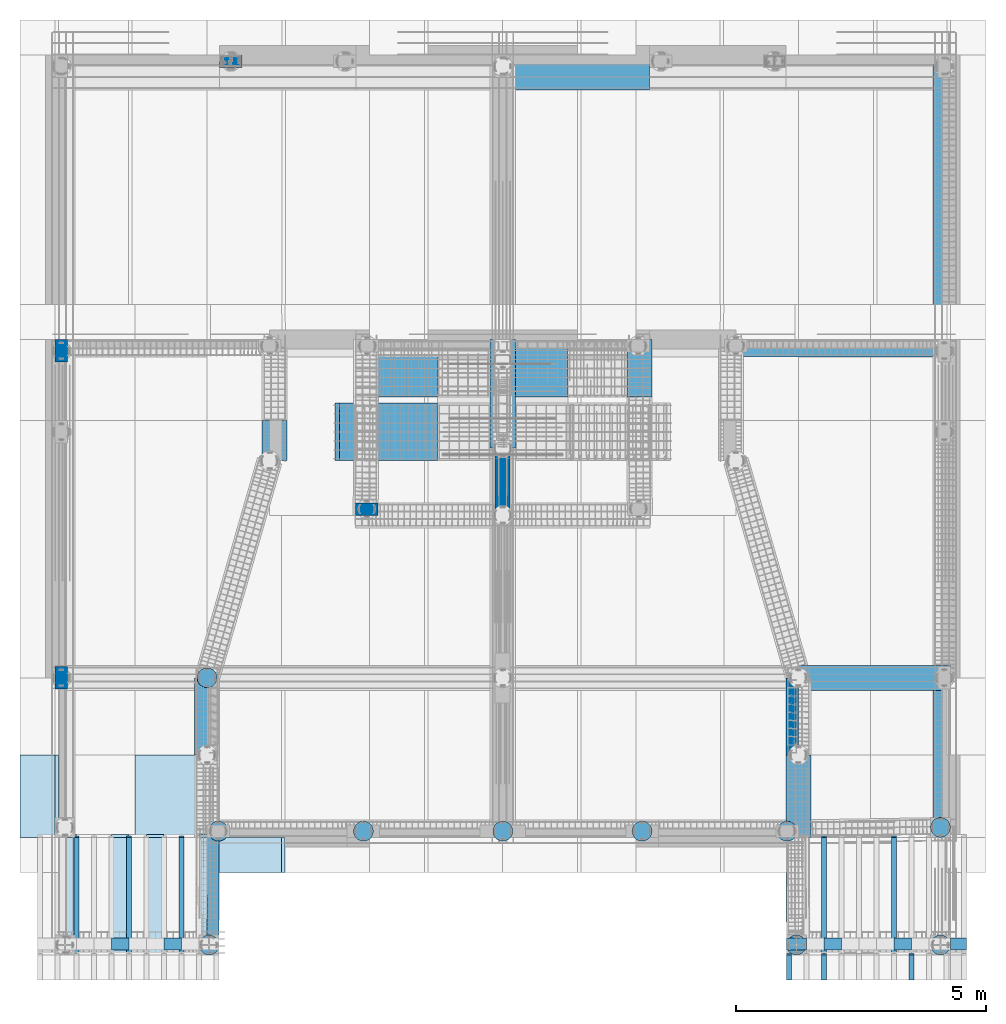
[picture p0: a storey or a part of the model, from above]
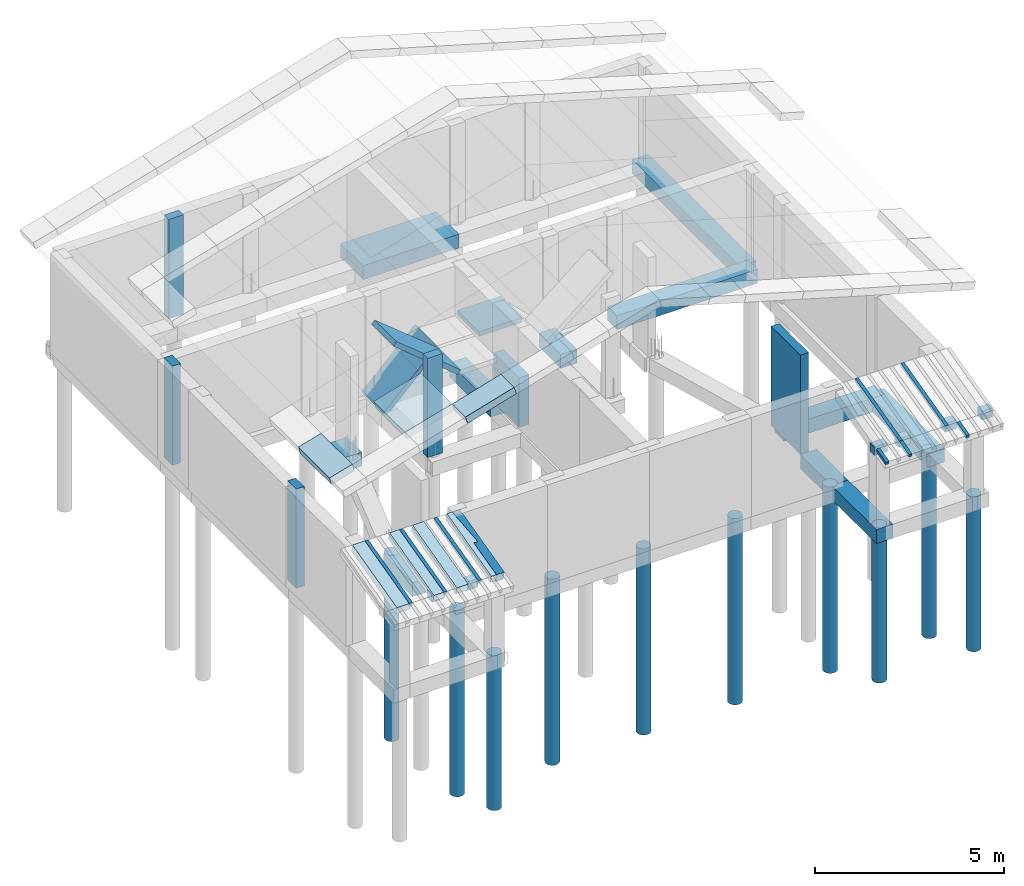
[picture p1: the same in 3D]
Properties of the parts of a building model (IFC4), part 1 of 5

# File
Description: ViewDefinition [CoordinationView]
Made in: IFC file generated by ModeSt (Tecnisoft s.a.s.)

# IfcBuildingStorey (2)
In: Villa
Name | Elevation (m)
Storey 0 | 0
Storey 1 | 3.2

# IfcBeam: 11 TRV SUI PALI (50)
In: Storey 0
Type - PredefinedType: BEAM; Material: Calcestruzzo classe C28/35
Description: 11 TRV SUI PALI - Cemento armato
Pset_BeamCommon - LoadBearing: yes
BaseQuantities - ?: 0.225 m2
Name | BaseQuantities, ? (m3) | BaseQuantities, ? (m)
2 x 4005 | 0.684 | 3.04
2 x 4005 | 1.32975 | 5.91
4049 | 0.3465 | 1.54
2 x 4003 | 0.63 | 2.8
4024 | 0.18 | 0.8
4030 | 0.48825 | 2.17
4030 | 1.28025 | 5.69
4030 | 0.73125 | 3.25
4030 | 0.71775 | 3.19
4030 | 0.3015 | 1.34
4013 | 0.71775 | 3.19
4013 | 1.1565 | 5.14
4013 | 0.3645 | 1.62
4013 | 1.28025 | 5.69
4013 | 0.52875 | 2.35
4059 | 0.738 | 3.28
4049 | 0.5315 | 2.36222
2 x 4003 | 0.69975 | 3.11
4049 | 0.37125 | 1.65
4051 | 1.0162 | 4.51643
4024 | 0.3645 | 1.62
2 x 4010 | 0.96525 | 4.29
2 x 4010 | 0.38925 | 1.73
2 x 4010 | 0.65925 | 2.93
4056 | 0.25875 | 1.15
2 x 4006 | 0.6615 | 2.94
4056 | 0.531005 | 2.36002
4050 | 0.3465 | 1.54
4036 | 0.18 | 0.8
4047 | 0.71775 | 3.19
4047 | 1.1565 | 5.14
4047 | 0.3645 | 1.62
4047 | 1.28025 | 5.69
4047 | 0.52875 | 2.35
4117 | 0.738 | 3.28
4050 | 0.5315 | 2.36222
4003 | 0.684 | 3.04
4050 | 0.37125 | 1.65
4052 | 1.0162 | 4.51643
4036 | 0.3645 | 1.62
4055 | 0.25875 | 1.15
4055 | 0.531005 | 2.36002

# IfcBeam: 14 TRAVE 30X45, 1030
In: Storey 1
Type - PredefinedType: BEAM; Material: Calcestruzzo classe C28/35
Description: 14 TRAVE 30X45 - Cemento armato
Pset_BeamCommon - LoadBearing: yes
BaseQuantities - ?: 0.135 m2; ?: 0.76815 m3; ?: 5.69 m

# IfcBeam: 16 TRAVE 30X30 (8)
In: Storey 1
Type - PredefinedType: BEAM; Material: Calcestruzzo classe C28/35
Description: 16 TRAVE 30X30 - Cemento armato
Pset_BeamCommon - LoadBearing: yes
BaseQuantities - ?: 0.09 m2
Name | BaseQuantities, ? (m3) | BaseQuantities, ? (m)
1030 | 0.2871 | 3.19
1030 | 0.2925 | 3.25
1030 | 0.1953 | 2.17
1030 | 0.1206 | 1.34
2088 | 0.2871 | 3.19
2088 | 0.2925 | 3.25
2088 | 0.1206 | 1.34
2088 | 0.1953 | 2.17

# IfcBeam: 17 TRAVE TAVOLA LEGNO 25X25 CA (4)
In: Storey 1
Type - PredefinedType: BEAM; Material: Calcestruzzo classe C28/35
Description: 17 TRAVE TAVOLA LEGNO 25X25 CA - Cemento armato
Pset_BeamCommon - LoadBearing: yes
BaseQuantities - ?: 0.0625 m2
Name | BaseQuantities, ? (m3) | BaseQuantities, ? (m)
2004 | 0.104225 | 1.6676
2004 | 0.0935769 | 1.49723
2062 | 0.104225 | 1.6676
2062 | 0.093577 | 1.49723

# IfcBeam: 20 TRAVE 30X30, 2204
In: Storey 1
Type - PredefinedType: BEAM; Material: Calcestruzzo classe C28/35
Description: 20 TRAVE 30X30 - Cemento armato
Pset_BeamCommon - LoadBearing: yes
BaseQuantities - ?: 0.09 m2; ?: 0.5121 m3; ?: 5.69 m

# IfcBeam: 21 TRV winkler SUI PALI (6)
In: Storey 0
Type - PredefinedType: BEAM; Material: Calcestruzzo classe C28/35
Description: 21 TRV winkler SUI PALI - Cemento armato
Pset_BeamCommon - LoadBearing: yes
BaseQuantities - ?: 0.54 m2
Name | BaseQuantities, ? (m3) | BaseQuantities, ? (m)
2 x 4011 | 1.7766 | 3.29
2 x 4011 | 1.4742 | 2.73
2 x 4011 | 1.5822 | 2.93

# IfcBeam: 22 Scala (8)
In: Storey 0
Type - PredefinedType: BEAM; Material: Calcestruzzo classe C28/35
Description: 22 Scala - Cemento armato
Pset_BeamCommon - LoadBearing: yes
BaseQuantities - ?: 0.1725 m2
Name | BaseQuantities, ? (m3) | BaseQuantities, ? (m)
2 x 4068 | 0.22425 | 1.3
2 x 4068 | 0.393999 | 2.28405
2 x 1009 | 0.22425 | 1.3
2 x 1009 | 0.436449 | 2.53014

# IfcBeam: 3 TRAVE 25X50 (200)
In: Storey 1
Type - PredefinedType: BEAM; Material: Calcestruzzo classe C28/35
Description: 3 TRAVE 25X50 - Cemento armato
Pset_BeamCommon - LoadBearing: yes
BaseQuantities - ?: 0.125 m2
Name | BaseQuantities, ? (m3) | BaseQuantities, ? (m)
2 x 1061 | 0.05375 | 0.43
2 x 1061 | 0.18625 | 1.49
2 x 1061 | 0.05625 | 0.45
2 x 1010 | 0.18375 | 1.47
2 x 1010 | 0.03125 | 0.25
2 x 1011 | 0.18375 | 1.47
2 x 1011 | 0.15625 | 1.25
1010 | 0.03375 | 0.27
1082 | 0.2025 | 1.62
1024 | 0.13625 | 1.09
2 x 1006 | 0.03 | 0.24
2 x 1006 | 0.035 | 0.28
2 x 1007 | 0.075 | 0.6
2 x 1005 | 0.18625 | 1.49
2 x 1005 | 0.2 | 1.6
1011 | 0.03375 | 0.27
1008 | 0.2 | 1.6
1008 | 0.18 | 1.44
2 x 1005 | 0.18 | 1.44
1008 | 0.15625 | 1.25
2 x 1061 | 0.16375 | 1.31
2 x 1061 | 0.195 | 1.56
2 x 1006 | 0.185 | 1.48
2 x 1005 | 0.22 | 1.76
2 x 1006 | 0.195 | 1.56
2 x 1007 | 0.197488 | 1.5799
2 x 1005 | 0.195 | 1.56
2 x 1061 | 0.1375 | 1.1
2 x 1006 | 0.1375 | 1.1
2 x 1005 | 0.1375 | 1.1
2 x 1007 | 0.1375 | 1.1
2 x 1010 | 0.19625 | 1.57
2 x 1010 | 0.15625 | 1.25
2 x 1011 | 0.19625 | 1.57
2 x 1011 | 0.03125 | 0.25
2 x 1010 | 0.14375 | 1.15
2 x 1010 | 0.195 | 1.56
2 x 1011 | 0.185 | 1.48
2 x 1011 | 0.195 | 1.56
2 x 1010 | 0.1375 | 1.1
2 x 1011 | 0.1375 | 1.1
1023 | 0.20625 | 1.65
2 x 2011 | 0.202951 | 1.62361
2 x 2011 | 0.19145 | 1.5316
2 x 2011 | 0.1954 | 1.5632
2 x 2011 | 0.204152 | 1.63322
2 x 2011 | 0.19265 | 1.5412
2 x 2011 | 0.1432 | 1.1456
2 x 2010 | 0.19145 | 1.5316
2 x 2010 | 0.204152 | 1.63322
2 x 2010 | 0.162951 | 1.30361
2 x 2010 | 0.19265 | 1.5412
2 x 2010 | 0.202951 | 1.62361
2 x 2010 | 0.1432 | 1.1456
2011 | 0.0352003 | 0.281603
2010 | 0.0352003 | 0.281603
2 x 2010 | 0.0324519 | 0.259615
2 x 2068 | 0.162951 | 1.30361
2 x 2068 | 0.19265 | 1.5412
2 x 2068 | 0.202951 | 1.62361
2 x 2068 | 0.1432 | 1.1456
2068 | 0.0352003 | 0.281603
2 x 2068 | 0.0324519 | 0.259615
1061 | 0.02875 | 0.23
10 x 1061 | 0.04375 | 0.35
1061 | 0.015 | 0.12
1061 | 0.02 | 0.16
2003 | 0.194201 | 1.55361
2003 | 0.0585502 | 0.468401
2082 | 0.2025 | 1.62
2024 | 0.13625 | 1.09
2 x 2006 | 0.03125 | 0.25
2 x 2006 | 0.0364005 | 0.291204
2 x 2005 | 0.194201 | 1.55361
2 x 2005 | 0.20845 | 1.6676
2008 | 0.20845 | 1.6676
2008 | 0.187154 | 1.49723
2 x 2005 | 0.187154 | 1.49723
2008 | 0.162951 | 1.30361
2003 | 0.1705 | 1.364
2003 | 0.202951 | 1.62361
2 x 2006 | 0.19265 | 1.5412
2 x 2005 | 0.22905 | 1.8324
2 x 2006 | 0.202951 | 1.62361
2 x 2005 | 0.202951 | 1.62361
2003 | 0.1432 | 1.1456
2 x 2006 | 0.1432 | 1.1456
2 x 2005 | 0.1432 | 1.1456
2081 | 0.20625 | 1.65
2 x 2068 | 0.187154 | 1.49723
2 x 2068 | 0.20845 | 1.6676
2003 | 0.187154 | 1.49723
2003 | 0.20845 | 1.6676
2 x 1007 | 0.175 | 1.4
2 x 1010 | 0.04125 | 0.33
1061 | 0.0443749 | 0.355
1010 | 0.0337501 | 0.27
1094 | 0.2025 | 1.62
1036 | 0.13625 | 1.09
1011 | 0.0337501 | 0.27
1066 | 0.2 | 1.6
1066 | 0.18 | 1.44
1066 | 0.15625 | 1.25
1037 | 0.20625 | 1.65
2011 | 0.0352004 | 0.281603
2010 | 0.0352004 | 0.281603
2068 | 0.0352004 | 0.281603
1061 | 0.028125 | 0.225
1061 | 0.0437499 | 0.349999
1061 | 0.0200001 | 0.160001
1061 | 0.0149999 | 0.119999
2002 | 0.194201 | 1.55361
2002 | 0.0585502 | 0.468401
2094 | 0.2025 | 1.62
2036 | 0.13625 | 1.09
2066 | 0.20845 | 1.6676
2066 | 0.187154 | 1.49723
2066 | 0.162951 | 1.30361
2002 | 0.1705 | 1.364
2002 | 0.202951 | 1.62361
2002 | 0.1432 | 1.1456
2095 | 0.20625 | 1.65
2002 | 0.187158 | 1.49726
2002 | 0.208454 | 1.66763

# IfcBeam: 5 TRAVE TAVOLA LEGNO 16X20 (4)
In: Storey 1
Type - PredefinedType: BEAM; Material: Calcestruzzo classe C28/35
Description: 5 TRAVE TAVOLA LEGNO 16X20 - Cemento armato
Pset_BeamCommon - LoadBearing: yes
BaseQuantities - ?: 0.032 m2
Name | BaseQuantities, ? (m3) | BaseQuantities, ? (m)
1004 | 0.0512 | 1.6
1004 | 0.04608 | 1.44
1062 | 0.0512 | 1.6
1062 | 0.04608 | 1.44

# IfcBeam: 6 TRAVE LEGNO 24X28 (44)
Type - PredefinedType: BEAM; Material: Legname a media elasticità
Description: 6 TRAVE LEGNO 24X28 - Legno
Pset_BeamCommon - LoadBearing: yes
BaseQuantities - ?: 0.0672 m2
Name | In | BaseQuantities, ? (m3) | BaseQuantities, ? (m)
1013 | Storey 0 | 0.162986 | 2.42539
1049 | Storey 0 | 0.163782 | 2.43723
1047 | Storey 0 | 0.162986 | 2.42539
1050 | Storey 0 | 0.163782 | 2.43723
1053 | Storey 1 | 0.345408 | 5.14
1081 | Storey 1 | 0.345408 | 5.14
1025 | Storey 1 | 0.214368 | 3.19
1025 | Storey 1 | 0.2184 | 3.25
1029 | Storey 1 | 0.214368 | 3.19
1029 | Storey 1 | 0.2184 | 3.25
1029 | Storey 1 | 0.073248 | 1.09
1028 | Storey 1 | 0.214368 | 3.19
1028 | Storey 1 | 0.2184 | 3.25
1028 | Storey 1 | 0.073248 | 1.09
1053 | Storey 1 | 0.382368 | 5.69
1081 | Storey 1 | 0.382368 | 5.69
1087 | Storey 1 | 0.382368 | 5.69
1086 | Storey 1 | 0.382368 | 5.69
1026 | Storey 1 | 0.382368 | 5.69
1053 | Storey 1 | 0.109214 | 1.62521
1081 | Storey 1 | 0.108864 | 1.62
1053 | Storey 1 | 0.11088 | 1.65
1053 | Storey 1 | 0.103488 | 1.54
1003 | Storey 1 | 0.02352 | 0.35
1054 | Storey 1 | 0.345408 | 5.14
1095 | Storey 1 | 0.345408 | 5.14
1035 | Storey 1 | 0.214368 | 3.19
1035 | Storey 1 | 0.2184 | 3.25
1031 | Storey 1 | 0.214368 | 3.19
1031 | Storey 1 | 0.2184 | 3.25
1031 | Storey 1 | 0.073248 | 1.09
1032 | Storey 1 | 0.214368 | 3.19
1032 | Storey 1 | 0.2184 | 3.25
1032 | Storey 1 | 0.073248 | 1.09
1054 | Storey 1 | 0.382368 | 5.69
1095 | Storey 1 | 0.382368 | 5.69
1089 | Storey 1 | 0.382368 | 5.69
1090 | Storey 1 | 0.382368 | 5.69
1034 | Storey 1 | 0.382368 | 5.69
1054 | Storey 1 | 0.109214 | 1.62521
1095 | Storey 1 | 0.108864 | 1.62
1054 | Storey 1 | 0.11088 | 1.65
1054 | Storey 1 | 0.103488 | 1.54
1119 | Storey 1 | 0.0215039 | 0.319998

# IfcBeam: 7 TRAVE 25X30 (26)
Type - PredefinedType: BEAM; Material: Calcestruzzo classe C28/35
Description: 7 TRAVE 25X30 - Cemento armato
Pset_BeamCommon - LoadBearing: yes
BaseQuantities - ?: 0.075 m2
Name | In | BaseQuantities, ? (m3) | BaseQuantities, ? (m)
4088 | Storey 0 | 0.0675 | 0.9
4088 | Storey 0 | 0.09525 | 1.27
1071 | Storey 1 | 0.12375 | 1.65
1071 | Storey 1 | 0.3855 | 5.14
1071 | Storey 1 | 0.1215 | 1.62
1071 | Storey 1 | 0.42675 | 5.69
1071 | Storey 1 | 0.1155 | 1.54
2187 | Storey 1 | 0.42675 | 5.69
2071 | Storey 1 | 0.1215 | 1.62
2071 | Storey 1 | 0.12375 | 1.65
2071 | Storey 1 | 0.1155 | 1.54
2071 | Storey 1 | 0.3855 | 5.14
1027 | Storey 1 | 0.08625 | 1.15
1027 | Storey 1 | 0.09525 | 1.27
1105 | Storey 1 | 0.12375 | 1.65
1105 | Storey 1 | 0.3855 | 5.14
1105 | Storey 1 | 0.1215 | 1.62
1105 | Storey 1 | 0.42675 | 5.69
1105 | Storey 1 | 0.1155 | 1.54
2221 | Storey 1 | 0.42675 | 5.69
2105 | Storey 1 | 0.1215 | 1.62
2105 | Storey 1 | 0.12375 | 1.65
2105 | Storey 1 | 0.1155 | 1.54
2105 | Storey 1 | 0.3855 | 5.14
1033 | Storey 1 | 0.08625 | 1.15
1033 | Storey 1 | 0.09525 | 1.27

# IfcBeam: 8 CORRENTE 10X10 (40)
In: Storey 0
Type - PredefinedType: BEAM; Material: Legname a media elasticità
Description: 8 CORRENTE 10X10 - Legno
Pset_BeamCommon - LoadBearing: yes
BaseQuantities - ?: 0.01 m2
Name | BaseQuantities, ? (m3) | BaseQuantities, ? (m)
1014 | 0.0242539 | 2.42539
1015 | 0.0242539 | 2.42539
1016 | 0.0242539 | 2.42539
1017 | 0.0242539 | 2.42539
1019 | 0.0242539 | 2.42539
1020 | 0.0242539 | 2.42539
1021 | 0.0242539 | 2.42539
1022 | 0.0051604 | 0.51604
1022 | 0.0242539 | 2.42539
1021 | 0.0051604 | 0.51604
1020 | 0.0051604 | 0.51604
1019 | 0.0051604 | 0.51604
1017 | 0.0051604 | 0.51604
1016 | 0.0051604 | 0.51604
1015 | 0.0051604 | 0.51604
1014 | 0.0051604 | 0.51604
1013 | 0.0051604 | 0.51604
1049 | 0.0051604 | 0.51604
1012 | 0.0051604 | 0.51604
1012 | 0.0242539 | 2.42539
1041 | 0.0242539 | 2.42539
1046 | 0.0242539 | 2.42539
1045 | 0.0242539 | 2.42539
1044 | 0.0242539 | 2.42539
1043 | 0.0242539 | 2.42539
1040 | 0.0242539 | 2.42539
1039 | 0.0242539 | 2.42539
1038 | 0.0242539 | 2.42539
1038 | 0.00516624 | 0.516624
1039 | 0.00516624 | 0.516624
1040 | 0.00516624 | 0.516624
1044 | 0.00516624 | 0.516624
1045 | 0.00516624 | 0.516624
1046 | 0.00516624 | 0.516624
1047 | 0.00516624 | 0.516624
1050 | 0.00516624 | 0.516624
1043 | 0.00516624 | 0.516624
1041 | 0.00516624 | 0.516624
1048 | 0.00516624 | 0.516624
1048 | 0.0242539 | 2.42539

# IfcBeam: 9 TRAVE LEGNO 24X28 COPERTURA (99)
Type - PredefinedType: BEAM; Material: Legname a media elasticità
Description: 9 TRAVE LEGNO 24X28 COPERTURA - Legno
Pset_BeamCommon - LoadBearing: yes
BaseQuantities - ?: 0.0672 m2
Name | In | BaseQuantities, ? (m3) | BaseQuantities, ? (m)
4001 | Storey 0 | 0.028896 | 0.43
8 x 4001 | Storey 0 | 0.02352 | 0.35
4001 | Storey 0 | 0.02688 | 0.4
4175 | Storey 0 | 0.023856 | 0.355
4175 | Storey 0 | 0.028896 | 0.43
4 x 4175 | Storey 0 | 0.02352 | 0.35
4175 | Storey 0 | 0.023184 | 0.344999
4175 | Storey 0 | 0.02352 | 0.349999
4175 | Storey 0 | 0.02688 | 0.400001
4175 | Storey 0 | 0.0215039 | 0.319998
2053 | Storey 1 | 0.382368 | 5.69
2197 | Storey 1 | 0.382368 | 5.69
2087 | Storey 1 | 0.382368 | 5.69
2086 | Storey 1 | 0.382368 | 5.69
2026 | Storey 1 | 0.382368 | 5.69
2018 | Storey 1 | 0.108864 | 1.62
2139 | Storey 1 | 0.103488 | 1.54
2018 | Storey 1 | 0.345408 | 5.14
2139 | Storey 1 | 0.345408 | 5.14
2025 | Storey 1 | 0.214368 | 3.19
2025 | Storey 1 | 0.2184 | 3.25
2029 | Storey 1 | 0.214368 | 3.19
2029 | Storey 1 | 0.2184 | 3.25
2029 | Storey 1 | 0.235872 | 3.51
2028 | Storey 1 | 0.214368 | 3.19
2028 | Storey 1 | 0.2184 | 3.25
2028 | Storey 1 | 0.235872 | 3.51
2139 | Storey 1 | 0.108864 | 1.62
2023 | Storey 1 | 0.04704 | 0.7
2025 | Storey 1 | 0.04704 | 0.7
2 x 2028 | Storey 1 | 0.04704 | 0.7
2 x 2029 | Storey 1 | 0.04704 | 0.7
2030 | Storey 1 | 0.04704 | 0.7
2139 | Storey 1 | 0.04704 | 0.7
2146 | Storey 1 | 0.04704 | 0.7
2057 | Storey 1 | 0.0470448 | 0.700071
2018 | Storey 1 | 0.11088 | 1.65
2018 | Storey 1 | 0.103488 | 1.54
2013 | Storey 1 | 0.04704 | 0.7
2129 | Storey 1 | 0.04704 | 0.7
2 x 2018 | Storey 1 | 0.04704 | 0.7
2053 | Storey 1 | 0.04704 | 0.700001
2197 | Storey 1 | 0.04704 | 0.700001
2026 | Storey 1 | 0.04704 | 0.700001
2087 | Storey 1 | 0.04704 | 0.700001
2086 | Storey 1 | 0.04704 | 0.700001
2262 | Storey 1 | 0.04704 | 0.700001
2245 | Storey 1 | 0.04704 | 0.700001
2054 | Storey 1 | 0.382368 | 5.69
2211 | Storey 1 | 0.382368 | 5.69
2089 | Storey 1 | 0.382368 | 5.69
2090 | Storey 1 | 0.382368 | 5.69
2034 | Storey 1 | 0.382368 | 5.69
2042 | Storey 1 | 0.108864 | 1.62
2153 | Storey 1 | 0.103488 | 1.54
2042 | Storey 1 | 0.345408 | 5.14
2153 | Storey 1 | 0.345408 | 5.14
2035 | Storey 1 | 0.214368 | 3.19
2035 | Storey 1 | 0.2184 | 3.25
2031 | Storey 1 | 0.214368 | 3.19
2031 | Storey 1 | 0.2184 | 3.25
2031 | Storey 1 | 0.235872 | 3.51
2032 | Storey 1 | 0.214368 | 3.19
2032 | Storey 1 | 0.2184 | 3.25
2032 | Storey 1 | 0.235872 | 3.51
2153 | Storey 1 | 0.108864 | 1.62
2037 | Storey 1 | 0.04704 | 0.7
2035 | Storey 1 | 0.04704 | 0.7
2 x 2032 | Storey 1 | 0.04704 | 0.7
2 x 2031 | Storey 1 | 0.04704 | 0.7
2153 | Storey 1 | 0.04704 | 0.7
2058 | Storey 1 | 0.0470448 | 0.700071
2042 | Storey 1 | 0.111552 | 1.66
2042 | Storey 1 | 0.103488 | 1.54
2047 | Storey 1 | 0.04704 | 0.7
2163 | Storey 1 | 0.04704 | 0.7
2042 | Storey 1 | 0.04704 | 0.7
2042 | Storey 1 | 0.046368 | 0.69
2054 | Storey 1 | 0.04704 | 0.700001
2211 | Storey 1 | 0.04704 | 0.700001
2034 | Storey 1 | 0.04704 | 0.700001
2089 | Storey 1 | 0.04704 | 0.700001
2090 | Storey 1 | 0.04704 | 0.700001
2279 | Storey 1 | 0.04704 | 0.700001

# IfcColumn: 1 PILASTRO 25X45 (26)
Type - PredefinedType: COLUMN; Material: Calcestruzzo classe C28/35
Description: 1 PILASTRO 25X45 - Cemento armato
Pset_ColumnCommon - LoadBearing: yes
BaseQuantities - ?: 0.1125 m2
Name | In | BaseQuantities, ? (m3) | BaseQuantities, ? (m)
6 | Storey 0 | 0.36 | 3.2
17 | Storey 0 | 0.36 | 3.2
22 | Storey 0 | 0.36 | 3.2
23 | Storey 0 | 0.36 | 3.2
29 | Storey 0 | 0.36 | 3.2
30 | Storey 0 | 0.36 | 3.2
10 | Storey 0 | 0.36 | 3.2
18 | Storey 0 | 0.36 | 3.2
26 | Storey 0 | 0.36 | 3.2
25 | Storey 0 | 0.36 | 3.2
33 | Storey 0 | 0.36 | 3.2
32 | Storey 0 | 0.36 | 3.2
22 | Storey 1 | 0.219375 | 1.95
23 | Storey 1 | 0.275625 | 2.45
30 | Storey 1 | 0.275625 | 2.45
22 | Storey 1 | 0.21375 | 1.9
23 | Storey 1 | 0.21375 | 1.9
6 | Storey 1 | 0.3915 | 3.48
17 | Storey 1 | 0.489375 | 4.35
26 | Storey 1 | 0.219375 | 1.95
25 | Storey 1 | 0.275625 | 2.45
32 | Storey 1 | 0.275625 | 2.45
26 | Storey 1 | 0.21375 | 1.9
25 | Storey 1 | 0.21375 | 1.9
10 | Storey 1 | 0.3915 | 3.48
18 | Storey 1 | 0.489375 | 4.35

# IfcColumn: 1 muro pilastro (6)
Type - PredefinedType: COLUMN
Material: Calcestruzzo classe C28/35 0.25 m
Pset_WallCommon - LoadBearing: yes
Name | In | Description | BaseQuantities, ? (m2) | BaseQuantities, ? (m3) | BaseQuantities, ? (m)
35 | Storey 0 | Wall number 35 | 0.385 | 1.232 | 3.2
36 | Storey 0 | Wall number 36 | 0.2 | 0.64 | 3.2
38 | Storey 0 | Wall number 38 | 0.385 | 1.232 | 3.2
39 | Storey 0 | Wall number 39 | 0.2 | 0.64 | 3.2
36 | Storey 1 | Wall number 36 | 0.2 | 0.77 | 3.85
39 | Storey 1 | Wall number 39 | 0.2 | 0.77 | 3.85

# IfcColumn: 10 PILASTRO 40X25 (2)
In: Storey 1
Type - PredefinedType: COLUMN; Material: Calcestruzzo classe C28/35
Description: 10 PILASTRO 40X25 - Cemento armato
Pset_ColumnCommon - LoadBearing: yes
BaseQuantities - ?: 0.1 m2; ?: 0.348 m3; ?: 3.48 m
Name
12
13

# IfcColumn: 12 PILASTRO 25X65 (4)
Type - PredefinedType: COLUMN; Material: Calcestruzzo classe C28/35
Description: 12 PILASTRO 25X65 - Cemento armato
Pset_ColumnCommon - LoadBearing: yes
BaseQuantities - ?: 0.1625 m2
Name | In | BaseQuantities, ? (m3) | BaseQuantities, ? (m)
7 | Storey 0 | 0.52 | 3.2
9 | Storey 0 | 0.52 | 3.2
7 | Storey 1 | 0.69875 | 4.3
9 | Storey 1 | 0.69875 | 4.3

# IfcColumn: 13 PILASTRO 100X30 (2)
Type - PredefinedType: COLUMN; Material: Calcestruzzo classe C28/35
Description: 13 PILASTRO 100X30 - Cemento armato
Pset_ColumnCommon - LoadBearing: yes
BaseQuantities - ?: 0.3 m2
Name | In | BaseQuantities, ? (m3) | BaseQuantities, ? (m)
15 | Storey 0 | 0.96 | 3.2
15 | Storey 1 | 1.56 | 5.2

# IfcColumn: 15 PILASTRO 25x90 (2)
Type - PredefinedType: COLUMN; Material: Calcestruzzo classe C28/35
Description: 15 PILASTRO 25x90 - Cemento armato
Pset_ColumnCommon - LoadBearing: yes
BaseQuantities - ?: 0.225 m2
Name | In | BaseQuantities, ? (m3) | BaseQuantities, ? (m)
8 | Storey 0 | 0.72 | 3.2
8 | Storey 1 | 1.17 | 5.2

# IfcColumn: 18 PILASTRO 80x30 (4)
Type - PredefinedType: COLUMN; Material: Calcestruzzo classe C28/35
Description: 18 PILASTRO 80x30 - Cemento armato
Pset_ColumnCommon - LoadBearing: yes
BaseQuantities - ?: 0.24 m2
Name | In | BaseQuantities, ? (m3) | BaseQuantities, ? (m)
2 x 24 | Storey 0 | 0.384 | 1.6
24 | Storey 1 | 0.792 | 3.3
24 | Storey 1 | 0.456 | 1.9

# IfcColumn: 19 PILASTRO 45X30 (2)
Type - PredefinedType: COLUMN; Material: Calcestruzzo classe C28/35
Description: 19 PILASTRO 45X30 - Cemento armato
Pset_ColumnCommon - LoadBearing: yes
BaseQuantities - ?: 0.135 m2
Name | In | BaseQuantities, ? (m3) | BaseQuantities, ? (m)
31 | Storey 0 | 0.432 | 3.2
31 | Storey 1 | 0.4455 | 3.3

# IfcColumn: 2 PILASTRO 45X25 (18)
Type - PredefinedType: COLUMN; Material: Calcestruzzo classe C28/35
Description: 2 PILASTRO 45X25 - Cemento armato
Pset_ColumnCommon - LoadBearing: yes
BaseQuantities - ?: 0.1125 m2
Name | In | BaseQuantities, ? (m3) | BaseQuantities, ? (m)
14 | Storey 0 | 0.36 | 3.2
21 | Storey 0 | 0.36 | 3.2
19 | Storey 0 | 0.36 | 3.2
28 | Storey 0 | 0.36 | 3.2
16 | Storey 0 | 0.36 | 3.2
27 | Storey 0 | 0.36 | 3.2
20 | Storey 0 | 0.36 | 3.2
34 | Storey 0 | 0.36 | 3.2
21 | Storey 1 | 0.07875 | 0.7
28 | Storey 1 | 0.07875 | 0.7
21 | Storey 1 | 0.21375 | 1.9
19 | Storey 1 | 0.2925 | 2.6
14 | Storey 1 | 0.2925 | 2.6
27 | Storey 1 | 0.07875 | 0.7
34 | Storey 1 | 0.07875 | 0.7
27 | Storey 1 | 0.21375 | 1.9
20 | Storey 1 | 0.2925 | 2.6
16 | Storey 1 | 0.2925 | 2.6

# IfcColumn: 3 muro pilastro 30 centrale (3)
Type - PredefinedType: COLUMN
Description: Wall number 37; Material: Calcestruzzo classe C28/35 0.3 m
Pset_WallCommon - LoadBearing: yes
BaseQuantities - ?: 0.402 m2
Name | In | BaseQuantities, ? (m3) | BaseQuantities, ? (m)
2 x 37 | Storey 0 | 0.6432 | 1.6
37 | Storey 1 | 2.0904 | 5.2

# IfcColumn: 4 PILASTRO LOGGIATO 40X40 (8)
Type - PredefinedType: COLUMN; Material: Calcestruzzo classe C28/35
Description: 4 PILASTRO LOGGIATO 40X40 - Cemento armato
Pset_ColumnCommon - LoadBearing: yes
BaseQuantities - ?: 0.16 m2
Name | In | BaseQuantities, ? (m3) | BaseQuantities, ? (m)
1 | Storey 0 | 0.416 | 2.6
5 | Storey 0 | 0.512 | 3.2
2 | Storey 0 | 0.416 | 2.6
4 | Storey 0 | 0.416 | 2.6
11 | Storey 0 | 0.512 | 3.2
3 | Storey 0 | 0.416 | 2.6
5 | Storey 1 | 0.416 | 2.6
11 | Storey 1 | 0.416 | 2.6

# IfcPile (40)
In: Storey 0
PredefinedType: SUPPORT
Name | Description | ? (m3)
11 x 1 | 2 PALO FONDAZIONE 5 m | 0.628319
29 x 1 | 1 PALO FONDAZIONE 6 m | 0.753982

# IfcReinforcingBar (675)
SteelGrade: B450C
Name | In | NominalDiameter (m) | CrossSectionArea (m2) | BarLength (m)
4 x  | Storey 0 | 0.016 | 0.00020106 | 1.39193
4 x  | Storey 0 | 0.016 | 0.00020106 | 2.88943
4 x  | Storey 0 | 0.008 | 0.000050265 | 1.5788
2 x  | Storey 1 | 0.016 | 0.00020106 | 1.39193
14 x  | Storey 1 | 0.016 | 0.00020106 | 3.84
2 x  | Storey 1 | 0.016 | 0.00020106 | 2.88943
2 x  | Storey 1 | 0.008 | 0.000050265 | 1.5788
 | Storey 1 | 0.008 | 0.000050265 | 1.2086
9 x  | Storey 1 | 0.018 | 0.00025447 | 1.31973
9 x  | Storey 1 | 0.016 | 0.00020106 | 1.32193
10 x  | Storey 1 | 0.018 | 0.00025447 | 3.92
10 x  | Storey 1 | 0.016 | 0.00020106 | 3.92
 | Storey 1 | 0.018 | 0.00025447 | 3.61723
4 x  | Storey 1 | 0.016 | 0.00020106 | 3.61943
12 x  | Storey 1 | 0.008 | 0.000050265 | 1.37881
17 x  | Storey 1 | 0.008 | 0.000050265 | 0.428429
2 x  | Storey 1 | 0.018 | 0.00025447 | 4.43723
2 x  | Storey 1 | 0.016 | 0.00020106 | 4.43943
2 x  | Storey 1 | 0.008 | 0.000050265 | 1.7788
 | Storey 1 | 0.008 | 0.000050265 | 1.02152
3 x  | Storey 1 | 0.02 | 0.00031416 | 1.39754
3 x  | Storey 1 | 0.016 | 0.00020106 | 1.40193
3 x  | Storey 1 | 0.02 | 0.00031416 | 4
3 x  | Storey 1 | 0.016 | 0.00020106 | 4
 | Storey 1 | 0.02 | 0.00031416 | 5.33504
 | Storey 1 | 0.016 | 0.00020106 | 5.33943
 | Storey 1 | 0.008 | 0.000050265 | 2.27879
 | Storey 1 | 0.008 | 0.000050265 | 1.45481
3 x  | Storey 1 | 0.008 | 0.000050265 | 0.428428
 | Storey 1 | 0.008 | 0.000050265 | 1.02149
9 x  | Storey 1 | 0.016 | 0.00020106 | 1.24193
 | Storey 1 | 0.008 | 0.000050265 | 1.20881
5 x  | Storey 1 | 0.016 | 0.00020106 | 1.29193
2 x  | Storey 1 | 0.008 | 0.000050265 | 1.27881
2 x  | Storey 1 | 0.018 | 0.00025447 | 2.73723
6 x  | Storey 1 | 0.016 | 0.00020106 | 2.73943
3 x  | Storey 1 | 0.016 | 0.00020106 | 5.38943
 | Storey 1 | 0.008 | 0.000050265 | 2.57879
 | Storey 1 | 0.008 | 0.000050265 | 2.1654
2 x  | Storey 1 | 0.008 | 0.000050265 | 0.478429
 | Storey 1 | 0.008 | 0.000050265 | 2.35305
6 x  | Storey 1 | 0.008 | 0.000050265 | 1.3788
2 x  | Storey 1 | 0.008 | 0.000050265 | 0.42843
4 x  | Storey 1 | 0.016 | 0.00020106 | 4.48943
2 x  | Storey 1 | 0.022 | 0.00038013 | 1.47534
2 x  | Storey 1 | 0.016 | 0.00020106 | 1.48193
2 x  | Storey 1 | 0.022 | 0.00038013 | 4.08
2 x  | Storey 1 | 0.016 | 0.00020106 | 4.08
2 x  | Storey 1 | 0.022 | 0.00038013 | 2.73284
2 x  | Storey 1 | 0.018 | 0.00025447 | 3.98723
4 x  | Storey 1 | 0.016 | 0.00020106 | 3.98943
2 x  | Storey 1 | 0.008 | 0.000050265 | 0.478428
 | Storey 1 | 0.008 | 0.000050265 | 2.1788
 | Storey 1 | 0.008 | 0.000050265 | 1.85366
 | Storey 1 | 0.016 | 0.00020106 | 0.839429
4 x  | Storey 0 | 0.016 | 0.00020106 | 1.24193
4 x  | Storey 0 | 0.016 | 0.00020106 | 3.33943
2 x  | Storey 0 | 0.008 | 0.000050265 | 1.3788
 | Storey 0 | 0.008 | 0.000050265 | 0.428428
2 x  | Storey 1 | 0.016 | 0.00020106 | 2.58943
 | Storey 1 | 0.018 | 0.00025447 | 1.36973
 | Storey 1 | 0.016 | 0.00020106 | 1.37193
 | Storey 1 | 0.018 | 0.00025447 | 3.48723
 | Storey 1 | 0.016 | 0.00020106 | 3.48943
 | Storey 1 | 0.008 | 0.000050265 | 1.4788
2 x  | Storey 0 | 0.008 | 0.000050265 | 0.428429
 | Storey 1 | 0.016 | 0.00020106 | 0.83943
 | Storey 1 | 0.008 | 0.000050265 | 0.428427
2 x  | Storey 0 | 0.008 | 0.000050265 | 3.55879
 | Storey 0 | 0.008 | 0.000050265 | 0.42843
2 x  | Storey 0 | 0.008 | 0.000050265 | 2.26457
2 x  | Storey 0 | 0.008 | 0.000050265 | 2.91168
2 x  | Storey 1 | 0.02 | 0.00031416 | 3.98504
2 x  | Storey 1 | 0.008 | 0.000050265 | 2.0788
2 x  | Storey 1 | 0.008 | 0.000050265 | 1.11882
 | Storey 1 | 0.008 | 0.000050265 | 2.0031
2 x  | Storey 1 | 0.008 | 0.000050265 | 3.25879
 | Storey 1 | 0.008 | 0.000050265 | 2.95158
 | Storey 1 | 0.008 | 0.000050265 | 1.37506
11 x  | Storey 0 | 0.016 | 0.00020106 | 5.6
40 x  | Storey 0 | 0.008 | 0.000050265 | 1.00616
29 x  | Storey 0 | 0.016 | 0.00020106 | 6.6
2 x  | Storey 1 | 0.008 | 0.000050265 | 0.638887
 | Storey 1 | 0.016 | 0.00020106 | 3.40121
8 x  | Storey 1 | 0.008 | 0.000050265 | 1.48681
 | Storey 1 | 0.016 | 0.00020106 | 10.9956
 | Storey 1 | 0.016 | 0.00020106 | 8.99561
 | Storey 1 | 0.018 | 0.00025447 | 10.9956
 | Storey 1 | 0.018 | 0.00025447 | 8.99561
2 x  | Storey 1 | 0.014 | 0.00015394 | 3
 | Storey 1 | 0.012 | 0.0001131 | 3.50121
 | Storey 1 | 0.012 | 0.0001131 | 6.33121
8 x  | Storey 1 | 0.008 | 0.000050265 | 1.4868
 | Storey 1 | 0.016 | 0.00020106 | 8.5
2 x  | Storey 1 | 0.016 | 0.00020106 | 1.69142
 | Storey 1 | 0.012 | 0.0001131 | 2.38121
2 x  | Storey 1 | 0.012 | 0.0001131 | 3.26121
2 x  | Storey 1 | 0.012 | 0.0001131 | 3.08121
 | Storey 1 | 0.016 | 0.00020106 | 9.6922
2 x  | Storey 1 | 0.012 | 0.0001131 | 5.02043
2 x  | Storey 1 | 0.012 | 0.0001131 | 5.0192
 | Storey 1 | 0.016 | 0.00020106 | 4.91121
2 x  | Storey 1 | 0.012 | 0.0001131 | 4.75121
2 x  | Storey 0 | 0.008 | 0.000050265 | 2.58679
 | Storey 0 | 0.014 | 0.00015394 | 3.8923
 | Storey 0 | 0.014 | 0.00015394 | 3.89798
2 x  | Storey 0 | 0.014 | 0.00015394 | 3.08814
2 x  | Storey 0 | 0.014 | 0.00015394 | 1.66861
 | Storey 0 | 0.02 | 0.00031416 | 2.38121
 | Storey 0 | 0.016 | 0.00020106 | 2.38121
 | Storey 0 | 0.016 | 0.00020106 | 2.1183
 | Storey 0 | 0.014 | 0.00015394 | 2.1183
19 x  | Storey 1 | 0.006 | 0.000028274 | 1.49179
 | Storey 1 | 0.016 | 0.00020106 | 5
2 x  | Storey 1 | 0.016 | 0.00020106 | 4.09309
 | Storey 1 | 0.012 | 0.0001131 | 4.72621
 | Storey 1 | 0.012 | 0.0001131 | 2.61621
 | Storey 1 | 0.016 | 0.00020106 | 9.5
2 x  | Storey 1 | 0.016 | 0.00020106 | 5.49561
 | Storey 1 | 0.012 | 0.0001131 | 3.95121
 | Storey 1 | 0.012 | 0.0001131 | 3.00121
 | Storey 1 | 0.012 | 0.0001131 | 3.74121
 | Storey 1 | 0.016 | 0.00020106 | 1.5
2 x  | Storey 1 | 0.016 | 0.00020106 | 3.02121
2 x  | Storey 1 | 0.016 | 0.00020106 | 2.42121
4 x  | Storey 1 | 0.012 | 0.0001131 | 2.26121
4 x  | Storey 1 | 0.016 | 0.00020106 | 2.26121
4 x  | Storey 1 | 0.012 | 0.0001131 | 2.10121
8 x  | Storey 1 | 0.008 | 0.000050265 | 1.08682
2 x  | Storey 1 | 0.016 | 0.00020106 | 2.73121
3 x  | Storey 1 | 0.008 | 0.000050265 | 1.18682
 | Storey 1 | 0.016 | 0.00020106 | 9.49561
 | Storey 1 | 0.018 | 0.00025447 | 6.86121
 | Storey 1 | 0.018 | 0.00025447 | 9.55465
 | Storey 1 | 0.018 | 0.00025447 | 7.99561
 | Storey 1 | 0.012 | 0.0001131 | 6.80121
 | Storey 1 | 0.014 | 0.00015394 | 1.66268
2 x  | Storey 1 | 0.014 | 0.00015394 | 2
 | Storey 1 | 0.016 | 0.00020106 | 2.49561
 | Storey 1 | 0.016 | 0.00020106 | 11.5214
 | Storey 1 | 0.016 | 0.00020106 | 7.99561
 | Storey 1 | 0.012 | 0.0001131 | 3.70122
 | Storey 1 | 0.012 | 0.0001131 | 3.66121
 | Storey 1 | 0.012 | 0.0001131 | 3.56121
 | Storey 1 | 0.012 | 0.0001131 | 3.38121
 | Storey 1 | 0.016 | 0.00020106 | 3.40122
 | Storey 1 | 0.016 | 0.00020106 | 4.91122
2 x  | Storey 1 | 0.016 | 0.00020106 | 8.3825
2 x  | Storey 1 | 0.016 | 0.00020106 | 7.49561
2 x  | Storey 1 | 0.016 | 0.00020106 | 3
4 x  | Storey 1 | 0.016 | 0.00020106 | 2.79121
4 x  | Storey 1 | 0.012 | 0.0001131 | 2.63121
 | Storey 1 | 0.016 | 0.00020106 | 10.1607
 | Storey 1 | 0.016 | 0.00020106 | 10.1606
 | Storey 1 | 0.012 | 0.0001131 | 3.64621
 | Storey 1 | 0.012 | 0.0001131 | 3.53441
 | Storey 1 | 0.012 | 0.0001131 | 3.51718
2 x  | Storey 1 | 0.016 | 0.00020106 | 10.158
 | Storey 1 | 0.012 | 0.0001131 | 3.51272
 | Storey 1 | 0.012 | 0.0001131 | 3.53222
 | Storey 1 | 0.012 | 0.0001131 | 3.64515
 | Storey 1 | 0.008 | 0.000050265 | 0.986829
 | Storey 1 | 0.016 | 0.00020106 | 3.62988
2 x  | Storey 1 | 0.016 | 0.00020106 | 3.64834
2 x  | Storey 1 | 0.018 | 0.00025447 | 10.0934
2 x  | Storey 1 | 0.014 | 0.00015394 | 10.0934
 | Storey 1 | 0.016 | 0.00020106 | 8.41509
 | Storey 1 | 0.016 | 0.00020106 | 8.41501
 | Storey 1 | 0.018 | 0.00025447 | 5.19254
 | Storey 1 | 0.014 | 0.00015394 | 1.99783
 | Storey 1 | 0.014 | 0.00015394 | 1.99782
2 x  | Storey 1 | 0.012 | 0.0001131 | 9.35591
 | Storey 1 | 0.016 | 0.00020106 | 5.55674
 | Storey 1 | 0.014 | 0.00015394 | 5.49118
 | Storey 1 | 0.014 | 0.00015394 | 3.34481
 | Storey 1 | 0.014 | 0.00015394 | 2.33303
 | Storey 1 | 0.014 | 0.00015394 | 1.65213
 | Storey 1 | 0.016 | 0.00020106 | 0.993265
 | Storey 1 | 0.016 | 0.00020106 | 0.992515
 | Storey 1 | 0.016 | 0.00020106 | 3.87711
 | Storey 1 | 0.016 | 0.00020106 | 3.4781
 | Storey 1 | 0.016 | 0.00020106 | 3.47813
2 x  | Storey 1 | 0.016 | 0.00020106 | 1.72642
 | Storey 1 | 0.016 | 0.00020106 | 1.00183
 | Storey 1 | 0.016 | 0.00020106 | 1.00109
 | Storey 1 | 0.012 | 0.0001131 | 2.13725
 | Storey 1 | 0.012 | 0.0001131 | 3.15576
 | Storey 1 | 0.012 | 0.0001131 | 3.15671
3 x  | Storey 1 | 0.006 | 0.000028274 | 1.4918
2 x  | Storey 1 | 0.016 | 0.00020106 | 5.09853
2 x  | Storey 1 | 0.016 | 0.00020106 | 5.09866
2 x  | Storey 1 | 0.012 | 0.0001131 | 4.60911
 | Storey 1 | 0.016 | 0.00020106 | 7.20525
 | Storey 1 | 0.014 | 0.00015394 | 7.07477
2 x  | Storey 1 | 0.014 | 0.00015394 | 3.34953
 | Storey 1 | 0.014 | 0.00015394 | 3.24511
 | Storey 1 | 0.016 | 0.00020106 | 3.87253
 | Storey 1 | 0.016 | 0.00020106 | 3.87122
2 x  | Storey 1 | 0.014 | 0.00015394 | 2.32783
2 x  | Storey 1 | 0.016 | 0.00020106 | 3.8667
 | Storey 1 | 0.016 | 0.00020106 | 3.48095
 | Storey 1 | 0.016 | 0.00020106 | 3.48104
 | Storey 1 | 0.016 | 0.00020106 | 3.37702
 | Storey 1 | 0.016 | 0.00020106 | 3.37684
 | Storey 1 | 0.016 | 0.00020106 | 3.87846
 | Storey 1 | 0.016 | 0.00020106 | 3.87714
2 x  | Storey 1 | 0.012 | 0.0001131 | 4.58304
2 x  | Storey 1 | 0.012 | 0.0001131 | 2.38428
 | Storey 1 | 0.012 | 0.0001131 | 3.08571
 | Storey 1 | 0.012 | 0.0001131 | 3.08661
 | Storey 1 | 0.012 | 0.0001131 | 4.57937
 | Storey 1 | 0.016 | 0.00020106 | 5.64359
 | Storey 1 | 0.016 | 0.00020106 | 4.00717
 | Storey 1 | 0.016 | 0.00020106 | 5.43237
 | Storey 1 | 0.016 | 0.00020106 | 5.43208
 | Storey 1 | 0.016 | 0.00020106 | 4.29567
 | Storey 1 | 0.016 | 0.00020106 | 7.24561
 | Storey 1 | 0.016 | 0.00020106 | 4.04365
 | Storey 1 | 0.016 | 0.00020106 | 5.43831
 | Storey 1 | 0.016 | 0.00020106 | 5.43803
 | Storey 1 | 0.012 | 0.0001131 | 6.21035
2 x  | Storey 1 | 0.012 | 0.0001131 | 3.55503
 | Storey 1 | 0.012 | 0.0001131 | 6.20481
 | Storey 1 | 0.008 | 0.000050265 | 0.986831
 | Storey 1 | 0.016 | 0.00020106 | 3.62989
 | Storey 1 | 0.016 | 0.00020106 | 7.20524
 | Storey 1 | 0.014 | 0.00015394 | 7.075
 | Storey 1 | 0.014 | 0.00015394 | 3.24535
 | Storey 1 | 0.016 | 0.00020106 | 3.87262
 | Storey 1 | 0.016 | 0.00020106 | 3.87124
 | Storey 1 | 0.016 | 0.00020106 | 3.47895
 | Storey 1 | 0.016 | 0.00020106 | 3.47892
 | Storey 1 | 0.016 | 0.00020106 | 3.37058
 | Storey 1 | 0.016 | 0.00020106 | 3.36925
 | Storey 1 | 0.016 | 0.00020106 | 3.87848
 | Storey 1 | 0.016 | 0.00020106 | 3.87712
 | Storey 1 | 0.012 | 0.0001131 | 3.14535
 | Storey 1 | 0.012 | 0.0001131 | 3.14629
 | Storey 1 | 0.012 | 0.0001131 | 4.57863
2 x  | Storey 1 | 0.016 | 0.00020106 | 10.4012
2 x  | Storey 1 | 0.016 | 0.00020106 | 2.42122
 | Storey 1 | 0.016 | 0.00020106 | 10.2612
 | Storey 1 | 0.018 | 0.00025447 | 10.2612
2 x  | Storey 1 | 0.016 | 0.00020106 | 6.45121
 | Storey 1 | 0.016 | 0.00020106 | 6.80121
17 x  | Storey 0 | 0.008 | 0.000050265 | 1.8868
 | Storey 0 | 0.016 | 0.00020106 | 4.13619
 | Storey 0 | 0.016 | 0.00020106 | 4.00663
 | Storey 0 | 0.016 | 0.00020106 | 3.89437
 | Storey 0 | 0.016 | 0.00020106 | 3.83663
 | Storey 0 | 0.016 | 0.00020106 | 2.48912
 | Storey 0 | 0.016 | 0.00020106 | 2.52392
 | Storey 0 | 0.016 | 0.00020106 | 6.83663
 | Storey 0 | 0.016 | 0.00020106 | 5.52664
 | Storey 0 | 0.016 | 0.00020106 | 2.44392
 | Storey 0 | 0.016 | 0.00020106 | 2.39392
 | Storey 0 | 0.016 | 0.00020106 | 3.99163
2 x  | Storey 0 | 0.016 | 0.00020106 | 2.23142
 | Storey 0 | 0.016 | 0.00020106 | 4.17413
 | Storey 0 | 0.016 | 0.00020106 | 3.75663
 | Storey 0 | 0.016 | 0.00020106 | 3.38163
 | Storey 0 | 0.016 | 0.00020106 | 3.00642
 | Storey 0 | 0.016 | 0.00020106 | 2.95642
 | Storey 0 | 0.008 | 0.000050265 | 3.28679
 | Storey 0 | 0.016 | 0.00020106 | 4.20663
 | Storey 0 | 0.016 | 0.00020106 | 3.94913
 | Storey 0 | 0.016 | 0.00020106 | 3.76913
 | Storey 0 | 0.016 | 0.00020106 | 2.61892
 | Storey 0 | 0.016 | 0.00020106 | 2.56892
2 x  | Storey 0 | 0.016 | 0.00020106 | 4.81913
2 x  | Storey 0 | 0.016 | 0.00020106 | 4.31913
2 x  | Storey 0 | 0.016 | 0.00020106 | 5.07413
 | Storey 0 | 0.016 | 0.00020106 | 3.81708
2 x  | Storey 0 | 0.016 | 0.00020106 | 4.16892
2 x  | Storey 0 | 0.016 | 0.00020106 | 1.91187
2 x  | Storey 0 | 0.016 | 0.00020106 | 2.07142
2 x  | Storey 0 | 0.016 | 0.00020106 | 1.99062
 | Storey 0 | 0.016 | 0.00020106 | 2.60663
 | Storey 0 | 0.016 | 0.00020106 | 4.98163
 | Storey 0 | 0.016 | 0.00020106 | 3.34663
 | Storey 0 | 0.016 | 0.00020106 | 4.27163
 | Storey 0 | 0.016 | 0.00020106 | 4.25642
 | Storey 0 | 0.016 | 0.00020106 | 2.45642
 | Storey 0 | 0.016 | 0.00020106 | 2.47642
 | Storey 0 | 0.016 | 0.00020106 | 2.11187
2 x  | Storey 0 | 0.016 | 0.00020106 | 1.93407
2 x  | Storey 0 | 0.016 | 0.00020106 | 2.58413
2 x  | Storey 0 | 0.016 | 0.00020106 | 2.05907
2 x  | Storey 0 | 0.016 | 0.00020106 | 1.73142
2 x  | Storey 0 | 0.016 | 0.00020106 | 1.59892
2 x  | Storey 0 | 0.016 | 0.00020106 | 3.03191
2 x  | Storey 0 | 0.016 | 0.00020106 | 3.24447
2 x  | Storey 0 | 0.016 | 0.00020106 | 2.61643
2 x  | Storey 0 | 0.016 | 0.00020106 | 2.71643
4 x  | Storey 0 | 0.016 | 0.00020106 | 2.43642
2 x  | Storey 0 | 0.014 | 0.00015394 | 2.90094
 | Storey 0 | 0.014 | 0.00015394 | 1.89877
 | Storey 0 | 0.014 | 0.00015394 | 1.78579
 | Storey 0 | 0.016 | 0.00020106 | 3.93081
 | Storey 0 | 0.016 | 0.00020106 | 3.81782
 | Storey 0 | 0.02 | 0.00031416 | 2.26822
 | Storey 0 | 0.014 | 0.00015394 | 2.26822
 | Storey 0 | 0.016 | 0.00020106 | 2.00532
 | Storey 0 | 0.014 | 0.00015394 | 2.00532
 | Storey 0 | 0.008 | 0.000050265 | 1.08682
 | Storey 0 | 0.016 | 0.00020106 | 3.48121

# IfcSlab: 1 COP DEL LOGGIATO IN LEGNO E MEZZANE (93)
Type - PredefinedType: FLOOR; Material: Concrete
Description: 1 COP DEL LOGGIATO IN LEGNO E MEZZANE - Altezza solaio 0.240000 - Spessore cappa 0.040000 -
Pset_SlabCommon - LoadBearing: yes
BaseQuantities - ?: 0.24 m
Name | In | BaseQuantities, ? (m2) | BaseQuantities, ? (m3)
400 | Storey 0 | -0.175 | -0.042
401 | Storey 0 | -0.215 | -0.0516
402 | Storey 0 | -0.175 | -0.042
403 | Storey 0 | -0.175 | -0.042
122 | Storey 0 | -0.8225 | -0.1974
123 | Storey 0 | -0.8225 | -0.1974
404 | Storey 0 | -0.175 | -0.042
405 | Storey 0 | -0.175 | -0.042
406 | Storey 0 | -0.175 | -0.042
407 | Storey 0 | -0.175 | -0.042
408 | Storey 0 | -0.2 | -0.048
124 | Storey 0 | -0.8225 | -0.1974
125 | Storey 0 | -0.8225 | -0.1974
126 | Storey 0 | -1.0105 | -0.24252
127 | Storey 0 | -0.8225 | -0.1974
409 | Storey 0 | -0.175 | -0.042
128 | Storey 0 | -0.834249 | -0.20022
129 | Storey 0 | -0.822501 | -0.1974
130 | Storey 0 | -0.8225 | -0.1974
131 | Storey 0 | -0.8225 | -0.1974
132 | Storey 0 | -0.658 | -0.15792
225 | Storey 0 | 1.029 | 0.24696
226 | Storey 0 | 1.099 | 0.26376
227 | Storey 0 | 1.05 | 0.252
228 | Storey 0 | 1.225 | 0.294
229 | Storey 0 | 0.770001 | 0.1848
230 | Storey 0 | 1.092 | 0.26208
231 | Storey 0 | 0.490001 | 0.1176
232 | Storey 0 | 3.983 | 0.95592
233 | Storey 0 | 1.092 | 0.26208
234 | Storey 0 | 0.77 | 0.1848
235 | Storey 0 | 1.2285 | 0.29484
236 | Storey 0 | 1.0465 | 0.25116
237 | Storey 0 | 1.008 | 0.24192
238 | Storey 0 | 1.12 | 0.2688
239 | Storey 0 | 0.49 | 0.1176
240 | Storey 0 | 1.134 | 0.27216
241 | Storey 0 | 3.598 | 0.86352
243 | Storey 0 | 1.078 | 0.25872
244 | Storey 0 | 1.155 | 0.2772
245 | Storey 0 | 0.49 | 0.1176
246 | Storey 0 | 1.12 | 0.2688
247 | Storey 0 | 1.008 | 0.24192
248 | Storey 0 | 1.043 | 0.25032
249 | Storey 0 | 1.232 | 0.29568
250 | Storey 0 | 0.77 | 0.1848
251 | Storey 0 | 1.092 | 0.26208
410 | Storey 0 | 0.159999 | 0.0383997
411 | Storey 0 | 0.175 | 0.042
412 | Storey 0 | 0.175 | 0.042
413 | Storey 0 | 0.175 | 0.042
414 | Storey 0 | 0.349999 | 0.0839999
415 | Storey 0 | 0.175 | 0.0419999
416 | Storey 0 | 0.175 | 0.042
161 | Storey 0 | 0.751995 | 0.180479
417 | Storey 0 | 0.215 | 0.0516
162 | Storey 0 | 0.822501 | 0.1974
163 | Storey 0 | 0.822501 | 0.1974
164 | Storey 0 | -0.822501 | -0.1974
165 | Storey 0 | -0.810748 | -0.19458
166 | Storey 0 | 0.822499 | 0.1974
167 | Storey 0 | 0.822501 | 0.1974
418 | Storey 0 | 0.2 | 0.0480001
277 | Storey 0 | -1.029 | -0.24696
278 | Storey 0 | -1.099 | -0.26376
279 | Storey 0 | -1.05 | -0.252
280 | Storey 0 | -1.225 | -0.294
281 | Storey 0 | -0.770001 | -0.1848
282 | Storey 0 | -1.092 | -0.26208
283 | Storey 0 | -0.49 | -0.1176
284 | Storey 0 | -3.98299 | -0.955918
285 | Storey 0 | -1.092 | -0.26208
286 | Storey 0 | -0.77 | -0.1848
287 | Storey 0 | -1.2285 | -0.29484
288 | Storey 0 | -1.0465 | -0.25116
289 | Storey 0 | -1.008 | -0.24192
290 | Storey 0 | -1.12 | -0.2688
291 | Storey 0 | -0.489999 | -0.1176
292 | Storey 0 | -1.134 | -0.27216
293 | Storey 0 | -3.59799 | -0.863519
295 | Storey 0 | -1.078 | -0.25872
296 | Storey 0 | -1.155 | -0.2772
297 | Storey 0 | -0.489999 | -0.1176
298 | Storey 0 | -1.112 | -0.26688
299 | Storey 0 | -1.0008 | -0.240192
300 | Storey 0 | -1.043 | -0.25032
301 | Storey 0 | -1.232 | -0.29568
302 | Storey 0 | -0.77 | -0.1848
303 | Storey 0 | -1.092 | -0.26208
171 | Storey 0 | 1.0105 | 0.24252
172 | Storey 0 | 0.658002 | 0.15792
137 | Storey 1 | -3.388 | -0.81312
173 | Storey 1 | 3.388 | 0.81312

# IfcSlab: 2 SOLAIO LEGNO ABITAZIONE INTERPIANO (40)
In: Storey 1
Type - PredefinedType: FLOOR; Material: Concrete
Description: 2 SOLAIO LEGNO ABITAZIONE INTERPIANO - Altezza solaio 0.240000 - Spessore cappa 0.040000 -
Pset_SlabCommon - LoadBearing: yes
BaseQuantities - ?: 0.24 m
Name | BaseQuantities, ? (m2) | BaseQuantities, ? (m3)
100 | -4.7531 | -1.14074
101 | -5.6144 | -1.34746
102 | -3.509 | -0.84216
103 | -4.9764 | -1.19434
104 | -8.224 | -1.97376
105 | -7.4016 | -1.77638
106 | -7.205 | -1.7292
107 | -5.72 | -1.3728
108 | -3.575 | -0.858
109 | -5.07 | -1.2168
110 | -2.4867 | -0.596808
111 | -2.4381 | -0.585144
112 | -2.025 | -0.486
113 | -2.18 | -0.5232
114 | -1.199 | -0.28776
115 | 1.8954 | 0.454896
133 | -2.2176 | -0.532224
134 | -2.464 | -0.59136
135 | -2.64 | -0.6336
136 | -2.376 | -0.57024
138 | 4.7531 | 1.14074
139 | 5.6144 | 1.34746
140 | 3.509 | 0.84216
141 | 4.9764 | 1.19434
142 | 8.224 | 1.97376
143 | 7.4016 | 1.77638
144 | 7.205 | 1.7292
145 | 5.72 | 1.3728
146 | 3.575 | 0.858
147 | 5.07 | 1.2168
148 | 2.4867 | 0.596808
149 | 2.4381 | 0.585144
150 | 2.025 | 0.486
151 | 2.18 | 0.5232
152 | 1.199 | 0.28776
153 | -1.8954 | -0.454896
160 | 2.64 | 0.6336
168 | 2.376 | 0.57024
169 | 2.2176 | 0.532224
170 | 2.464 | 0.59136

# IfcSlab: 3 COPERTURA DEL fabbricato perline (52)
In: Storey 0
Type - PredefinedType: FLOOR; Material: Concrete
Description: 3 COPERTURA DEL fabbricato perline - Altezza solaio 0.240000 - Spessore cappa 0.040000 -
Pset_SlabCommon - LoadBearing: yes
BaseQuantities - ?: 0.24 m
Name | BaseQuantities, ? (m2) | BaseQuantities, ? (m3)
200 | -8.3643 | -2.00743
201 | -8.9333 | -2.14399
202 | -8.535 | -2.0484
203 | -9.9575 | -2.3898
204 | -6.259 | -1.50216
205 | -8.8764 | -2.13034
206 | -4.7531 | -1.14074
207 | -5.6144 | -1.34746
208 | -3.509 | -0.84216
209 | -4.9764 | -1.19434
210 | -7.4016 | -1.77638
211 | -7.205 | -1.7292
212 | -5.72 | -1.3728
213 | -3.575 | -0.858
214 | -5.07 | -1.2168
215 | -2.3328 | -0.559872
216 | -2.592 | -0.62208
217 | -2.025 | -0.486
218 | -3.861 | -0.92664
219 | -5.4756 | -1.31414
220 | 7.02 | 1.6848
221 | -2.464 | -0.59136
222 | -2.64 | -0.6336
223 | -2.376 | -0.57024
224 | -2.2176 | -0.532224
242 | -8.224 | -1.97376
252 | 8.36431 | 2.00743
253 | 8.9333 | 2.14399
254 | 8.535 | 2.0484
255 | 9.9575 | 2.3898
256 | 6.259 | 1.50216
257 | 8.8764 | 2.13034
258 | 4.7531 | 1.14074
259 | 5.6144 | 1.34746
260 | 3.509 | 0.84216
261 | 4.9764 | 1.19434
262 | 7.4016 | 1.77638
263 | 7.205 | 1.7292
264 | 5.72 | 1.3728
265 | 3.575 | 0.858
266 | 5.07 | 1.2168
267 | 2.3328 | 0.559872
268 | 2.592 | 0.62208
269 | 2.025 | 0.486
270 | 3.861 | 0.92664
271 | 5.4756 | 1.31414
272 | -7.02 | -1.6848
273 | 2.464 | 0.59136
274 | 2.648 | 0.63552
275 | 2.3832 | 0.571968
276 | 2.2176 | 0.532224
294 | 8.224 | 1.97376

# IfcSlab: 4 SOLAIO LEGNO INTERPIANO GARAGE TRAMEZZI --- (12)
In: Storey 1
Type - PredefinedType: FLOOR; Material: Concrete
Description: 4 SOLAIO LEGNO INTERPIANO GARAGE TRAMEZZI --- - Altezza solaio 0.240000 - Spessore cappa 0.040000 -
Pset_SlabCommon - LoadBearing: yes
BaseQuantities - ?: 0.24 m
Name | BaseQuantities, ? (m2) | BaseQuantities, ? (m3)
116 | -8.3643 | -2.00743
117 | -8.9333 | -2.14399
118 | -8.535 | -2.0484
119 | -9.9575 | -2.3898
120 | -6.259 | -1.50216
121 | -8.8764 | -2.13034
154 | 8.36431 | 2.00743
155 | 8.9333 | 2.14399
156 | 8.535 | 2.0484
157 | 9.9575 | 2.3898
158 | 6.259 | 1.50216
159 | 8.8764 | 2.13034

# IfcWall (75)
Material: TAMPONAMENTI SPESSORE 41 CM. 300 kg/mq. detratto fori
Pset_WallCommon - LoadBearing: yes
Name | In
127 | Storey 0
126 | Storey 0
125 | Storey 0
124 | Storey 0
102 | Storey 0
103 | Storey 0
118 | Storey 0
119 | Storey 0
120 | Storey 0
128 | Storey 0
129 | Storey 0
130 | Storey 0
131 | Storey 0
231 | Storey 0
132 | Storey 0
112 | Storey 0
113 | Storey 0
114 | Storey 0
136 | Storey 0
135 | Storey 0
134 | Storey 0
133 | Storey 0
108 | Storey 0
105 | Storey 0
123 | Storey 0
122 | Storey 0
121 | Storey 0
117 | Storey 0
116 | Storey 0
115 | Storey 0
224 | Storey 1
225 | Storey 1
226 | Storey 1
227 | Storey 1
209 | Storey 1
302 | Storey 1
101 | Storey 1
220 | Storey 1
218 | Storey 1
229 | Storey 1
228 | Storey 1
230 | Storey 1
331 | Storey 1
232 | Storey 1
214 | Storey 1
213 | Storey 1
212 | Storey 1
312 | Storey 1
313 | Storey 1
314 | Storey 1
109 | Storey 1
327 | Storey 1
402 | Storey 1
203 | Storey 1
202 | Storey 1
233 | Storey 1
234 | Storey 1
235 | Storey 1
236 | Storey 1
110 | Storey 1
106 | Storey 1
208 | Storey 1
221 | Storey 1
222 | Storey 1
215 | Storey 1
216 | Storey 1
217 | Storey 1
317 | Storey 1
316 | Storey 1
315 | Storey 1
111 | Storey 1
332 | Storey 1
205 | Storey 1
104 | Storey 1
107 | Storey 1

# IfcWall: 2 SOLETTA SCALA (6)
In: Storey 0
Type - PredefinedType: STANDARD
Description: 2 SOLETTA SCALA; Material: Calcestruzzo classe C28/35 0.15 m
Pset_WallCommon - LoadBearing: yes
Name | ? (m3)
2 x  | 3.40614
 | 4.05553
 | 4.05552
2 x  | 0.4719

# IfcReinforcingBarType, no part of this type: type
PredefinedType: MAIN; NominalDiameter: 0.016 m; CrossSectionArea: 0.00020106 m2; BarLength: 1.39193 m; Material: Steel

# IfcReinforcingBarType, no part of this type: type
PredefinedType: MAIN; NominalDiameter: 0.016 m; CrossSectionArea: 0.00020106 m2; BarLength: 2.88943 m; Material: Steel

# IfcReinforcingBarType, no part of this type: type
PredefinedType: LIGATURE; NominalDiameter: 0.008 m; CrossSectionArea: 0.000050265 m2; BarLength: 1.5788 m; Material: Steel

# IfcReinforcingBarType, no part of this type: type
PredefinedType: MAIN; NominalDiameter: 0.016 m; CrossSectionArea: 0.00020106 m2; BarLength: 1.39193 m; Material: Steel

# IfcReinforcingBarType, no part of this type: type
PredefinedType: MAIN; NominalDiameter: 0.016 m; CrossSectionArea: 0.00020106 m2; BarLength: 2.88943 m; Material: Steel

# IfcReinforcingBarType, no part of this type: type
PredefinedType: LIGATURE; NominalDiameter: 0.008 m; CrossSectionArea: 0.000050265 m2; BarLength: 1.5788 m; Material: Steel

# IfcReinforcingBarType, no part of this type: type
PredefinedType: MAIN; NominalDiameter: 0.016 m; CrossSectionArea: 0.00020106 m2; BarLength: 1.39193 m; Material: Steel

# IfcReinforcingBarType, no part of this type: type
PredefinedType: MAIN; NominalDiameter: 0.016 m; CrossSectionArea: 0.00020106 m2; BarLength: 2.88943 m; Material: Steel

# IfcReinforcingBarType, no part of this type: type
PredefinedType: LIGATURE; NominalDiameter: 0.008 m; CrossSectionArea: 0.000050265 m2; BarLength: 1.5788 m; Material: Steel

# IfcReinforcingBarType, no part of this type: type
PredefinedType: MAIN; NominalDiameter: 0.016 m; CrossSectionArea: 0.00020106 m2; BarLength: 1.39193 m; Material: Steel

# IfcReinforcingBarType, no part of this type: type
PredefinedType: MAIN; NominalDiameter: 0.016 m; CrossSectionArea: 0.00020106 m2; BarLength: 2.88943 m; Material: Steel

# IfcReinforcingBarType, no part of this type: type
PredefinedType: LIGATURE; NominalDiameter: 0.008 m; CrossSectionArea: 0.000050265 m2; BarLength: 1.5788 m; Material: Steel

# IfcReinforcingBarType, no part of this type: type
PredefinedType: MAIN; NominalDiameter: 0.016 m; CrossSectionArea: 0.00020106 m2; BarLength: 1.39193 m; Material: Steel

# IfcReinforcingBarType, no part of this type: type
PredefinedType: MAIN; NominalDiameter: 0.016 m; CrossSectionArea: 0.00020106 m2; BarLength: 3.84 m; Material: Steel

# IfcReinforcingBarType, no part of this type: type
PredefinedType: MAIN; NominalDiameter: 0.016 m; CrossSectionArea: 0.00020106 m2; BarLength: 2.88943 m; Material: Steel

# IfcReinforcingBarType, no part of this type: type
PredefinedType: LIGATURE; NominalDiameter: 0.008 m; CrossSectionArea: 0.000050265 m2; BarLength: 1.5788 m; Material: Steel

# IfcReinforcingBarType, no part of this type: type
PredefinedType: LIGATURE; NominalDiameter: 0.008 m; CrossSectionArea: 0.000050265 m2; BarLength: 1.2086 m; Material: Steel

# IfcReinforcingBarType, no part of this type: type
PredefinedType: MAIN; NominalDiameter: 0.018 m; CrossSectionArea: 0.00025447 m2; BarLength: 1.31973 m; Material: Steel

# IfcReinforcingBarType, no part of this type: type
PredefinedType: MAIN; NominalDiameter: 0.016 m; CrossSectionArea: 0.00020106 m2; BarLength: 1.32193 m; Material: Steel

# IfcReinforcingBarType, no part of this type: type
PredefinedType: MAIN; NominalDiameter: 0.018 m; CrossSectionArea: 0.00025447 m2; BarLength: 3.92 m; Material: Steel

# IfcReinforcingBarType, no part of this type: type
PredefinedType: MAIN; NominalDiameter: 0.016 m; CrossSectionArea: 0.00020106 m2; BarLength: 3.92 m; Material: Steel

# IfcReinforcingBarType, no part of this type: type
PredefinedType: MAIN; NominalDiameter: 0.018 m; CrossSectionArea: 0.00025447 m2; BarLength: 3.61723 m; Material: Steel

# IfcReinforcingBarType, no part of this type: type
PredefinedType: MAIN; NominalDiameter: 0.016 m; CrossSectionArea: 0.00020106 m2; BarLength: 3.61943 m; Material: Steel

# IfcReinforcingBarType, no part of this type: type
PredefinedType: LIGATURE; NominalDiameter: 0.008 m; CrossSectionArea: 0.000050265 m2; BarLength: 1.37881 m; Material: Steel

# IfcReinforcingBarType, no part of this type: type
PredefinedType: LIGATURE; NominalDiameter: 0.008 m; CrossSectionArea: 0.000050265 m2; BarLength: 0.428429 m; Material: Steel

# IfcReinforcingBarType, no part of this type: type
PredefinedType: MAIN; NominalDiameter: 0.018 m; CrossSectionArea: 0.00025447 m2; BarLength: 1.31973 m; Material: Steel

# IfcReinforcingBarType, no part of this type: type
PredefinedType: MAIN; NominalDiameter: 0.016 m; CrossSectionArea: 0.00020106 m2; BarLength: 1.32193 m; Material: Steel

# IfcReinforcingBarType, no part of this type: type
PredefinedType: MAIN; NominalDiameter: 0.018 m; CrossSectionArea: 0.00025447 m2; BarLength: 3.92 m; Material: Steel

# IfcReinforcingBarType, no part of this type: type
PredefinedType: MAIN; NominalDiameter: 0.016 m; CrossSectionArea: 0.00020106 m2; BarLength: 3.92 m; Material: Steel

# IfcReinforcingBarType, no part of this type: type
PredefinedType: MAIN; NominalDiameter: 0.018 m; CrossSectionArea: 0.00025447 m2; BarLength: 4.43723 m; Material: Steel

# IfcReinforcingBarType, no part of this type: type
PredefinedType: MAIN; NominalDiameter: 0.016 m; CrossSectionArea: 0.00020106 m2; BarLength: 4.43943 m; Material: Steel

# IfcReinforcingBarType, no part of this type: type
PredefinedType: LIGATURE; NominalDiameter: 0.008 m; CrossSectionArea: 0.000050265 m2; BarLength: 1.7788 m; Material: Steel

# IfcReinforcingBarType, no part of this type: type
PredefinedType: LIGATURE; NominalDiameter: 0.008 m; CrossSectionArea: 0.000050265 m2; BarLength: 0.428429 m; Material: Steel

# IfcReinforcingBarType, no part of this type: type
PredefinedType: LIGATURE; NominalDiameter: 0.008 m; CrossSectionArea: 0.000050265 m2; BarLength: 1.02152 m; Material: Steel

# IfcReinforcingBarType, no part of this type: type
PredefinedType: MAIN; NominalDiameter: 0.02 m; CrossSectionArea: 0.00031416 m2; BarLength: 1.39754 m; Material: Steel

# IfcReinforcingBarType, no part of this type: type
PredefinedType: MAIN; NominalDiameter: 0.016 m; CrossSectionArea: 0.00020106 m2; BarLength: 1.40193 m; Material: Steel

# IfcReinforcingBarType, no part of this type: type
PredefinedType: MAIN; NominalDiameter: 0.02 m; CrossSectionArea: 0.00031416 m2; BarLength: 4 m; Material: Steel

# IfcReinforcingBarType, no part of this type: type
PredefinedType: MAIN; NominalDiameter: 0.016 m; CrossSectionArea: 0.00020106 m2; BarLength: 4 m; Material: Steel

# IfcReinforcingBarType, no part of this type: type
PredefinedType: MAIN; NominalDiameter: 0.02 m; CrossSectionArea: 0.00031416 m2; BarLength: 5.33504 m; Material: Steel

# IfcReinforcingBarType, no part of this type: type
PredefinedType: MAIN; NominalDiameter: 0.016 m; CrossSectionArea: 0.00020106 m2; BarLength: 5.33943 m; Material: Steel

# IfcReinforcingBarType, no part of this type: type
PredefinedType: LIGATURE; NominalDiameter: 0.008 m; CrossSectionArea: 0.000050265 m2; BarLength: 2.27879 m; Material: Steel

# IfcReinforcingBarType, no part of this type: type
PredefinedType: LIGATURE; NominalDiameter: 0.008 m; CrossSectionArea: 0.000050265 m2; BarLength: 1.45481 m; Material: Steel

# IfcReinforcingBarType, no part of this type: type
PredefinedType: LIGATURE; NominalDiameter: 0.008 m; CrossSectionArea: 0.000050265 m2; BarLength: 0.428428 m; Material: Steel

# IfcReinforcingBarType, no part of this type: type
PredefinedType: MAIN; NominalDiameter: 0.018 m; CrossSectionArea: 0.00025447 m2; BarLength: 1.31973 m; Material: Steel

# IfcReinforcingBarType, no part of this type: type
PredefinedType: MAIN; NominalDiameter: 0.016 m; CrossSectionArea: 0.00020106 m2; BarLength: 1.32193 m; Material: Steel

# IfcReinforcingBarType, no part of this type: type
PredefinedType: MAIN; NominalDiameter: 0.018 m; CrossSectionArea: 0.00025447 m2; BarLength: 3.92 m; Material: Steel

# IfcReinforcingBarType, no part of this type: type
PredefinedType: MAIN; NominalDiameter: 0.016 m; CrossSectionArea: 0.00020106 m2; BarLength: 3.92 m; Material: Steel

# IfcReinforcingBarType, no part of this type: type
PredefinedType: MAIN; NominalDiameter: 0.018 m; CrossSectionArea: 0.00025447 m2; BarLength: 4.43723 m; Material: Steel

# IfcReinforcingBarType, no part of this type: type
PredefinedType: MAIN; NominalDiameter: 0.016 m; CrossSectionArea: 0.00020106 m2; BarLength: 4.43943 m; Material: Steel

# IfcReinforcingBarType, no part of this type: type
PredefinedType: LIGATURE; NominalDiameter: 0.008 m; CrossSectionArea: 0.000050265 m2; BarLength: 1.7788 m; Material: Steel

# IfcReinforcingBarType, no part of this type: type
PredefinedType: LIGATURE; NominalDiameter: 0.008 m; CrossSectionArea: 0.000050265 m2; BarLength: 0.428429 m; Material: Steel

# IfcReinforcingBarType, no part of this type: type
PredefinedType: LIGATURE; NominalDiameter: 0.008 m; CrossSectionArea: 0.000050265 m2; BarLength: 1.02149 m; Material: Steel

# IfcReinforcingBarType, no part of this type: type
PredefinedType: MAIN; NominalDiameter: 0.016 m; CrossSectionArea: 0.00020106 m2; BarLength: 1.24193 m; Material: Steel

# IfcReinforcingBarType, no part of this type: type
PredefinedType: MAIN; NominalDiameter: 0.016 m; CrossSectionArea: 0.00020106 m2; BarLength: 3.84 m; Material: Steel

# IfcReinforcingBarType, no part of this type: type
PredefinedType: MAIN; NominalDiameter: 0.016 m; CrossSectionArea: 0.00020106 m2; BarLength: 3.61943 m; Material: Steel

# IfcReinforcingBarType, no part of this type: type
PredefinedType: LIGATURE; NominalDiameter: 0.008 m; CrossSectionArea: 0.000050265 m2; BarLength: 1.37881 m; Material: Steel

# IfcReinforcingBarType, no part of this type: type
PredefinedType: LIGATURE; NominalDiameter: 0.008 m; CrossSectionArea: 0.000050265 m2; BarLength: 0.428429 m; Material: Steel

# IfcReinforcingBarType, no part of this type: type
PredefinedType: MAIN; NominalDiameter: 0.016 m; CrossSectionArea: 0.00020106 m2; BarLength: 1.39193 m; Material: Steel

# IfcReinforcingBarType, no part of this type: type
PredefinedType: MAIN; NominalDiameter: 0.016 m; CrossSectionArea: 0.00020106 m2; BarLength: 3.84 m; Material: Steel

# IfcReinforcingBarType, no part of this type: type
PredefinedType: MAIN; NominalDiameter: 0.016 m; CrossSectionArea: 0.00020106 m2; BarLength: 2.88943 m; Material: Steel

# IfcReinforcingBarType, no part of this type: type
PredefinedType: LIGATURE; NominalDiameter: 0.008 m; CrossSectionArea: 0.000050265 m2; BarLength: 1.5788 m; Material: Steel

# IfcReinforcingBarType, no part of this type: type
PredefinedType: LIGATURE; NominalDiameter: 0.008 m; CrossSectionArea: 0.000050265 m2; BarLength: 1.20881 m; Material: Steel

# IfcReinforcingBarType, no part of this type: type
PredefinedType: MAIN; NominalDiameter: 0.016 m; CrossSectionArea: 0.00020106 m2; BarLength: 1.29193 m; Material: Steel

# IfcReinforcingBarType, no part of this type: type
PredefinedType: MAIN; NominalDiameter: 0.016 m; CrossSectionArea: 0.00020106 m2; BarLength: 3.61943 m; Material: Steel

# IfcReinforcingBarType, no part of this type: type
PredefinedType: LIGATURE; NominalDiameter: 0.008 m; CrossSectionArea: 0.000050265 m2; BarLength: 1.27881 m; Material: Steel

# IfcReinforcingBarType, no part of this type: type
PredefinedType: LIGATURE; NominalDiameter: 0.008 m; CrossSectionArea: 0.000050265 m2; BarLength: 0.428429 m; Material: Steel

# IfcReinforcingBarType, no part of this type: type
PredefinedType: MAIN; NominalDiameter: 0.016 m; CrossSectionArea: 0.00020106 m2; BarLength: 1.29193 m; Material: Steel

# IfcReinforcingBarType, no part of this type: type
PredefinedType: MAIN; NominalDiameter: 0.016 m; CrossSectionArea: 0.00020106 m2; BarLength: 3.61943 m; Material: Steel

# IfcReinforcingBarType, no part of this type: type
PredefinedType: LIGATURE; NominalDiameter: 0.008 m; CrossSectionArea: 0.000050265 m2; BarLength: 1.27881 m; Material: Steel

# IfcReinforcingBarType, no part of this type: type
PredefinedType: LIGATURE; NominalDiameter: 0.008 m; CrossSectionArea: 0.000050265 m2; BarLength: 0.428429 m; Material: Steel

# IfcReinforcingBarType, no part of this type: type
PredefinedType: MAIN; NominalDiameter: 0.018 m; CrossSectionArea: 0.00025447 m2; BarLength: 1.31973 m; Material: Steel

# IfcReinforcingBarType, no part of this type: type
PredefinedType: MAIN; NominalDiameter: 0.016 m; CrossSectionArea: 0.00020106 m2; BarLength: 1.32193 m; Material: Steel

# IfcReinforcingBarType, no part of this type: type
PredefinedType: MAIN; NominalDiameter: 0.018 m; CrossSectionArea: 0.00025447 m2; BarLength: 3.92 m; Material: Steel

# IfcReinforcingBarType, no part of this type: type
PredefinedType: MAIN; NominalDiameter: 0.016 m; CrossSectionArea: 0.00020106 m2; BarLength: 3.92 m; Material: Steel

# IfcReinforcingBarType, no part of this type: type
PredefinedType: MAIN; NominalDiameter: 0.018 m; CrossSectionArea: 0.00025447 m2; BarLength: 2.73723 m; Material: Steel

# IfcReinforcingBarType, no part of this type: type
PredefinedType: MAIN; NominalDiameter: 0.016 m; CrossSectionArea: 0.00020106 m2; BarLength: 2.73943 m; Material: Steel

# IfcReinforcingBarType, no part of this type: type
PredefinedType: LIGATURE; NominalDiameter: 0.008 m; CrossSectionArea: 0.000050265 m2; BarLength: 1.37881 m; Material: Steel

# IfcReinforcingBarType, no part of this type: type
PredefinedType: LIGATURE; NominalDiameter: 0.008 m; CrossSectionArea: 0.000050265 m2; BarLength: 0.428429 m; Material: Steel

# IfcReinforcingBarType, no part of this type: type
PredefinedType: MAIN; NominalDiameter: 0.016 m; CrossSectionArea: 0.00020106 m2; BarLength: 1.29193 m; Material: Steel

# IfcReinforcingBarType, no part of this type: type
PredefinedType: MAIN; NominalDiameter: 0.016 m; CrossSectionArea: 0.00020106 m2; BarLength: 3.84 m; Material: Steel

# IfcReinforcingBarType, no part of this type: type
PredefinedType: MAIN; NominalDiameter: 0.016 m; CrossSectionArea: 0.00020106 m2; BarLength: 5.38943 m; Material: Steel

# IfcReinforcingBarType, no part of this type: type
PredefinedType: LIGATURE; NominalDiameter: 0.008 m; CrossSectionArea: 0.000050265 m2; BarLength: 2.57879 m; Material: Steel

# IfcReinforcingBarType, no part of this type: type
PredefinedType: LIGATURE; NominalDiameter: 0.008 m; CrossSectionArea: 0.000050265 m2; BarLength: 2.1654 m; Material: Steel

# IfcReinforcingBarType, no part of this type: type
PredefinedType: LIGATURE; NominalDiameter: 0.008 m; CrossSectionArea: 0.000050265 m2; BarLength: 0.478429 m; Material: Steel

# IfcReinforcingBarType, no part of this type: type
PredefinedType: LIGATURE; NominalDiameter: 0.008 m; CrossSectionArea: 0.000050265 m2; BarLength: 2.35305 m; Material: Steel

# IfcReinforcingBarType, no part of this type: type
PredefinedType: MAIN; NominalDiameter: 0.018 m; CrossSectionArea: 0.00025447 m2; BarLength: 1.31973 m; Material: Steel

# IfcReinforcingBarType, no part of this type: type
PredefinedType: MAIN; NominalDiameter: 0.016 m; CrossSectionArea: 0.00020106 m2; BarLength: 1.32193 m; Material: Steel

# IfcReinforcingBarType, no part of this type: type
PredefinedType: MAIN; NominalDiameter: 0.018 m; CrossSectionArea: 0.00025447 m2; BarLength: 3.92 m; Material: Steel

# IfcReinforcingBarType, no part of this type: type
PredefinedType: MAIN; NominalDiameter: 0.016 m; CrossSectionArea: 0.00020106 m2; BarLength: 3.92 m; Material: Steel

# IfcReinforcingBarType, no part of this type: type
PredefinedType: MAIN; NominalDiameter: 0.018 m; CrossSectionArea: 0.00025447 m2; BarLength: 2.73723 m; Material: Steel

# IfcReinforcingBarType, no part of this type: type
PredefinedType: MAIN; NominalDiameter: 0.016 m; CrossSectionArea: 0.00020106 m2; BarLength: 2.73943 m; Material: Steel

# IfcReinforcingBarType, no part of this type: type
PredefinedType: LIGATURE; NominalDiameter: 0.008 m; CrossSectionArea: 0.000050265 m2; BarLength: 1.3788 m; Material: Steel

# IfcReinforcingBarType, no part of this type: type
PredefinedType: LIGATURE; NominalDiameter: 0.008 m; CrossSectionArea: 0.000050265 m2; BarLength: 0.42843 m; Material: Steel

# IfcReinforcingBarType, no part of this type: type
PredefinedType: MAIN; NominalDiameter: 0.016 m; CrossSectionArea: 0.00020106 m2; BarLength: 1.24193 m; Material: Steel

# IfcReinforcingBarType, no part of this type: type
PredefinedType: MAIN; NominalDiameter: 0.016 m; CrossSectionArea: 0.00020106 m2; BarLength: 3.84 m; Material: Steel

# IfcReinforcingBarType, no part of this type: type
PredefinedType: MAIN; NominalDiameter: 0.016 m; CrossSectionArea: 0.00020106 m2; BarLength: 4.48943 m; Material: Steel

# IfcReinforcingBarType, no part of this type: type
PredefinedType: LIGATURE; NominalDiameter: 0.008 m; CrossSectionArea: 0.000050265 m2; BarLength: 1.37881 m; Material: Steel

# IfcReinforcingBarType, no part of this type: type
PredefinedType: LIGATURE; NominalDiameter: 0.008 m; CrossSectionArea: 0.000050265 m2; BarLength: 0.428429 m; Material: Steel

# IfcReinforcingBarType, no part of this type: type
PredefinedType: MAIN; NominalDiameter: 0.016 m; CrossSectionArea: 0.00020106 m2; BarLength: 1.24193 m; Material: Steel

# IfcReinforcingBarType, no part of this type: type
PredefinedType: MAIN; NominalDiameter: 0.016 m; CrossSectionArea: 0.00020106 m2; BarLength: 3.84 m; Material: Steel

# IfcReinforcingBarType, no part of this type: type
PredefinedType: MAIN; NominalDiameter: 0.016 m; CrossSectionArea: 0.00020106 m2; BarLength: 4.48943 m; Material: Steel

# IfcReinforcingBarType, no part of this type: type
PredefinedType: LIGATURE; NominalDiameter: 0.008 m; CrossSectionArea: 0.000050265 m2; BarLength: 1.37881 m; Material: Steel

# IfcReinforcingBarType, no part of this type: type
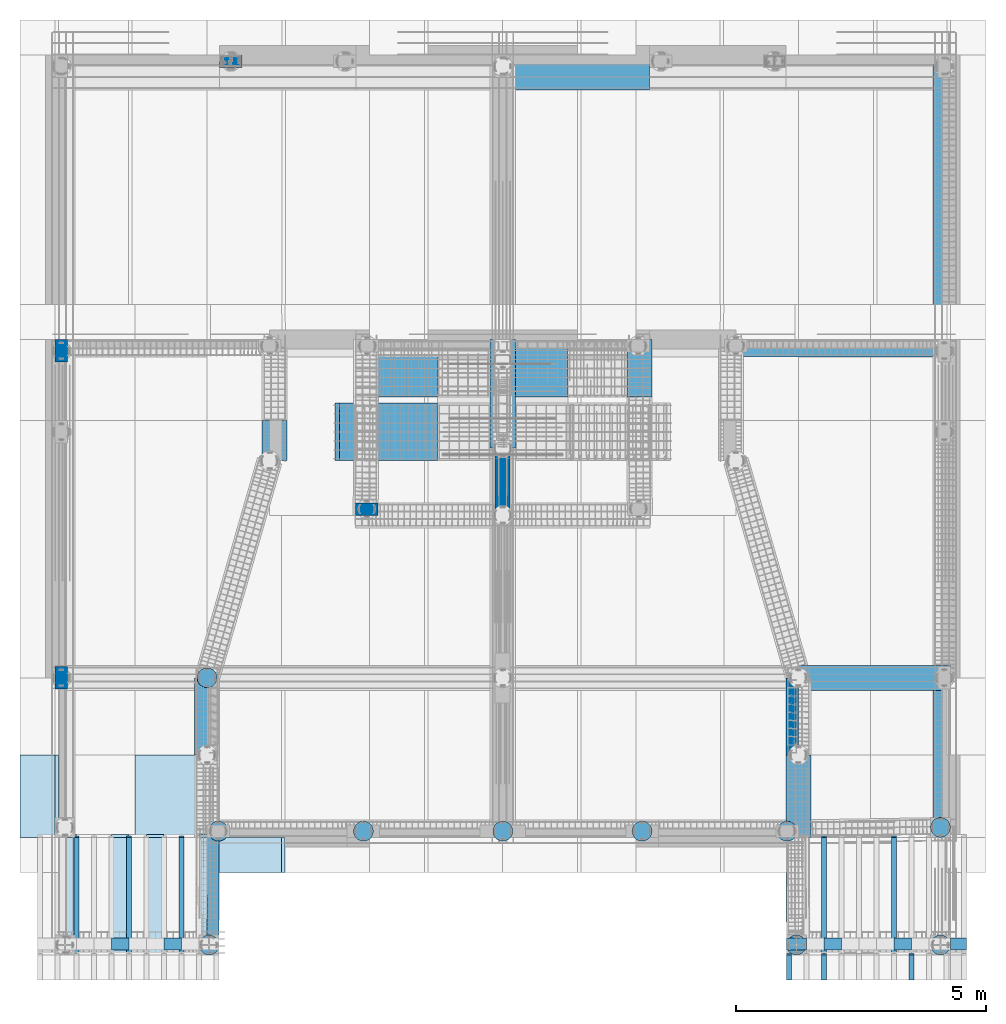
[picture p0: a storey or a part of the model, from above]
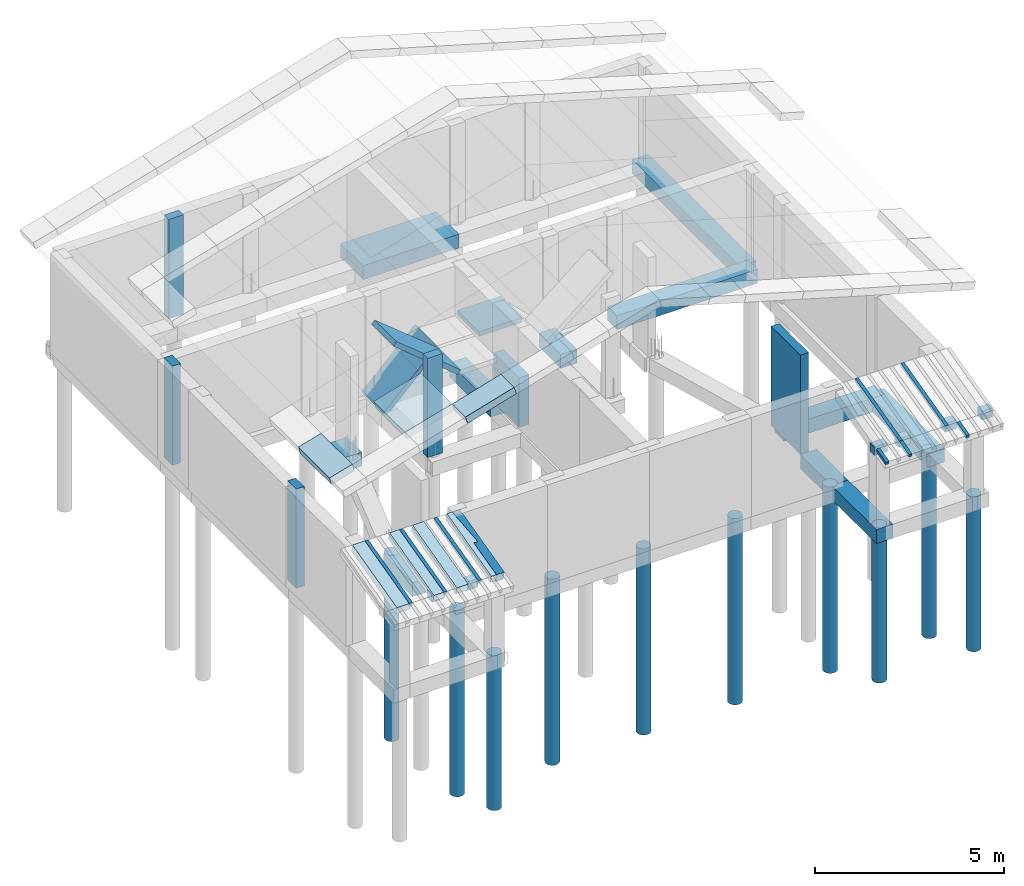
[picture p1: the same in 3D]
Properties of the parts of a building model (IFC4), part 2 of 5

# IfcReinforcingBarType, no part of this type: type
PredefinedType: LIGATURE; NominalDiameter: 0.008 m; CrossSectionArea: 0.000050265 m2; BarLength: 0.428429 m; Material: Steel

# IfcReinforcingBarType, no part of this type: type
PredefinedType: MAIN; NominalDiameter: 0.016 m; CrossSectionArea: 0.00020106 m2; BarLength: 1.24193 m; Material: Steel

# IfcReinforcingBarType, no part of this type: type
PredefinedType: MAIN; NominalDiameter: 0.016 m; CrossSectionArea: 0.00020106 m2; BarLength: 3.84 m; Material: Steel

# IfcReinforcingBarType, no part of this type: type
PredefinedType: MAIN; NominalDiameter: 0.016 m; CrossSectionArea: 0.00020106 m2; BarLength: 2.73943 m; Material: Steel

# IfcReinforcingBarType, no part of this type: type
PredefinedType: LIGATURE; NominalDiameter: 0.008 m; CrossSectionArea: 0.000050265 m2; BarLength: 1.37881 m; Material: Steel

# IfcReinforcingBarType, no part of this type: type
PredefinedType: LIGATURE; NominalDiameter: 0.008 m; CrossSectionArea: 0.000050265 m2; BarLength: 0.428429 m; Material: Steel

# IfcReinforcingBarType, no part of this type: type
PredefinedType: MAIN; NominalDiameter: 0.016 m; CrossSectionArea: 0.00020106 m2; BarLength: 1.24193 m; Material: Steel

# IfcReinforcingBarType, no part of this type: type
PredefinedType: MAIN; NominalDiameter: 0.016 m; CrossSectionArea: 0.00020106 m2; BarLength: 3.84 m; Material: Steel

# IfcReinforcingBarType, no part of this type: type
PredefinedType: MAIN; NominalDiameter: 0.016 m; CrossSectionArea: 0.00020106 m2; BarLength: 2.73943 m; Material: Steel

# IfcReinforcingBarType, no part of this type: type
PredefinedType: LIGATURE; NominalDiameter: 0.008 m; CrossSectionArea: 0.000050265 m2; BarLength: 1.3788 m; Material: Steel

# IfcReinforcingBarType, no part of this type: type
PredefinedType: LIGATURE; NominalDiameter: 0.008 m; CrossSectionArea: 0.000050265 m2; BarLength: 0.428429 m; Material: Steel

# IfcReinforcingBarType, no part of this type: type
PredefinedType: MAIN; NominalDiameter: 0.022 m; CrossSectionArea: 0.00038013 m2; BarLength: 1.47534 m; Material: Steel

# IfcReinforcingBarType, no part of this type: type
PredefinedType: MAIN; NominalDiameter: 0.016 m; CrossSectionArea: 0.00020106 m2; BarLength: 1.48193 m; Material: Steel

# IfcReinforcingBarType, no part of this type: type
PredefinedType: MAIN; NominalDiameter: 0.022 m; CrossSectionArea: 0.00038013 m2; BarLength: 4.08 m; Material: Steel

# IfcReinforcingBarType, no part of this type: type
PredefinedType: MAIN; NominalDiameter: 0.016 m; CrossSectionArea: 0.00020106 m2; BarLength: 4.08 m; Material: Steel

# IfcReinforcingBarType, no part of this type: type
PredefinedType: MAIN; NominalDiameter: 0.022 m; CrossSectionArea: 0.00038013 m2; BarLength: 2.73284 m; Material: Steel

# IfcReinforcingBarType, no part of this type: type
PredefinedType: MAIN; NominalDiameter: 0.016 m; CrossSectionArea: 0.00020106 m2; BarLength: 2.73943 m; Material: Steel

# IfcReinforcingBarType, no part of this type: type
PredefinedType: LIGATURE; NominalDiameter: 0.008 m; CrossSectionArea: 0.000050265 m2; BarLength: 1.37881 m; Material: Steel

# IfcReinforcingBarType, no part of this type: type
PredefinedType: LIGATURE; NominalDiameter: 0.008 m; CrossSectionArea: 0.000050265 m2; BarLength: 0.428429 m; Material: Steel

# IfcReinforcingBarType, no part of this type: type
PredefinedType: MAIN; NominalDiameter: 0.018 m; CrossSectionArea: 0.00025447 m2; BarLength: 1.31973 m; Material: Steel

# IfcReinforcingBarType, no part of this type: type
PredefinedType: MAIN; NominalDiameter: 0.016 m; CrossSectionArea: 0.00020106 m2; BarLength: 1.32193 m; Material: Steel

# IfcReinforcingBarType, no part of this type: type
PredefinedType: MAIN; NominalDiameter: 0.018 m; CrossSectionArea: 0.00025447 m2; BarLength: 3.92 m; Material: Steel

# IfcReinforcingBarType, no part of this type: type
PredefinedType: MAIN; NominalDiameter: 0.016 m; CrossSectionArea: 0.00020106 m2; BarLength: 3.92 m; Material: Steel

# IfcReinforcingBarType, no part of this type: type
PredefinedType: MAIN; NominalDiameter: 0.018 m; CrossSectionArea: 0.00025447 m2; BarLength: 3.98723 m; Material: Steel

# IfcReinforcingBarType, no part of this type: type
PredefinedType: MAIN; NominalDiameter: 0.016 m; CrossSectionArea: 0.00020106 m2; BarLength: 3.98943 m; Material: Steel

# IfcReinforcingBarType, no part of this type: type
PredefinedType: LIGATURE; NominalDiameter: 0.008 m; CrossSectionArea: 0.000050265 m2; BarLength: 1.37881 m; Material: Steel

# IfcReinforcingBarType, no part of this type: type
PredefinedType: LIGATURE; NominalDiameter: 0.008 m; CrossSectionArea: 0.000050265 m2; BarLength: 0.428429 m; Material: Steel

# IfcReinforcingBarType, no part of this type: type
PredefinedType: MAIN; NominalDiameter: 0.016 m; CrossSectionArea: 0.00020106 m2; BarLength: 1.24193 m; Material: Steel

# IfcReinforcingBarType, no part of this type: type
PredefinedType: MAIN; NominalDiameter: 0.016 m; CrossSectionArea: 0.00020106 m2; BarLength: 3.84 m; Material: Steel

# IfcReinforcingBarType, no part of this type: type
PredefinedType: MAIN; NominalDiameter: 0.016 m; CrossSectionArea: 0.00020106 m2; BarLength: 4.48943 m; Material: Steel

# IfcReinforcingBarType, no part of this type: type
PredefinedType: LIGATURE; NominalDiameter: 0.008 m; CrossSectionArea: 0.000050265 m2; BarLength: 1.37881 m; Material: Steel

# IfcReinforcingBarType, no part of this type: type
PredefinedType: LIGATURE; NominalDiameter: 0.008 m; CrossSectionArea: 0.000050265 m2; BarLength: 0.428429 m; Material: Steel

# IfcReinforcingBarType, no part of this type: type
PredefinedType: MAIN; NominalDiameter: 0.016 m; CrossSectionArea: 0.00020106 m2; BarLength: 1.29193 m; Material: Steel

# IfcReinforcingBarType, no part of this type: type
PredefinedType: MAIN; NominalDiameter: 0.016 m; CrossSectionArea: 0.00020106 m2; BarLength: 3.84 m; Material: Steel

# IfcReinforcingBarType, no part of this type: type
PredefinedType: MAIN; NominalDiameter: 0.016 m; CrossSectionArea: 0.00020106 m2; BarLength: 5.38943 m; Material: Steel

# IfcReinforcingBarType, no part of this type: type
PredefinedType: LIGATURE; NominalDiameter: 0.008 m; CrossSectionArea: 0.000050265 m2; BarLength: 0.478428 m; Material: Steel

# IfcReinforcingBarType, no part of this type: type
PredefinedType: LIGATURE; NominalDiameter: 0.008 m; CrossSectionArea: 0.000050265 m2; BarLength: 2.1788 m; Material: Steel

# IfcReinforcingBarType, no part of this type: type
PredefinedType: LIGATURE; NominalDiameter: 0.008 m; CrossSectionArea: 0.000050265 m2; BarLength: 1.85366 m; Material: Steel

# IfcReinforcingBarType, no part of this type: type
PredefinedType: MAIN; NominalDiameter: 0.016 m; CrossSectionArea: 0.00020106 m2; BarLength: 1.24193 m; Material: Steel

# IfcReinforcingBarType, no part of this type: type
PredefinedType: MAIN; NominalDiameter: 0.016 m; CrossSectionArea: 0.00020106 m2; BarLength: 3.84 m; Material: Steel

# IfcReinforcingBarType, no part of this type: type
PredefinedType: MAIN; NominalDiameter: 0.016 m; CrossSectionArea: 0.00020106 m2; BarLength: 4.48943 m; Material: Steel

# IfcReinforcingBarType, no part of this type: type
PredefinedType: LIGATURE; NominalDiameter: 0.008 m; CrossSectionArea: 0.000050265 m2; BarLength: 1.37881 m; Material: Steel

# IfcReinforcingBarType, no part of this type: type
PredefinedType: LIGATURE; NominalDiameter: 0.008 m; CrossSectionArea: 0.000050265 m2; BarLength: 0.428429 m; Material: Steel

# IfcReinforcingBarType, no part of this type: type
PredefinedType: MAIN; NominalDiameter: 0.018 m; CrossSectionArea: 0.00025447 m2; BarLength: 1.31973 m; Material: Steel

# IfcReinforcingBarType, no part of this type: type
PredefinedType: MAIN; NominalDiameter: 0.016 m; CrossSectionArea: 0.00020106 m2; BarLength: 1.32193 m; Material: Steel

# IfcReinforcingBarType, no part of this type: type
PredefinedType: MAIN; NominalDiameter: 0.018 m; CrossSectionArea: 0.00025447 m2; BarLength: 3.92 m; Material: Steel

# IfcReinforcingBarType, no part of this type: type
PredefinedType: MAIN; NominalDiameter: 0.016 m; CrossSectionArea: 0.00020106 m2; BarLength: 3.92 m; Material: Steel

# IfcReinforcingBarType, no part of this type: type
PredefinedType: MAIN; NominalDiameter: 0.018 m; CrossSectionArea: 0.00025447 m2; BarLength: 3.98723 m; Material: Steel

# IfcReinforcingBarType, no part of this type: type
PredefinedType: MAIN; NominalDiameter: 0.016 m; CrossSectionArea: 0.00020106 m2; BarLength: 3.98943 m; Material: Steel

# IfcReinforcingBarType, no part of this type: type
PredefinedType: LIGATURE; NominalDiameter: 0.008 m; CrossSectionArea: 0.000050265 m2; BarLength: 1.37881 m; Material: Steel

# IfcReinforcingBarType, no part of this type: type
PredefinedType: LIGATURE; NominalDiameter: 0.008 m; CrossSectionArea: 0.000050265 m2; BarLength: 0.428428 m; Material: Steel

# IfcReinforcingBarType, no part of this type: type
PredefinedType: MAIN; NominalDiameter: 0.022 m; CrossSectionArea: 0.00038013 m2; BarLength: 1.47534 m; Material: Steel

# IfcReinforcingBarType, no part of this type: type
PredefinedType: MAIN; NominalDiameter: 0.016 m; CrossSectionArea: 0.00020106 m2; BarLength: 1.48193 m; Material: Steel

# IfcReinforcingBarType, no part of this type: type
PredefinedType: MAIN; NominalDiameter: 0.022 m; CrossSectionArea: 0.00038013 m2; BarLength: 4.08 m; Material: Steel

# IfcReinforcingBarType, no part of this type: type
PredefinedType: MAIN; NominalDiameter: 0.016 m; CrossSectionArea: 0.00020106 m2; BarLength: 4.08 m; Material: Steel

# IfcReinforcingBarType, no part of this type: type
PredefinedType: MAIN; NominalDiameter: 0.022 m; CrossSectionArea: 0.00038013 m2; BarLength: 2.73284 m; Material: Steel

# IfcReinforcingBarType, no part of this type: type
PredefinedType: MAIN; NominalDiameter: 0.016 m; CrossSectionArea: 0.00020106 m2; BarLength: 2.73943 m; Material: Steel

# IfcReinforcingBarType, no part of this type: type
PredefinedType: LIGATURE; NominalDiameter: 0.008 m; CrossSectionArea: 0.000050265 m2; BarLength: 1.3788 m; Material: Steel

# IfcReinforcingBarType, no part of this type: type
PredefinedType: LIGATURE; NominalDiameter: 0.008 m; CrossSectionArea: 0.000050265 m2; BarLength: 0.428429 m; Material: Steel

# IfcReinforcingBarType, no part of this type: type
PredefinedType: MAIN; NominalDiameter: 0.016 m; CrossSectionArea: 0.00020106 m2; BarLength: 1.24193 m; Material: Steel

# IfcReinforcingBarType, no part of this type: type
PredefinedType: MAIN; NominalDiameter: 0.016 m; CrossSectionArea: 0.00020106 m2; BarLength: 3.84 m; Material: Steel

# IfcReinforcingBarType, no part of this type: type
PredefinedType: MAIN; NominalDiameter: 0.016 m; CrossSectionArea: 0.00020106 m2; BarLength: 0.839429 m; Material: Steel

# IfcReinforcingBarType, no part of this type: type
PredefinedType: LIGATURE; NominalDiameter: 0.008 m; CrossSectionArea: 0.000050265 m2; BarLength: 1.37881 m; Material: Steel

# IfcReinforcingBarType, no part of this type: type
PredefinedType: LIGATURE; NominalDiameter: 0.008 m; CrossSectionArea: 0.000050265 m2; BarLength: 0.428428 m; Material: Steel

# IfcReinforcingBarType, no part of this type: type
PredefinedType: MAIN; NominalDiameter: 0.016 m; CrossSectionArea: 0.00020106 m2; BarLength: 1.24193 m; Material: Steel

# IfcReinforcingBarType, no part of this type: type
PredefinedType: MAIN; NominalDiameter: 0.016 m; CrossSectionArea: 0.00020106 m2; BarLength: 3.33943 m; Material: Steel

# IfcReinforcingBarType, no part of this type: type
PredefinedType: LIGATURE; NominalDiameter: 0.008 m; CrossSectionArea: 0.000050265 m2; BarLength: 1.3788 m; Material: Steel

# IfcReinforcingBarType, no part of this type: type
PredefinedType: LIGATURE; NominalDiameter: 0.008 m; CrossSectionArea: 0.000050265 m2; BarLength: 0.428428 m; Material: Steel

# IfcReinforcingBarType, no part of this type: type
PredefinedType: MAIN; NominalDiameter: 0.018 m; CrossSectionArea: 0.00025447 m2; BarLength: 1.31973 m; Material: Steel

# IfcReinforcingBarType, no part of this type: type
PredefinedType: MAIN; NominalDiameter: 0.016 m; CrossSectionArea: 0.00020106 m2; BarLength: 1.32193 m; Material: Steel

# IfcReinforcingBarType, no part of this type: type
PredefinedType: MAIN; NominalDiameter: 0.018 m; CrossSectionArea: 0.00025447 m2; BarLength: 3.92 m; Material: Steel

# IfcReinforcingBarType, no part of this type: type
PredefinedType: MAIN; NominalDiameter: 0.016 m; CrossSectionArea: 0.00020106 m2; BarLength: 3.92 m; Material: Steel

# IfcReinforcingBarType, no part of this type: type
PredefinedType: MAIN; NominalDiameter: 0.016 m; CrossSectionArea: 0.00020106 m2; BarLength: 2.58943 m; Material: Steel

# IfcReinforcingBarType, no part of this type: type
PredefinedType: LIGATURE; NominalDiameter: 0.008 m; CrossSectionArea: 0.000050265 m2; BarLength: 1.3788 m; Material: Steel

# IfcReinforcingBarType, no part of this type: type
PredefinedType: LIGATURE; NominalDiameter: 0.008 m; CrossSectionArea: 0.000050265 m2; BarLength: 0.42843 m; Material: Steel

# IfcReinforcingBarType, no part of this type: type
PredefinedType: MAIN; NominalDiameter: 0.018 m; CrossSectionArea: 0.00025447 m2; BarLength: 1.36973 m; Material: Steel

# IfcReinforcingBarType, no part of this type: type
PredefinedType: MAIN; NominalDiameter: 0.016 m; CrossSectionArea: 0.00020106 m2; BarLength: 1.37193 m; Material: Steel

# IfcReinforcingBarType, no part of this type: type
PredefinedType: MAIN; NominalDiameter: 0.018 m; CrossSectionArea: 0.00025447 m2; BarLength: 3.92 m; Material: Steel

# IfcReinforcingBarType, no part of this type: type
PredefinedType: MAIN; NominalDiameter: 0.016 m; CrossSectionArea: 0.00020106 m2; BarLength: 3.92 m; Material: Steel

# IfcReinforcingBarType, no part of this type: type
PredefinedType: MAIN; NominalDiameter: 0.018 m; CrossSectionArea: 0.00025447 m2; BarLength: 3.48723 m; Material: Steel

# IfcReinforcingBarType, no part of this type: type
PredefinedType: MAIN; NominalDiameter: 0.016 m; CrossSectionArea: 0.00020106 m2; BarLength: 3.48943 m; Material: Steel

# IfcReinforcingBarType, no part of this type: type
PredefinedType: LIGATURE; NominalDiameter: 0.008 m; CrossSectionArea: 0.000050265 m2; BarLength: 1.4788 m; Material: Steel

# IfcReinforcingBarType, no part of this type: type
PredefinedType: LIGATURE; NominalDiameter: 0.008 m; CrossSectionArea: 0.000050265 m2; BarLength: 0.478429 m; Material: Steel

# IfcReinforcingBarType, no part of this type: type
PredefinedType: MAIN; NominalDiameter: 0.018 m; CrossSectionArea: 0.00025447 m2; BarLength: 1.31973 m; Material: Steel

# IfcReinforcingBarType, no part of this type: type
PredefinedType: MAIN; NominalDiameter: 0.016 m; CrossSectionArea: 0.00020106 m2; BarLength: 1.32193 m; Material: Steel

# IfcReinforcingBarType, no part of this type: type
PredefinedType: MAIN; NominalDiameter: 0.018 m; CrossSectionArea: 0.00025447 m2; BarLength: 3.92 m; Material: Steel

# IfcReinforcingBarType, no part of this type: type
PredefinedType: MAIN; NominalDiameter: 0.016 m; CrossSectionArea: 0.00020106 m2; BarLength: 3.92 m; Material: Steel

# IfcReinforcingBarType, no part of this type: type
PredefinedType: MAIN; NominalDiameter: 0.016 m; CrossSectionArea: 0.00020106 m2; BarLength: 2.58943 m; Material: Steel

# IfcReinforcingBarType, no part of this type: type
PredefinedType: LIGATURE; NominalDiameter: 0.008 m; CrossSectionArea: 0.000050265 m2; BarLength: 1.3788 m; Material: Steel

# IfcReinforcingBarType, no part of this type: type
PredefinedType: LIGATURE; NominalDiameter: 0.008 m; CrossSectionArea: 0.000050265 m2; BarLength: 0.428429 m; Material: Steel

# IfcReinforcingBarType, no part of this type: type
PredefinedType: MAIN; NominalDiameter: 0.016 m; CrossSectionArea: 0.00020106 m2; BarLength: 1.24193 m; Material: Steel

# IfcReinforcingBarType, no part of this type: type
PredefinedType: MAIN; NominalDiameter: 0.016 m; CrossSectionArea: 0.00020106 m2; BarLength: 3.33943 m; Material: Steel

# IfcReinforcingBarType, no part of this type: type
PredefinedType: LIGATURE; NominalDiameter: 0.008 m; CrossSectionArea: 0.000050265 m2; BarLength: 1.3788 m; Material: Steel

# IfcReinforcingBarType, no part of this type: type
PredefinedType: LIGATURE; NominalDiameter: 0.008 m; CrossSectionArea: 0.000050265 m2; BarLength: 0.428429 m; Material: Steel

# IfcReinforcingBarType, no part of this type: type
PredefinedType: MAIN; NominalDiameter: 0.016 m; CrossSectionArea: 0.00020106 m2; BarLength: 1.24193 m; Material: Steel

# IfcReinforcingBarType, no part of this type: type
PredefinedType: MAIN; NominalDiameter: 0.016 m; CrossSectionArea: 0.00020106 m2; BarLength: 3.84 m; Material: Steel

# IfcReinforcingBarType, no part of this type: type
PredefinedType: MAIN; NominalDiameter: 0.016 m; CrossSectionArea: 0.00020106 m2; BarLength: 0.83943 m; Material: Steel

# IfcReinforcingBarType, no part of this type: type
PredefinedType: LIGATURE; NominalDiameter: 0.008 m; CrossSectionArea: 0.000050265 m2; BarLength: 1.3788 m; Material: Steel

# IfcReinforcingBarType, no part of this type: type
PredefinedType: LIGATURE; NominalDiameter: 0.008 m; CrossSectionArea: 0.000050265 m2; BarLength: 0.428427 m; Material: Steel

# IfcReinforcingBarType, no part of this type: type
PredefinedType: MAIN; NominalDiameter: 0.016 m; CrossSectionArea: 0.00020106 m2; BarLength: 1.24193 m; Material: Steel

# IfcReinforcingBarType, no part of this type: type
PredefinedType: MAIN; NominalDiameter: 0.016 m; CrossSectionArea: 0.00020106 m2; BarLength: 3.33943 m; Material: Steel

# IfcReinforcingBarType, no part of this type: type
PredefinedType: LIGATURE; NominalDiameter: 0.008 m; CrossSectionArea: 0.000050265 m2; BarLength: 3.55879 m; Material: Steel

# IfcReinforcingBarType, no part of this type: type
PredefinedType: LIGATURE; NominalDiameter: 0.008 m; CrossSectionArea: 0.000050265 m2; BarLength: 0.42843 m; Material: Steel

# IfcReinforcingBarType, no part of this type: type
PredefinedType: LIGATURE; NominalDiameter: 0.008 m; CrossSectionArea: 0.000050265 m2; BarLength: 2.26457 m; Material: Steel

# IfcReinforcingBarType, no part of this type: type
PredefinedType: LIGATURE; NominalDiameter: 0.008 m; CrossSectionArea: 0.000050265 m2; BarLength: 2.91168 m; Material: Steel

# IfcReinforcingBarType, no part of this type: type
PredefinedType: MAIN; NominalDiameter: 0.02 m; CrossSectionArea: 0.00031416 m2; BarLength: 1.39754 m; Material: Steel

# IfcReinforcingBarType, no part of this type: type
PredefinedType: MAIN; NominalDiameter: 0.016 m; CrossSectionArea: 0.00020106 m2; BarLength: 1.40193 m; Material: Steel

# IfcReinforcingBarType, no part of this type: type
PredefinedType: MAIN; NominalDiameter: 0.02 m; CrossSectionArea: 0.00031416 m2; BarLength: 4 m; Material: Steel

# IfcReinforcingBarType, no part of this type: type
PredefinedType: MAIN; NominalDiameter: 0.016 m; CrossSectionArea: 0.00020106 m2; BarLength: 4 m; Material: Steel

# IfcReinforcingBarType, no part of this type: type
PredefinedType: MAIN; NominalDiameter: 0.02 m; CrossSectionArea: 0.00031416 m2; BarLength: 3.98504 m; Material: Steel

# IfcReinforcingBarType, no part of this type: type
PredefinedType: MAIN; NominalDiameter: 0.016 m; CrossSectionArea: 0.00020106 m2; BarLength: 3.98943 m; Material: Steel

# IfcReinforcingBarType, no part of this type: type
PredefinedType: LIGATURE; NominalDiameter: 0.008 m; CrossSectionArea: 0.000050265 m2; BarLength: 2.0788 m; Material: Steel

# IfcReinforcingBarType, no part of this type: type
PredefinedType: LIGATURE; NominalDiameter: 0.008 m; CrossSectionArea: 0.000050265 m2; BarLength: 1.11882 m; Material: Steel

# IfcReinforcingBarType, no part of this type: type
PredefinedType: MAIN; NominalDiameter: 0.016 m; CrossSectionArea: 0.00020106 m2; BarLength: 1.29193 m; Material: Steel

# IfcReinforcingBarType, no part of this type: type
PredefinedType: MAIN; NominalDiameter: 0.016 m; CrossSectionArea: 0.00020106 m2; BarLength: 3.84 m; Material: Steel

# IfcReinforcingBarType, no part of this type: type
PredefinedType: MAIN; NominalDiameter: 0.016 m; CrossSectionArea: 0.00020106 m2; BarLength: 5.38943 m; Material: Steel

# IfcReinforcingBarType, no part of this type: type
PredefinedType: LIGATURE; NominalDiameter: 0.008 m; CrossSectionArea: 0.000050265 m2; BarLength: 2.0031 m; Material: Steel

# IfcReinforcingBarType, no part of this type: type
PredefinedType: LIGATURE; NominalDiameter: 0.008 m; CrossSectionArea: 0.000050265 m2; BarLength: 3.25879 m; Material: Steel

# IfcReinforcingBarType, no part of this type: type
PredefinedType: LIGATURE; NominalDiameter: 0.008 m; CrossSectionArea: 0.000050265 m2; BarLength: 0.478428 m; Material: Steel

# IfcReinforcingBarType, no part of this type: type
PredefinedType: LIGATURE; NominalDiameter: 0.008 m; CrossSectionArea: 0.000050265 m2; BarLength: 3.25879 m; Material: Steel

# IfcReinforcingBarType, no part of this type: type
PredefinedType: LIGATURE; NominalDiameter: 0.008 m; CrossSectionArea: 0.000050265 m2; BarLength: 2.95158 m; Material: Steel

# IfcReinforcingBarType, no part of this type: type
PredefinedType: LIGATURE; NominalDiameter: 0.008 m; CrossSectionArea: 0.000050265 m2; BarLength: 1.37506 m; Material: Steel

# IfcReinforcingBarType, no part of this type: type
PredefinedType: MAIN; NominalDiameter: 0.016 m; CrossSectionArea: 0.00020106 m2; BarLength: 1.24193 m; Material: Steel

# IfcReinforcingBarType, no part of this type: type
PredefinedType: MAIN; NominalDiameter: 0.016 m; CrossSectionArea: 0.00020106 m2; BarLength: 3.33943 m; Material: Steel

# IfcReinforcingBarType, no part of this type: type
PredefinedType: LIGATURE; NominalDiameter: 0.008 m; CrossSectionArea: 0.000050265 m2; BarLength: 3.55879 m; Material: Steel

# IfcReinforcingBarType, no part of this type: type
PredefinedType: LIGATURE; NominalDiameter: 0.008 m; CrossSectionArea: 0.000050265 m2; BarLength: 0.428429 m; Material: Steel

# IfcReinforcingBarType, no part of this type: type
PredefinedType: LIGATURE; NominalDiameter: 0.008 m; CrossSectionArea: 0.000050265 m2; BarLength: 2.26457 m; Material: Steel

# IfcReinforcingBarType, no part of this type: type
PredefinedType: LIGATURE; NominalDiameter: 0.008 m; CrossSectionArea: 0.000050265 m2; BarLength: 2.91168 m; Material: Steel

# IfcReinforcingBarType, no part of this type: type
PredefinedType: MAIN; NominalDiameter: 0.02 m; CrossSectionArea: 0.00031416 m2; BarLength: 1.39754 m; Material: Steel

# IfcReinforcingBarType, no part of this type: type
PredefinedType: MAIN; NominalDiameter: 0.016 m; CrossSectionArea: 0.00020106 m2; BarLength: 1.40193 m; Material: Steel

# IfcReinforcingBarType, no part of this type: type
PredefinedType: MAIN; NominalDiameter: 0.02 m; CrossSectionArea: 0.00031416 m2; BarLength: 4 m; Material: Steel

# IfcReinforcingBarType, no part of this type: type
PredefinedType: MAIN; NominalDiameter: 0.016 m; CrossSectionArea: 0.00020106 m2; BarLength: 4 m; Material: Steel

# IfcReinforcingBarType, no part of this type: type
PredefinedType: MAIN; NominalDiameter: 0.02 m; CrossSectionArea: 0.00031416 m2; BarLength: 3.98504 m; Material: Steel

# IfcReinforcingBarType, no part of this type: type
PredefinedType: MAIN; NominalDiameter: 0.016 m; CrossSectionArea: 0.00020106 m2; BarLength: 3.98943 m; Material: Steel

# IfcReinforcingBarType, no part of this type: type
PredefinedType: LIGATURE; NominalDiameter: 0.008 m; CrossSectionArea: 0.000050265 m2; BarLength: 2.0788 m; Material: Steel

# IfcReinforcingBarType, no part of this type: type
PredefinedType: LIGATURE; NominalDiameter: 0.008 m; CrossSectionArea: 0.000050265 m2; BarLength: 1.11882 m; Material: Steel

# IfcReinforcingBarType, no part of this type: type
PredefinedType: MAIN; NominalDiameter: 0.016 m; CrossSectionArea: 0.00020106 m2; BarLength: 5.6 m; Material: Steel

# IfcReinforcingBarType, no part of this type: type
PredefinedType: LIGATURE; NominalDiameter: 0.008 m; CrossSectionArea: 0.000050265 m2; BarLength: 1.00616 m; Material: Steel

# IfcReinforcingBarType, no part of this type: type
PredefinedType: MAIN; NominalDiameter: 0.016 m; CrossSectionArea: 0.00020106 m2; BarLength: 5.6 m; Material: Steel

# IfcReinforcingBarType, no part of this type: type
PredefinedType: LIGATURE; NominalDiameter: 0.008 m; CrossSectionArea: 0.000050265 m2; BarLength: 1.00616 m; Material: Steel

# IfcReinforcingBarType, no part of this type: type
PredefinedType: MAIN; NominalDiameter: 0.016 m; CrossSectionArea: 0.00020106 m2; BarLength: 5.6 m; Material: Steel

# IfcReinforcingBarType, no part of this type: type
PredefinedType: LIGATURE; NominalDiameter: 0.008 m; CrossSectionArea: 0.000050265 m2; BarLength: 1.00616 m; Material: Steel

# IfcReinforcingBarType, no part of this type: type
PredefinedType: MAIN; NominalDiameter: 0.016 m; CrossSectionArea: 0.00020106 m2; BarLength: 5.6 m; Material: Steel

# IfcReinforcingBarType, no part of this type: type
PredefinedType: LIGATURE; NominalDiameter: 0.008 m; CrossSectionArea: 0.000050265 m2; BarLength: 1.00616 m; Material: Steel

# IfcReinforcingBarType, no part of this type: type
PredefinedType: MAIN; NominalDiameter: 0.016 m; CrossSectionArea: 0.00020106 m2; BarLength: 6.6 m; Material: Steel

# IfcReinforcingBarType, no part of this type: type
PredefinedType: LIGATURE; NominalDiameter: 0.008 m; CrossSectionArea: 0.000050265 m2; BarLength: 1.00616 m; Material: Steel

# IfcReinforcingBarType, no part of this type: type
PredefinedType: MAIN; NominalDiameter: 0.016 m; CrossSectionArea: 0.00020106 m2; BarLength: 6.6 m; Material: Steel

# IfcReinforcingBarType, no part of this type: type
PredefinedType: LIGATURE; NominalDiameter: 0.008 m; CrossSectionArea: 0.000050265 m2; BarLength: 1.00616 m; Material: Steel

# IfcReinforcingBarType, no part of this type: type
PredefinedType: MAIN; NominalDiameter: 0.016 m; CrossSectionArea: 0.00020106 m2; BarLength: 6.6 m; Material: Steel

# IfcReinforcingBarType, no part of this type: type
PredefinedType: LIGATURE; NominalDiameter: 0.008 m; CrossSectionArea: 0.000050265 m2; BarLength: 1.00616 m; Material: Steel

# IfcReinforcingBarType, no part of this type: type
PredefinedType: MAIN; NominalDiameter: 0.016 m; CrossSectionArea: 0.00020106 m2; BarLength: 6.6 m; Material: Steel

# IfcReinforcingBarType, no part of this type: type
PredefinedType: LIGATURE; NominalDiameter: 0.008 m; CrossSectionArea: 0.000050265 m2; BarLength: 1.00616 m; Material: Steel

# IfcReinforcingBarType, no part of this type: type
PredefinedType: MAIN; NominalDiameter: 0.016 m; CrossSectionArea: 0.00020106 m2; BarLength: 6.6 m; Material: Steel

# IfcReinforcingBarType, no part of this type: type
PredefinedType: LIGATURE; NominalDiameter: 0.008 m; CrossSectionArea: 0.000050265 m2; BarLength: 1.00616 m; Material: Steel

# IfcReinforcingBarType, no part of this type: type
PredefinedType: MAIN; NominalDiameter: 0.016 m; CrossSectionArea: 0.00020106 m2; BarLength: 6.6 m; Material: Steel

# IfcReinforcingBarType, no part of this type: type
PredefinedType: LIGATURE; NominalDiameter: 0.008 m; CrossSectionArea: 0.000050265 m2; BarLength: 1.00616 m; Material: Steel

# IfcReinforcingBarType, no part of this type: type
PredefinedType: MAIN; NominalDiameter: 0.016 m; CrossSectionArea: 0.00020106 m2; BarLength: 6.6 m; Material: Steel

# IfcReinforcingBarType, no part of this type: type
PredefinedType: LIGATURE; NominalDiameter: 0.008 m; CrossSectionArea: 0.000050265 m2; BarLength: 1.00616 m; Material: Steel

# IfcReinforcingBarType, no part of this type: type
PredefinedType: MAIN; NominalDiameter: 0.016 m; CrossSectionArea: 0.00020106 m2; BarLength: 6.6 m; Material: Steel

# IfcReinforcingBarType, no part of this type: type
PredefinedType: LIGATURE; NominalDiameter: 0.008 m; CrossSectionArea: 0.000050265 m2; BarLength: 1.00616 m; Material: Steel

# IfcReinforcingBarType, no part of this type: type
PredefinedType: MAIN; NominalDiameter: 0.016 m; CrossSectionArea: 0.00020106 m2; BarLength: 6.6 m; Material: Steel

# IfcReinforcingBarType, no part of this type: type
PredefinedType: LIGATURE; NominalDiameter: 0.008 m; CrossSectionArea: 0.000050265 m2; BarLength: 1.00616 m; Material: Steel

# IfcReinforcingBarType, no part of this type: type
PredefinedType: MAIN; NominalDiameter: 0.016 m; CrossSectionArea: 0.00020106 m2; BarLength: 6.6 m; Material: Steel

# IfcReinforcingBarType, no part of this type: type
PredefinedType: LIGATURE; NominalDiameter: 0.008 m; CrossSectionArea: 0.000050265 m2; BarLength: 1.00616 m; Material: Steel

# IfcReinforcingBarType, no part of this type: type
PredefinedType: MAIN; NominalDiameter: 0.016 m; CrossSectionArea: 0.00020106 m2; BarLength: 6.6 m; Material: Steel

# IfcReinforcingBarType, no part of this type: type
PredefinedType: LIGATURE; NominalDiameter: 0.008 m; CrossSectionArea: 0.000050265 m2; BarLength: 1.00616 m; Material: Steel

# IfcReinforcingBarType, no part of this type: type
PredefinedType: MAIN; NominalDiameter: 0.016 m; CrossSectionArea: 0.00020106 m2; BarLength: 6.6 m; Material: Steel

# IfcReinforcingBarType, no part of this type: type
PredefinedType: LIGATURE; NominalDiameter: 0.008 m; CrossSectionArea: 0.000050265 m2; BarLength: 1.00616 m; Material: Steel

# IfcReinforcingBarType, no part of this type: type
PredefinedType: MAIN; NominalDiameter: 0.016 m; CrossSectionArea: 0.00020106 m2; BarLength: 6.6 m; Material: Steel

# IfcReinforcingBarType, no part of this type: type
PredefinedType: LIGATURE; NominalDiameter: 0.008 m; CrossSectionArea: 0.000050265 m2; BarLength: 1.00616 m; Material: Steel

# IfcReinforcingBarType, no part of this type: type
PredefinedType: MAIN; NominalDiameter: 0.016 m; CrossSectionArea: 0.00020106 m2; BarLength: 6.6 m; Material: Steel

# IfcReinforcingBarType, no part of this type: type
PredefinedType: LIGATURE; NominalDiameter: 0.008 m; CrossSectionArea: 0.000050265 m2; BarLength: 1.00616 m; Material: Steel

# IfcReinforcingBarType, no part of this type: type
PredefinedType: MAIN; NominalDiameter: 0.016 m; CrossSectionArea: 0.00020106 m2; BarLength: 6.6 m; Material: Steel

# IfcReinforcingBarType, no part of this type: type
PredefinedType: LIGATURE; NominalDiameter: 0.008 m; CrossSectionArea: 0.000050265 m2; BarLength: 1.00616 m; Material: Steel

# IfcReinforcingBarType, no part of this type: type
PredefinedType: MAIN; NominalDiameter: 0.016 m; CrossSectionArea: 0.00020106 m2; BarLength: 6.6 m; Material: Steel

# IfcReinforcingBarType, no part of this type: type
PredefinedType: LIGATURE; NominalDiameter: 0.008 m; CrossSectionArea: 0.000050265 m2; BarLength: 1.00616 m; Material: Steel

# IfcReinforcingBarType, no part of this type: type
PredefinedType: MAIN; NominalDiameter: 0.016 m; CrossSectionArea: 0.00020106 m2; BarLength: 6.6 m; Material: Steel

# IfcReinforcingBarType, no part of this type: type
PredefinedType: LIGATURE; NominalDiameter: 0.008 m; CrossSectionArea: 0.000050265 m2; BarLength: 1.00616 m; Material: Steel

# IfcReinforcingBarType, no part of this type: type
PredefinedType: MAIN; NominalDiameter: 0.016 m; CrossSectionArea: 0.00020106 m2; BarLength: 6.6 m; Material: Steel

# IfcReinforcingBarType, no part of this type: type
PredefinedType: LIGATURE; NominalDiameter: 0.008 m; CrossSectionArea: 0.000050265 m2; BarLength: 1.00616 m; Material: Steel

# IfcReinforcingBarType, no part of this type: type
PredefinedType: MAIN; NominalDiameter: 0.016 m; CrossSectionArea: 0.00020106 m2; BarLength: 6.6 m; Material: Steel

# IfcReinforcingBarType, no part of this type: type
PredefinedType: LIGATURE; NominalDiameter: 0.008 m; CrossSectionArea: 0.000050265 m2; BarLength: 1.00616 m; Material: Steel

# IfcReinforcingBarType, no part of this type: type
PredefinedType: MAIN; NominalDiameter: 0.016 m; CrossSectionArea: 0.00020106 m2; BarLength: 6.6 m; Material: Steel

# IfcReinforcingBarType, no part of this type: type
PredefinedType: LIGATURE; NominalDiameter: 0.008 m; CrossSectionArea: 0.000050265 m2; BarLength: 1.00616 m; Material: Steel

# IfcReinforcingBarType, no part of this type: type
PredefinedType: MAIN; NominalDiameter: 0.016 m; CrossSectionArea: 0.00020106 m2; BarLength: 6.6 m; Material: Steel

# IfcReinforcingBarType, no part of this type: type
PredefinedType: LIGATURE; NominalDiameter: 0.008 m; CrossSectionArea: 0.000050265 m2; BarLength: 1.00616 m; Material: Steel

# IfcReinforcingBarType, no part of this type: type
PredefinedType: MAIN; NominalDiameter: 0.016 m; CrossSectionArea: 0.00020106 m2; BarLength: 5.6 m; Material: Steel

# IfcReinforcingBarType, no part of this type: type
PredefinedType: LIGATURE; NominalDiameter: 0.008 m; CrossSectionArea: 0.000050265 m2; BarLength: 1.00616 m; Material: Steel

# IfcReinforcingBarType, no part of this type: type
PredefinedType: MAIN; NominalDiameter: 0.016 m; CrossSectionArea: 0.00020106 m2; BarLength: 5.6 m; Material: Steel

# IfcReinforcingBarType, no part of this type: type
PredefinedType: LIGATURE; NominalDiameter: 0.008 m; CrossSectionArea: 0.000050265 m2; BarLength: 1.00616 m; Material: Steel

# IfcReinforcingBarType, no part of this type: type
PredefinedType: MAIN; NominalDiameter: 0.016 m; CrossSectionArea: 0.00020106 m2; BarLength: 5.6 m; Material: Steel

# IfcReinforcingBarType, no part of this type: type
PredefinedType: LIGATURE; NominalDiameter: 0.008 m; CrossSectionArea: 0.000050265 m2; BarLength: 1.00616 m; Material: Steel

# IfcReinforcingBarType, no part of this type: type
PredefinedType: MAIN; NominalDiameter: 0.016 m; CrossSectionArea: 0.00020106 m2; BarLength: 5.6 m; Material: Steel

# IfcReinforcingBarType, no part of this type: type
PredefinedType: LIGATURE; NominalDiameter: 0.008 m; CrossSectionArea: 0.000050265 m2; BarLength: 1.00616 m; Material: Steel

# IfcReinforcingBarType, no part of this type: type
PredefinedType: MAIN; NominalDiameter: 0.016 m; CrossSectionArea: 0.00020106 m2; BarLength: 5.6 m; Material: Steel

# IfcReinforcingBarType, no part of this type: type
PredefinedType: LIGATURE; NominalDiameter: 0.008 m; CrossSectionArea: 0.000050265 m2; BarLength: 1.00616 m; Material: Steel

# IfcReinforcingBarType, no part of this type: type
PredefinedType: MAIN; NominalDiameter: 0.016 m; CrossSectionArea: 0.00020106 m2; BarLength: 5.6 m; Material: Steel

# IfcReinforcingBarType, no part of this type: type
PredefinedType: LIGATURE; NominalDiameter: 0.008 m; CrossSectionArea: 0.000050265 m2; BarLength: 1.00616 m; Material: Steel

# IfcReinforcingBarType, no part of this type: type
PredefinedType: MAIN; NominalDiameter: 0.016 m; CrossSectionArea: 0.00020106 m2; BarLength: 5.6 m; Material: Steel

# IfcReinforcingBarType, no part of this type: type
PredefinedType: LIGATURE; NominalDiameter: 0.008 m; CrossSectionArea: 0.000050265 m2; BarLength: 1.00616 m; Material: Steel

# IfcReinforcingBarType, no part of this type: type
PredefinedType: MAIN; NominalDiameter: 0.016 m; CrossSectionArea: 0.00020106 m2; BarLength: 6.6 m; Material: Steel

# IfcReinforcingBarType, no part of this type: type
PredefinedType: LIGATURE; NominalDiameter: 0.008 m; CrossSectionArea: 0.000050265 m2; BarLength: 1.00616 m; Material: Steel

# IfcReinforcingBarType, no part of this type: type
PredefinedType: MAIN; NominalDiameter: 0.016 m; CrossSectionArea: 0.00020106 m2; BarLength: 6.6 m; Material: Steel

# IfcReinforcingBarType, no part of this type: type
PredefinedType: LIGATURE; NominalDiameter: 0.008 m; CrossSectionArea: 0.000050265 m2; BarLength: 1.00616 m; Material: Steel

# IfcReinforcingBarType, no part of this type: type
PredefinedType: MAIN; NominalDiameter: 0.016 m; CrossSectionArea: 0.00020106 m2; BarLength: 6.6 m; Material: Steel

# IfcReinforcingBarType, no part of this type: type
PredefinedType: LIGATURE; NominalDiameter: 0.008 m; CrossSectionArea: 0.000050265 m2; BarLength: 1.00616 m; Material: Steel

# IfcReinforcingBarType, no part of this type: type
PredefinedType: MAIN; NominalDiameter: 0.016 m; CrossSectionArea: 0.00020106 m2; BarLength: 6.6 m; Material: Steel

# IfcReinforcingBarType, no part of this type: type
PredefinedType: LIGATURE; NominalDiameter: 0.008 m; CrossSectionArea: 0.000050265 m2; BarLength: 1.00616 m; Material: Steel

# IfcReinforcingBarType, no part of this type: type
PredefinedType: MAIN; NominalDiameter: 0.016 m; CrossSectionArea: 0.00020106 m2; BarLength: 6.6 m; Material: Steel

# IfcReinforcingBarType, no part of this type: type
PredefinedType: LIGATURE; NominalDiameter: 0.008 m; CrossSectionArea: 0.000050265 m2; BarLength: 1.00616 m; Material: Steel

# IfcReinforcingBarType, no part of this type: type
PredefinedType: MAIN; NominalDiameter: 0.016 m; CrossSectionArea: 0.00020106 m2; BarLength: 6.6 m; Material: Steel

# IfcReinforcingBarType, no part of this type: type
PredefinedType: LIGATURE; NominalDiameter: 0.008 m; CrossSectionArea: 0.000050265 m2; BarLength: 1.00616 m; Material: Steel

# IfcReinforcingBarType, no part of this type: type
PredefinedType: MAIN; NominalDiameter: 0.016 m; CrossSectionArea: 0.00020106 m2; BarLength: 6.6 m; Material: Steel

# IfcReinforcingBarType, no part of this type: type
PredefinedType: LIGATURE; NominalDiameter: 0.008 m; CrossSectionArea: 0.000050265 m2; BarLength: 1.00616 m; Material: Steel

# IfcReinforcingBarType, no part of this type: type
PredefinedType: MAIN; NominalDiameter: 0.016 m; CrossSectionArea: 0.00020106 m2; BarLength: 6.6 m; Material: Steel

# IfcReinforcingBarType, no part of this type: type
PredefinedType: LIGATURE; NominalDiameter: 0.008 m; CrossSectionArea: 0.000050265 m2; BarLength: 1.00616 m; Material: Steel

# IfcReinforcingBarType, no part of this type: type
PredefinedType: LIGATURE; NominalDiameter: 0.008 m; CrossSectionArea: 0.000050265 m2; BarLength: 0.638887 m; Material: Steel

# IfcReinforcingBarType, no part of this type: type
PredefinedType: MAIN; NominalDiameter: 0.016 m; CrossSectionArea: 0.00020106 m2; BarLength: 3.40121 m; Material: Steel

# IfcReinforcingBarType, no part of this type: type
PredefinedType: LIGATURE; NominalDiameter: 0.008 m; CrossSectionArea: 0.000050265 m2; BarLength: 1.48681 m; Material: Steel

# IfcReinforcingBarType, no part of this type: type
PredefinedType: MAIN; NominalDiameter: 0.016 m; CrossSectionArea: 0.00020106 m2; BarLength: 10.9956 m; Material: Steel

# IfcReinforcingBarType, no part of this type: type
PredefinedType: MAIN; NominalDiameter: 0.016 m; CrossSectionArea: 0.00020106 m2; BarLength: 8.99561 m; Material: Steel

# IfcReinforcingBarType, no part of this type: type
PredefinedType: MAIN; NominalDiameter: 0.018 m; CrossSectionArea: 0.00025447 m2; BarLength: 10.9956 m; Material: Steel

# IfcReinforcingBarType, no part of this type: type
PredefinedType: MAIN; NominalDiameter: 0.018 m; CrossSectionArea: 0.00025447 m2; BarLength: 8.99561 m; Material: Steel

# IfcReinforcingBarType, no part of this type: type
PredefinedType: MAIN; NominalDiameter: 0.014 m; CrossSectionArea: 0.00015394 m2; BarLength: 3 m; Material: Steel

# IfcReinforcingBarType, no part of this type: type
PredefinedType: MAIN; NominalDiameter: 0.012 m; CrossSectionArea: 0.0001131 m2; BarLength: 3.50121 m; Material: Steel

# IfcReinforcingBarType, no part of this type: type
PredefinedType: MAIN; NominalDiameter: 0.012 m; CrossSectionArea: 0.0001131 m2; BarLength: 6.33121 m; Material: Steel

# IfcReinforcingBarType, no part of this type: type
PredefinedType: LIGATURE; NominalDiameter: 0.008 m; CrossSectionArea: 0.000050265 m2; BarLength: 1.4868 m; Material: Steel

# IfcReinforcingBarType, no part of this type: type
PredefinedType: MAIN; NominalDiameter: 0.016 m; CrossSectionArea: 0.00020106 m2; BarLength: 8.5 m; Material: Steel

# IfcReinforcingBarType, no part of this type: type
PredefinedType: MAIN; NominalDiameter: 0.016 m; CrossSectionArea: 0.00020106 m2; BarLength: 1.69142 m; Material: Steel

# IfcReinforcingBarType, no part of this type: type
PredefinedType: MAIN; NominalDiameter: 0.016 m; CrossSectionArea: 0.00020106 m2; BarLength: 1.69142 m; Material: Steel

# IfcReinforcingBarType, no part of this type: type
PredefinedType: MAIN; NominalDiameter: 0.012 m; CrossSectionArea: 0.0001131 m2; BarLength: 2.38121 m; Material: Steel

# IfcReinforcingBarType, no part of this type: type
PredefinedType: MAIN; NominalDiameter: 0.012 m; CrossSectionArea: 0.0001131 m2; BarLength: 3.26121 m; Material: Steel

# IfcReinforcingBarType, no part of this type: type
PredefinedType: MAIN; NominalDiameter: 0.012 m; CrossSectionArea: 0.0001131 m2; BarLength: 3.08121 m; Material: Steel

# IfcReinforcingBarType, no part of this type: type
PredefinedType: LIGATURE; NominalDiameter: 0.008 m; CrossSectionArea: 0.000050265 m2; BarLength: 1.4868 m; Material: Steel

# IfcReinforcingBarType, no part of this type: type
PredefinedType: MAIN; NominalDiameter: 0.016 m; CrossSectionArea: 0.00020106 m2; BarLength: 9.6922 m; Material: Steel

# IfcReinforcingBarType, no part of this type: type
PredefinedType: MAIN; NominalDiameter: 0.012 m; CrossSectionArea: 0.0001131 m2; BarLength: 5.02043 m; Material: Steel

# IfcReinforcingBarType, no part of this type: type
PredefinedType: MAIN; NominalDiameter: 0.012 m; CrossSectionArea: 0.0001131 m2; BarLength: 5.02043 m; Material: Steel

# IfcReinforcingBarType, no part of this type: type
PredefinedType: MAIN; NominalDiameter: 0.012 m; CrossSectionArea: 0.0001131 m2; BarLength: 5.0192 m; Material: Steel

# IfcReinforcingBarType, no part of this type: type
PredefinedType: MAIN; NominalDiameter: 0.012 m; CrossSectionArea: 0.0001131 m2; BarLength: 5.0192 m; Material: Steel

# IfcReinforcingBarType, no part of this type: type
PredefinedType: LIGATURE; NominalDiameter: 0.008 m; CrossSectionArea: 0.000050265 m2; BarLength: 1.4868 m; Material: Steel

# IfcReinforcingBarType, no part of this type: type
PredefinedType: MAIN; NominalDiameter: 0.016 m; CrossSectionArea: 0.00020106 m2; BarLength: 4.91121 m; Material: Steel

# IfcReinforcingBarType, no part of this type: type
PredefinedType: MAIN; NominalDiameter: 0.012 m; CrossSectionArea: 0.0001131 m2; BarLength: 4.75121 m; Material: Steel

# IfcReinforcingBarType, no part of this type: type
PredefinedType: LIGATURE; NominalDiameter: 0.008 m; CrossSectionArea: 0.000050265 m2; BarLength: 2.58679 m; Material: Steel

# IfcReinforcingBarType, no part of this type: type
PredefinedType: MAIN; NominalDiameter: 0.014 m; CrossSectionArea: 0.00015394 m2; BarLength: 3.8923 m; Material: Steel

# IfcReinforcingBarType, no part of this type: type
PredefinedType: MAIN; NominalDiameter: 0.014 m; CrossSectionArea: 0.00015394 m2; BarLength: 3.89798 m; Material: Steel

# IfcReinforcingBarType, no part of this type: type
PredefinedType: MAIN; NominalDiameter: 0.014 m; CrossSectionArea: 0.00015394 m2; BarLength: 3.08814 m; Material: Steel

# IfcReinforcingBarType, no part of this type: type
PredefinedType: MAIN; NominalDiameter: 0.014 m; CrossSectionArea: 0.00015394 m2; BarLength: 3.08814 m; Material: Steel

# IfcReinforcingBarType, no part of this type: type
PredefinedType: MAIN; NominalDiameter: 0.014 m; CrossSectionArea: 0.00015394 m2; BarLength: 1.66861 m; Material: Steel

# IfcReinforcingBarType, no part of this type: type
PredefinedType: MAIN; NominalDiameter: 0.014 m; CrossSectionArea: 0.00015394 m2; BarLength: 1.66861 m; Material: Steel

# IfcReinforcingBarType, no part of this type: type
PredefinedType: MAIN; NominalDiameter: 0.02 m; CrossSectionArea: 0.00031416 m2; BarLength: 2.38121 m; Material: Steel

# IfcReinforcingBarType, no part of this type: type
PredefinedType: MAIN; NominalDiameter: 0.016 m; CrossSectionArea: 0.00020106 m2; BarLength: 2.38121 m; Material: Steel

# IfcReinforcingBarType, no part of this type: type
PredefinedType: MAIN; NominalDiameter: 0.016 m; CrossSectionArea: 0.00020106 m2; BarLength: 2.1183 m; Material: Steel

# IfcReinforcingBarType, no part of this type: type
PredefinedType: MAIN; NominalDiameter: 0.014 m; CrossSectionArea: 0.00015394 m2; BarLength: 2.1183 m; Material: Steel

# IfcReinforcingBarType, no part of this type: type
PredefinedType: LIGATURE; NominalDiameter: 0.008 m; CrossSectionArea: 0.000050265 m2; BarLength: 1.4868 m; Material: Steel

# IfcReinforcingBarType, no part of this type: type
PredefinedType: LIGATURE; NominalDiameter: 0.006 m; CrossSectionArea: 0.000028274 m2; BarLength: 1.49179 m; Material: Steel

# IfcReinforcingBarType, no part of this type: type
PredefinedType: MAIN; NominalDiameter: 0.016 m; CrossSectionArea: 0.00020106 m2; BarLength: 5 m; Material: Steel

# IfcReinforcingBarType, no part of this type: type
PredefinedType: MAIN; NominalDiameter: 0.016 m; CrossSectionArea: 0.00020106 m2; BarLength: 4.09309 m; Material: Steel

# IfcReinforcingBarType, no part of this type: type
PredefinedType: MAIN; NominalDiameter: 0.016 m; CrossSectionArea: 0.00020106 m2; BarLength: 4.09309 m; Material: Steel

# IfcReinforcingBarType, no part of this type: type
PredefinedType: MAIN; NominalDiameter: 0.012 m; CrossSectionArea: 0.0001131 m2; BarLength: 4.72621 m; Material: Steel

# IfcReinforcingBarType, no part of this type: type
PredefinedType: MAIN; NominalDiameter: 0.012 m; CrossSectionArea: 0.0001131 m2; BarLength: 2.61621 m; Material: Steel

# IfcReinforcingBarType, no part of this type: type
PredefinedType: MAIN; NominalDiameter: 0.012 m; CrossSectionArea: 0.0001131 m2; BarLength: 3.26121 m; Material: Steel

# IfcReinforcingBarType, no part of this type: type
PredefinedType: MAIN; NominalDiameter: 0.012 m; CrossSectionArea: 0.0001131 m2; BarLength: 3.08121 m; Material: Steel

# IfcReinforcingBarType, no part of this type: type
PredefinedType: LIGATURE; NominalDiameter: 0.008 m; CrossSectionArea: 0.000050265 m2; BarLength: 1.48681 m; Material: Steel

# IfcReinforcingBarType, no part of this type: type
PredefinedType: MAIN; NominalDiameter: 0.016 m; CrossSectionArea: 0.00020106 m2; BarLength: 9.5 m; Material: Steel

# IfcReinforcingBarType, no part of this type: type
PredefinedType: MAIN; NominalDiameter: 0.016 m; CrossSectionArea: 0.00020106 m2; BarLength: 5.49561 m; Material: Steel

# IfcReinforcingBarType, no part of this type: type
PredefinedType: MAIN; NominalDiameter: 0.016 m; CrossSectionArea: 0.00020106 m2; BarLength: 5.49561 m; Material: Steel

# IfcReinforcingBarType, no part of this type: type
PredefinedType: MAIN; NominalDiameter: 0.012 m; CrossSectionArea: 0.0001131 m2; BarLength: 3.95121 m; Material: Steel

# IfcReinforcingBarType, no part of this type: type
PredefinedType: MAIN; NominalDiameter: 0.012 m; CrossSectionArea: 0.0001131 m2; BarLength: 3.00121 m; Material: Steel

# IfcReinforcingBarType, no part of this type: type
PredefinedType: MAIN; NominalDiameter: 0.012 m; CrossSectionArea: 0.0001131 m2; BarLength: 3.74121 m; Material: Steel

# IfcReinforcingBarType, no part of this type: type
PredefinedType: MAIN; NominalDiameter: 0.016 m; CrossSectionArea: 0.00020106 m2; BarLength: 1.5 m; Material: Steel

# IfcReinforcingBarType, no part of this type: type
PredefinedType: LIGATURE; NominalDiameter: 0.006 m; CrossSectionArea: 0.000028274 m2; BarLength: 1.49179 m; Material: Steel

# IfcReinforcingBarType, no part of this type: type
PredefinedType: MAIN; NominalDiameter: 0.016 m; CrossSectionArea: 0.00020106 m2; BarLength: 3.02121 m; Material: Steel

# IfcReinforcingBarType, no part of this type: type
PredefinedType: MAIN; NominalDiameter: 0.016 m; CrossSectionArea: 0.00020106 m2; BarLength: 2.42121 m; Material: Steel

# IfcReinforcingBarType, no part of this type: type
PredefinedType: MAIN; NominalDiameter: 0.012 m; CrossSectionArea: 0.0001131 m2; BarLength: 2.26121 m; Material: Steel

# IfcReinforcingBarType, no part of this type: type
PredefinedType: LIGATURE; NominalDiameter: 0.006 m; CrossSectionArea: 0.000028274 m2; BarLength: 1.49179 m; Material: Steel

# IfcReinforcingBarType, no part of this type: type
PredefinedType: MAIN; NominalDiameter: 0.016 m; CrossSectionArea: 0.00020106 m2; BarLength: 2.26121 m; Material: Steel

# IfcReinforcingBarType, no part of this type: type
PredefinedType: MAIN; NominalDiameter: 0.012 m; CrossSectionArea: 0.0001131 m2; BarLength: 2.10121 m; Material: Steel

# IfcReinforcingBarType, no part of this type: type
PredefinedType: LIGATURE; NominalDiameter: 0.008 m; CrossSectionArea: 0.000050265 m2; BarLength: 1.08682 m; Material: Steel

# IfcReinforcingBarType, no part of this type: type
PredefinedType: MAIN; NominalDiameter: 0.016 m; CrossSectionArea: 0.00020106 m2; BarLength: 2.73121 m; Material: Steel

# IfcReinforcingBarType, no part of this type: type
PredefinedType: LIGATURE; NominalDiameter: 0.008 m; CrossSectionArea: 0.000050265 m2; BarLength: 1.18682 m; Material: Steel

# IfcReinforcingBarType, no part of this type: type
PredefinedType: LIGATURE; NominalDiameter: 0.008 m; CrossSectionArea: 0.000050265 m2; BarLength: 1.48681 m; Material: Steel

# IfcReinforcingBarType, no part of this type: type
PredefinedType: MAIN; NominalDiameter: 0.016 m; CrossSectionArea: 0.00020106 m2; BarLength: 9.49561 m; Material: Steel

# IfcReinforcingBarType, no part of this type: type
PredefinedType: MAIN; NominalDiameter: 0.018 m; CrossSectionArea: 0.00025447 m2; BarLength: 6.86121 m; Material: Steel

# IfcReinforcingBarType, no part of this type: type
PredefinedType: MAIN; NominalDiameter: 0.018 m; CrossSectionArea: 0.00025447 m2; BarLength: 9.55465 m; Material: Steel

# IfcReinforcingBarType, no part of this type: type
PredefinedType: MAIN; NominalDiameter: 0.018 m; CrossSectionArea: 0.00025447 m2; BarLength: 7.99561 m; Material: Steel

# IfcReinforcingBarType, no part of this type: type
PredefinedType: MAIN; NominalDiameter: 0.012 m; CrossSectionArea: 0.0001131 m2; BarLength: 6.80121 m; Material: Steel

# IfcReinforcingBarType, no part of this type: type
PredefinedType: MAIN; NominalDiameter: 0.014 m; CrossSectionArea: 0.00015394 m2; BarLength: 1.66268 m; Material: Steel

# IfcReinforcingBarType, no part of this type: type
PredefinedType: MAIN; NominalDiameter: 0.014 m; CrossSectionArea: 0.00015394 m2; BarLength: 2 m; Material: Steel

# IfcReinforcingBarType, no part of this type: type
PredefinedType: MAIN; NominalDiameter: 0.016 m; CrossSectionArea: 0.00020106 m2; BarLength: 2.49561 m; Material: Steel

# IfcReinforcingBarType, no part of this type: type
PredefinedType: LIGATURE; NominalDiameter: 0.008 m; CrossSectionArea: 0.000050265 m2; BarLength: 1.08682 m; Material: Steel

# IfcReinforcingBarType, no part of this type: type
PredefinedType: MAIN; NominalDiameter: 0.016 m; CrossSectionArea: 0.00020106 m2; BarLength: 2.73121 m; Material: Steel

# IfcReinforcingBarType, no part of this type: type
PredefinedType: LIGATURE; NominalDiameter: 0.006 m; CrossSectionArea: 0.000028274 m2; BarLength: 1.49179 m; Material: Steel

# IfcReinforcingBarType, no part of this type: type
PredefinedType: MAIN; NominalDiameter: 0.016 m; CrossSectionArea: 0.00020106 m2; BarLength: 2.26121 m; Material: Steel

# IfcReinforcingBarType, no part of this type: type
PredefinedType: MAIN; NominalDiameter: 0.012 m; CrossSectionArea: 0.0001131 m2; BarLength: 2.10121 m; Material: Steel

# IfcReinforcingBarType, no part of this type: type
PredefinedType: LIGATURE; NominalDiameter: 0.006 m; CrossSectionArea: 0.000028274 m2; BarLength: 1.49179 m; Material: Steel

# IfcReinforcingBarType, no part of this type: type
PredefinedType: MAIN; NominalDiameter: 0.016 m; CrossSectionArea: 0.00020106 m2; BarLength: 3.02121 m; Material: Steel

# IfcReinforcingBarType, no part of this type: type
PredefinedType: MAIN; NominalDiameter: 0.016 m; CrossSectionArea: 0.00020106 m2; BarLength: 2.42121 m; Material: Steel

# IfcReinforcingBarType, no part of this type: type
PredefinedType: MAIN; NominalDiameter: 0.012 m; CrossSectionArea: 0.0001131 m2; BarLength: 2.26121 m; Material: Steel

# IfcReinforcingBarType, no part of this type: type
PredefinedType: LIGATURE; NominalDiameter: 0.008 m; CrossSectionArea: 0.000050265 m2; BarLength: 1.48681 m; Material: Steel

# IfcReinforcingBarType, no part of this type: type
PredefinedType: MAIN; NominalDiameter: 0.016 m; CrossSectionArea: 0.00020106 m2; BarLength: 11.5214 m; Material: Steel

# IfcReinforcingBarType, no part of this type: type
PredefinedType: MAIN; NominalDiameter: 0.016 m; CrossSectionArea: 0.00020106 m2; BarLength: 7.99561 m; Material: Steel

# IfcReinforcingBarType, no part of this type: type
PredefinedType: MAIN; NominalDiameter: 0.012 m; CrossSectionArea: 0.0001131 m2; BarLength: 3.70122 m; Material: Steel

# IfcReinforcingBarType, no part of this type: type
PredefinedType: MAIN; NominalDiameter: 0.012 m; CrossSectionArea: 0.0001131 m2; BarLength: 3.66121 m; Material: Steel

# IfcReinforcingBarType, no part of this type: type
PredefinedType: MAIN; NominalDiameter: 0.012 m; CrossSectionArea: 0.0001131 m2; BarLength: 3.56121 m; Material: Steel

# IfcReinforcingBarType, no part of this type: type
PredefinedType: MAIN; NominalDiameter: 0.012 m; CrossSectionArea: 0.0001131 m2; BarLength: 3.38121 m; Material: Steel

# IfcReinforcingBarType, no part of this type: type
PredefinedType: LIGATURE; NominalDiameter: 0.008 m; CrossSectionArea: 0.000050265 m2; BarLength: 0.638887 m; Material: Steel

# IfcReinforcingBarType, no part of this type: type
PredefinedType: MAIN; NominalDiameter: 0.016 m; CrossSectionArea: 0.00020106 m2; BarLength: 3.40122 m; Material: Steel

# IfcReinforcingBarType, no part of this type: type
PredefinedType: LIGATURE; NominalDiameter: 0.008 m; CrossSectionArea: 0.000050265 m2; BarLength: 1.4868 m; Material: Steel

# IfcReinforcingBarType, no part of this type: type
PredefinedType: MAIN; NominalDiameter: 0.016 m; CrossSectionArea: 0.00020106 m2; BarLength: 4.91122 m; Material: Steel

# IfcReinforcingBarType, no part of this type: type
PredefinedType: MAIN; NominalDiameter: 0.012 m; CrossSectionArea: 0.0001131 m2; BarLength: 4.75121 m; Material: Steel

# IfcReinforcingBarType, no part of this type: type
PredefinedType: LIGATURE; NominalDiameter: 0.008 m; CrossSectionArea: 0.000050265 m2; BarLength: 1.08682 m; Material: Steel

# IfcReinforcingBarType, no part of this type: type
PredefinedType: MAIN; NominalDiameter: 0.016 m; CrossSectionArea: 0.00020106 m2; BarLength: 8.3825 m; Material: Steel

# IfcReinforcingBarType, no part of this type: type
PredefinedType: MAIN; NominalDiameter: 0.016 m; CrossSectionArea: 0.00020106 m2; BarLength: 7.49561 m; Material: Steel

# IfcReinforcingBarType, no part of this type: type
PredefinedType: MAIN; NominalDiameter: 0.016 m; CrossSectionArea: 0.00020106 m2; BarLength: 3 m; Material: Steel

# IfcReinforcingBarType, no part of this type: type
PredefinedType: LIGATURE; NominalDiameter: 0.006 m; CrossSectionArea: 0.000028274 m2; BarLength: 1.49179 m; Material: Steel

# IfcReinforcingBarType, no part of this type: type
PredefinedType: MAIN; NominalDiameter: 0.016 m; CrossSectionArea: 0.00020106 m2; BarLength: 2.79121 m; Material: Steel

# IfcReinforcingBarType, no part of this type: type
PredefinedType: MAIN; NominalDiameter: 0.012 m; CrossSectionArea: 0.0001131 m2; BarLength: 2.63121 m; Material: Steel

# IfcReinforcingBarType, no part of this type: type
PredefinedType: LIGATURE; NominalDiameter: 0.006 m; CrossSectionArea: 0.000028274 m2; BarLength: 1.49179 m; Material: Steel

# IfcReinforcingBarType, no part of this type: type
PredefinedType: MAIN; NominalDiameter: 0.016 m; CrossSectionArea: 0.00020106 m2; BarLength: 2.79121 m; Material: Steel

# IfcReinforcingBarType, no part of this type: type
PredefinedType: MAIN; NominalDiameter: 0.012 m; CrossSectionArea: 0.0001131 m2; BarLength: 2.63121 m; Material: Steel

# IfcReinforcingBarType, no part of this type: type
PredefinedType: LIGATURE; NominalDiameter: 0.008 m; CrossSectionArea: 0.000050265 m2; BarLength: 1.08682 m; Material: Steel

# IfcReinforcingBarType, no part of this type: type
PredefinedType: MAIN; NominalDiameter: 0.016 m; CrossSectionArea: 0.00020106 m2; BarLength: 8.3825 m; Material: Steel

# IfcReinforcingBarType, no part of this type: type
PredefinedType: MAIN; NominalDiameter: 0.016 m; CrossSectionArea: 0.00020106 m2; BarLength: 7.49561 m; Material: Steel

# IfcReinforcingBarType, no part of this type: type
PredefinedType: MAIN; NominalDiameter: 0.016 m; CrossSectionArea: 0.00020106 m2; BarLength: 3 m; Material: Steel

# IfcReinforcingBarType, no part of this type: type
PredefinedType: LIGATURE; NominalDiameter: 0.006 m; CrossSectionArea: 0.000028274 m2; BarLength: 1.49179 m; Material: Steel

# IfcReinforcingBarType, no part of this type: type
PredefinedType: MAIN; NominalDiameter: 0.016 m; CrossSectionArea: 0.00020106 m2; BarLength: 10.1607 m; Material: Steel

# IfcReinforcingBarType, no part of this type: type
PredefinedType: MAIN; NominalDiameter: 0.016 m; CrossSectionArea: 0.00020106 m2; BarLength: 10.1606 m; Material: Steel

# IfcReinforcingBarType, no part of this type: type
PredefinedType: MAIN; NominalDiameter: 0.012 m; CrossSectionArea: 0.0001131 m2; BarLength: 3.64621 m; Material: Steel

# IfcReinforcingBarType, no part of this type: type
PredefinedType: MAIN; NominalDiameter: 0.012 m; CrossSectionArea: 0.0001131 m2; BarLength: 3.53441 m; Material: Steel

# IfcReinforcingBarType, no part of this type: type
PredefinedType: MAIN; NominalDiameter: 0.012 m; CrossSectionArea: 0.0001131 m2; BarLength: 3.51718 m; Material: Steel

# IfcReinforcingBarType, no part of this type: type
PredefinedType: LIGATURE; NominalDiameter: 0.006 m; CrossSectionArea: 0.000028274 m2; BarLength: 1.49179 m; Material: Steel

# IfcReinforcingBarType, no part of this type: type
PredefinedType: MAIN; NominalDiameter: 0.016 m; CrossSectionArea: 0.00020106 m2; BarLength: 10.158 m; Material: Steel

# IfcReinforcingBarType, no part of this type: type
PredefinedType: MAIN; NominalDiameter: 0.016 m; CrossSectionArea: 0.00020106 m2; BarLength: 10.158 m; Material: Steel

# IfcReinforcingBarType, no part of this type: type
PredefinedType: MAIN; NominalDiameter: 0.012 m; CrossSectionArea: 0.0001131 m2; BarLength: 3.51272 m; Material: Steel

# IfcReinforcingBarType, no part of this type: type
PredefinedType: MAIN; NominalDiameter: 0.012 m; CrossSectionArea: 0.0001131 m2; BarLength: 3.53222 m; Material: Steel

# IfcReinforcingBarType, no part of this type: type
PredefinedType: MAIN; NominalDiameter: 0.012 m; CrossSectionArea: 0.0001131 m2; BarLength: 3.64515 m; Material: Steel

# IfcReinforcingBarType, no part of this type: type
PredefinedType: LIGATURE; NominalDiameter: 0.008 m; CrossSectionArea: 0.000050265 m2; BarLength: 0.986829 m; Material: Steel

# IfcReinforcingBarType, no part of this type: type
PredefinedType: MAIN; NominalDiameter: 0.016 m; CrossSectionArea: 0.00020106 m2; BarLength: 3.62988 m; Material: Steel

# IfcReinforcingBarType, no part of this type: type
PredefinedType: MAIN; NominalDiameter: 0.016 m; CrossSectionArea: 0.00020106 m2; BarLength: 3.64834 m; Material: Steel

# IfcReinforcingBarType, no part of this type: type
PredefinedType: LIGATURE; NominalDiameter: 0.008 m; CrossSectionArea: 0.000050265 m2; BarLength: 1.48681 m; Material: Steel

# IfcReinforcingBarType, no part of this type: type
PredefinedType: LIGATURE; NominalDiameter: 0.006 m; CrossSectionArea: 0.000028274 m2; BarLength: 1.49179 m; Material: Steel

# IfcReinforcingBarType, no part of this type: type
PredefinedType: MAIN; NominalDiameter: 0.018 m; CrossSectionArea: 0.00025447 m2; BarLength: 10.0934 m; Material: Steel

# IfcReinforcingBarType, no part of this type: type
PredefinedType: MAIN; NominalDiameter: 0.014 m; CrossSectionArea: 0.00015394 m2; BarLength: 10.0934 m; Material: Steel

# IfcReinforcingBarType, no part of this type: type
PredefinedType: MAIN; NominalDiameter: 0.018 m; CrossSectionArea: 0.00025447 m2; BarLength: 10.0934 m; Material: Steel

# IfcReinforcingBarType, no part of this type: type
PredefinedType: MAIN; NominalDiameter: 0.014 m; CrossSectionArea: 0.00015394 m2; BarLength: 10.0934 m; Material: Steel

# IfcReinforcingBarType, no part of this type: type
PredefinedType: MAIN; NominalDiameter: 0.016 m; CrossSectionArea: 0.00020106 m2; BarLength: 8.41509 m; Material: Steel

# IfcReinforcingBarType, no part of this type: type
PredefinedType: MAIN; NominalDiameter: 0.016 m; CrossSectionArea: 0.00020106 m2; BarLength: 8.41501 m; Material: Steel
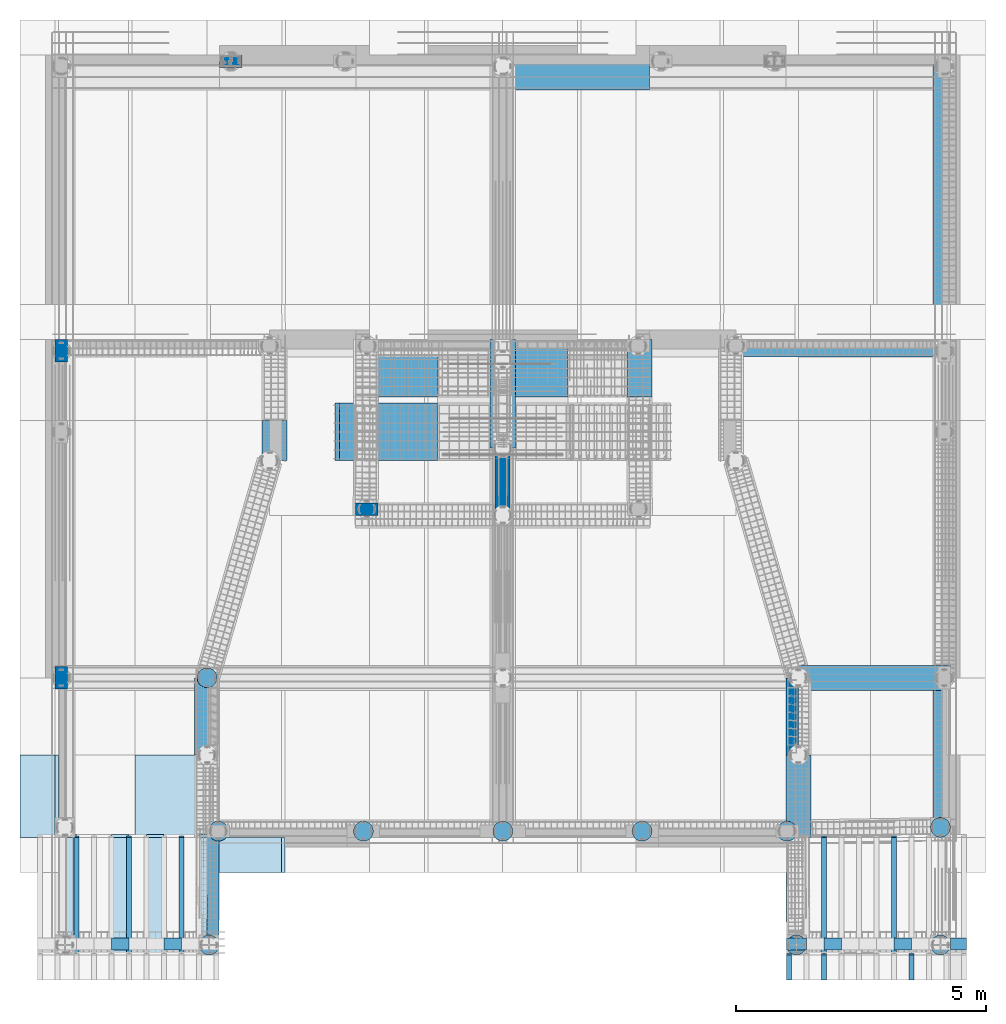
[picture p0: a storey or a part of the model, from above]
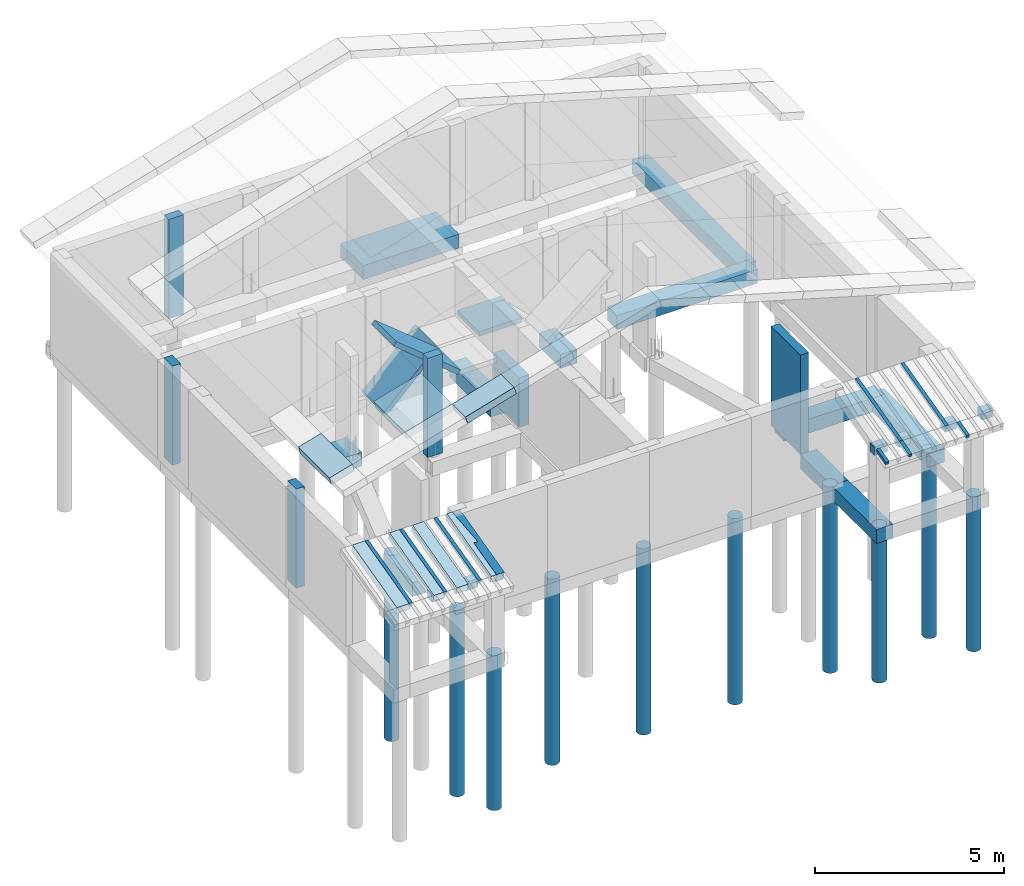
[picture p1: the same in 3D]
Properties of the parts of a building model (IFC4), part 3 of 5

# IfcReinforcingBarType, no part of this type: type
PredefinedType: MAIN; NominalDiameter: 0.018 m; CrossSectionArea: 0.00025447 m2; BarLength: 5.19254 m; Material: Steel

# IfcReinforcingBarType, no part of this type: type
PredefinedType: MAIN; NominalDiameter: 0.014 m; CrossSectionArea: 0.00015394 m2; BarLength: 1.99783 m; Material: Steel

# IfcReinforcingBarType, no part of this type: type
PredefinedType: MAIN; NominalDiameter: 0.014 m; CrossSectionArea: 0.00015394 m2; BarLength: 1.99782 m; Material: Steel

# IfcReinforcingBarType, no part of this type: type
PredefinedType: MAIN; NominalDiameter: 0.012 m; CrossSectionArea: 0.0001131 m2; BarLength: 9.35591 m; Material: Steel

# IfcReinforcingBarType, no part of this type: type
PredefinedType: MAIN; NominalDiameter: 0.012 m; CrossSectionArea: 0.0001131 m2; BarLength: 9.35591 m; Material: Steel

# IfcReinforcingBarType, no part of this type: type
PredefinedType: LIGATURE; NominalDiameter: 0.008 m; CrossSectionArea: 0.000050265 m2; BarLength: 1.4868 m; Material: Steel

# IfcReinforcingBarType, no part of this type: type
PredefinedType: LIGATURE; NominalDiameter: 0.006 m; CrossSectionArea: 0.000028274 m2; BarLength: 1.49179 m; Material: Steel

# IfcReinforcingBarType, no part of this type: type
PredefinedType: MAIN; NominalDiameter: 0.016 m; CrossSectionArea: 0.00020106 m2; BarLength: 5.55674 m; Material: Steel

# IfcReinforcingBarType, no part of this type: type
PredefinedType: MAIN; NominalDiameter: 0.014 m; CrossSectionArea: 0.00015394 m2; BarLength: 5.49118 m; Material: Steel

# IfcReinforcingBarType, no part of this type: type
PredefinedType: MAIN; NominalDiameter: 0.014 m; CrossSectionArea: 0.00015394 m2; BarLength: 3.34481 m; Material: Steel

# IfcReinforcingBarType, no part of this type: type
PredefinedType: MAIN; NominalDiameter: 0.014 m; CrossSectionArea: 0.00015394 m2; BarLength: 2.33303 m; Material: Steel

# IfcReinforcingBarType, no part of this type: type
PredefinedType: MAIN; NominalDiameter: 0.014 m; CrossSectionArea: 0.00015394 m2; BarLength: 1.65213 m; Material: Steel

# IfcReinforcingBarType, no part of this type: type
PredefinedType: MAIN; NominalDiameter: 0.016 m; CrossSectionArea: 0.00020106 m2; BarLength: 0.993265 m; Material: Steel

# IfcReinforcingBarType, no part of this type: type
PredefinedType: MAIN; NominalDiameter: 0.016 m; CrossSectionArea: 0.00020106 m2; BarLength: 0.992515 m; Material: Steel

# IfcReinforcingBarType, no part of this type: type
PredefinedType: MAIN; NominalDiameter: 0.016 m; CrossSectionArea: 0.00020106 m2; BarLength: 3.87711 m; Material: Steel

# IfcReinforcingBarType, no part of this type: type
PredefinedType: MAIN; NominalDiameter: 0.016 m; CrossSectionArea: 0.00020106 m2; BarLength: 3.4781 m; Material: Steel

# IfcReinforcingBarType, no part of this type: type
PredefinedType: MAIN; NominalDiameter: 0.016 m; CrossSectionArea: 0.00020106 m2; BarLength: 3.47813 m; Material: Steel

# IfcReinforcingBarType, no part of this type: type
PredefinedType: MAIN; NominalDiameter: 0.016 m; CrossSectionArea: 0.00020106 m2; BarLength: 1.72642 m; Material: Steel

# IfcReinforcingBarType, no part of this type: type
PredefinedType: MAIN; NominalDiameter: 0.016 m; CrossSectionArea: 0.00020106 m2; BarLength: 1.72642 m; Material: Steel

# IfcReinforcingBarType, no part of this type: type
PredefinedType: MAIN; NominalDiameter: 0.016 m; CrossSectionArea: 0.00020106 m2; BarLength: 1.00183 m; Material: Steel

# IfcReinforcingBarType, no part of this type: type
PredefinedType: MAIN; NominalDiameter: 0.016 m; CrossSectionArea: 0.00020106 m2; BarLength: 1.00109 m; Material: Steel

# IfcReinforcingBarType, no part of this type: type
PredefinedType: MAIN; NominalDiameter: 0.012 m; CrossSectionArea: 0.0001131 m2; BarLength: 2.13725 m; Material: Steel

# IfcReinforcingBarType, no part of this type: type
PredefinedType: MAIN; NominalDiameter: 0.012 m; CrossSectionArea: 0.0001131 m2; BarLength: 3.15576 m; Material: Steel

# IfcReinforcingBarType, no part of this type: type
PredefinedType: MAIN; NominalDiameter: 0.012 m; CrossSectionArea: 0.0001131 m2; BarLength: 3.15671 m; Material: Steel

# IfcReinforcingBarType, no part of this type: type
PredefinedType: LIGATURE; NominalDiameter: 0.008 m; CrossSectionArea: 0.000050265 m2; BarLength: 1.4868 m; Material: Steel

# IfcReinforcingBarType, no part of this type: type
PredefinedType: LIGATURE; NominalDiameter: 0.006 m; CrossSectionArea: 0.000028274 m2; BarLength: 1.4918 m; Material: Steel

# IfcReinforcingBarType, no part of this type: type
PredefinedType: MAIN; NominalDiameter: 0.016 m; CrossSectionArea: 0.00020106 m2; BarLength: 5.09853 m; Material: Steel

# IfcReinforcingBarType, no part of this type: type
PredefinedType: MAIN; NominalDiameter: 0.016 m; CrossSectionArea: 0.00020106 m2; BarLength: 5.09866 m; Material: Steel

# IfcReinforcingBarType, no part of this type: type
PredefinedType: MAIN; NominalDiameter: 0.012 m; CrossSectionArea: 0.0001131 m2; BarLength: 4.60911 m; Material: Steel

# IfcReinforcingBarType, no part of this type: type
PredefinedType: LIGATURE; NominalDiameter: 0.006 m; CrossSectionArea: 0.000028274 m2; BarLength: 1.49179 m; Material: Steel

# IfcReinforcingBarType, no part of this type: type
PredefinedType: LIGATURE; NominalDiameter: 0.008 m; CrossSectionArea: 0.000050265 m2; BarLength: 1.48681 m; Material: Steel

# IfcReinforcingBarType, no part of this type: type
PredefinedType: MAIN; NominalDiameter: 0.016 m; CrossSectionArea: 0.00020106 m2; BarLength: 7.20525 m; Material: Steel

# IfcReinforcingBarType, no part of this type: type
PredefinedType: MAIN; NominalDiameter: 0.014 m; CrossSectionArea: 0.00015394 m2; BarLength: 7.07477 m; Material: Steel

# IfcReinforcingBarType, no part of this type: type
PredefinedType: MAIN; NominalDiameter: 0.014 m; CrossSectionArea: 0.00015394 m2; BarLength: 3.34953 m; Material: Steel

# IfcReinforcingBarType, no part of this type: type
PredefinedType: MAIN; NominalDiameter: 0.014 m; CrossSectionArea: 0.00015394 m2; BarLength: 3.24511 m; Material: Steel

# IfcReinforcingBarType, no part of this type: type
PredefinedType: MAIN; NominalDiameter: 0.016 m; CrossSectionArea: 0.00020106 m2; BarLength: 3.87253 m; Material: Steel

# IfcReinforcingBarType, no part of this type: type
PredefinedType: MAIN; NominalDiameter: 0.016 m; CrossSectionArea: 0.00020106 m2; BarLength: 3.87122 m; Material: Steel

# IfcReinforcingBarType, no part of this type: type
PredefinedType: MAIN; NominalDiameter: 0.014 m; CrossSectionArea: 0.00015394 m2; BarLength: 2.32783 m; Material: Steel

# IfcReinforcingBarType, no part of this type: type
PredefinedType: MAIN; NominalDiameter: 0.016 m; CrossSectionArea: 0.00020106 m2; BarLength: 3.8667 m; Material: Steel

# IfcReinforcingBarType, no part of this type: type
PredefinedType: MAIN; NominalDiameter: 0.016 m; CrossSectionArea: 0.00020106 m2; BarLength: 3.48095 m; Material: Steel

# IfcReinforcingBarType, no part of this type: type
PredefinedType: MAIN; NominalDiameter: 0.016 m; CrossSectionArea: 0.00020106 m2; BarLength: 3.48104 m; Material: Steel

# IfcReinforcingBarType, no part of this type: type
PredefinedType: MAIN; NominalDiameter: 0.016 m; CrossSectionArea: 0.00020106 m2; BarLength: 3.37702 m; Material: Steel

# IfcReinforcingBarType, no part of this type: type
PredefinedType: MAIN; NominalDiameter: 0.016 m; CrossSectionArea: 0.00020106 m2; BarLength: 3.37684 m; Material: Steel

# IfcReinforcingBarType, no part of this type: type
PredefinedType: MAIN; NominalDiameter: 0.016 m; CrossSectionArea: 0.00020106 m2; BarLength: 3.87846 m; Material: Steel

# IfcReinforcingBarType, no part of this type: type
PredefinedType: MAIN; NominalDiameter: 0.016 m; CrossSectionArea: 0.00020106 m2; BarLength: 3.87714 m; Material: Steel

# IfcReinforcingBarType, no part of this type: type
PredefinedType: MAIN; NominalDiameter: 0.012 m; CrossSectionArea: 0.0001131 m2; BarLength: 4.58304 m; Material: Steel

# IfcReinforcingBarType, no part of this type: type
PredefinedType: MAIN; NominalDiameter: 0.012 m; CrossSectionArea: 0.0001131 m2; BarLength: 2.38428 m; Material: Steel

# IfcReinforcingBarType, no part of this type: type
PredefinedType: MAIN; NominalDiameter: 0.012 m; CrossSectionArea: 0.0001131 m2; BarLength: 3.08571 m; Material: Steel

# IfcReinforcingBarType, no part of this type: type
PredefinedType: MAIN; NominalDiameter: 0.012 m; CrossSectionArea: 0.0001131 m2; BarLength: 3.08661 m; Material: Steel

# IfcReinforcingBarType, no part of this type: type
PredefinedType: MAIN; NominalDiameter: 0.012 m; CrossSectionArea: 0.0001131 m2; BarLength: 4.57937 m; Material: Steel

# IfcReinforcingBarType, no part of this type: type
PredefinedType: LIGATURE; NominalDiameter: 0.006 m; CrossSectionArea: 0.000028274 m2; BarLength: 1.49179 m; Material: Steel

# IfcReinforcingBarType, no part of this type: type
PredefinedType: LIGATURE; NominalDiameter: 0.008 m; CrossSectionArea: 0.000050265 m2; BarLength: 1.48681 m; Material: Steel

# IfcReinforcingBarType, no part of this type: type
PredefinedType: MAIN; NominalDiameter: 0.016 m; CrossSectionArea: 0.00020106 m2; BarLength: 5.64359 m; Material: Steel

# IfcReinforcingBarType, no part of this type: type
PredefinedType: MAIN; NominalDiameter: 0.016 m; CrossSectionArea: 0.00020106 m2; BarLength: 4.00717 m; Material: Steel

# IfcReinforcingBarType, no part of this type: type
PredefinedType: MAIN; NominalDiameter: 0.016 m; CrossSectionArea: 0.00020106 m2; BarLength: 5.43237 m; Material: Steel

# IfcReinforcingBarType, no part of this type: type
PredefinedType: MAIN; NominalDiameter: 0.016 m; CrossSectionArea: 0.00020106 m2; BarLength: 5.43208 m; Material: Steel

# IfcReinforcingBarType, no part of this type: type
PredefinedType: MAIN; NominalDiameter: 0.016 m; CrossSectionArea: 0.00020106 m2; BarLength: 4.29567 m; Material: Steel

# IfcReinforcingBarType, no part of this type: type
PredefinedType: MAIN; NominalDiameter: 0.016 m; CrossSectionArea: 0.00020106 m2; BarLength: 7.24561 m; Material: Steel

# IfcReinforcingBarType, no part of this type: type
PredefinedType: MAIN; NominalDiameter: 0.016 m; CrossSectionArea: 0.00020106 m2; BarLength: 4.04365 m; Material: Steel

# IfcReinforcingBarType, no part of this type: type
PredefinedType: MAIN; NominalDiameter: 0.016 m; CrossSectionArea: 0.00020106 m2; BarLength: 5.43831 m; Material: Steel

# IfcReinforcingBarType, no part of this type: type
PredefinedType: MAIN; NominalDiameter: 0.016 m; CrossSectionArea: 0.00020106 m2; BarLength: 5.43803 m; Material: Steel

# IfcReinforcingBarType, no part of this type: type
PredefinedType: MAIN; NominalDiameter: 0.012 m; CrossSectionArea: 0.0001131 m2; BarLength: 6.21035 m; Material: Steel

# IfcReinforcingBarType, no part of this type: type
PredefinedType: MAIN; NominalDiameter: 0.012 m; CrossSectionArea: 0.0001131 m2; BarLength: 3.55503 m; Material: Steel

# IfcReinforcingBarType, no part of this type: type
PredefinedType: MAIN; NominalDiameter: 0.012 m; CrossSectionArea: 0.0001131 m2; BarLength: 3.55503 m; Material: Steel

# IfcReinforcingBarType, no part of this type: type
PredefinedType: MAIN; NominalDiameter: 0.012 m; CrossSectionArea: 0.0001131 m2; BarLength: 6.20481 m; Material: Steel

# IfcReinforcingBarType, no part of this type: type
PredefinedType: LIGATURE; NominalDiameter: 0.006 m; CrossSectionArea: 0.000028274 m2; BarLength: 1.49179 m; Material: Steel

# IfcReinforcingBarType, no part of this type: type
PredefinedType: MAIN; NominalDiameter: 0.016 m; CrossSectionArea: 0.00020106 m2; BarLength: 2.26121 m; Material: Steel

# IfcReinforcingBarType, no part of this type: type
PredefinedType: MAIN; NominalDiameter: 0.012 m; CrossSectionArea: 0.0001131 m2; BarLength: 2.10121 m; Material: Steel

# IfcReinforcingBarType, no part of this type: type
PredefinedType: LIGATURE; NominalDiameter: 0.006 m; CrossSectionArea: 0.000028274 m2; BarLength: 1.49179 m; Material: Steel

# IfcReinforcingBarType, no part of this type: type
PredefinedType: MAIN; NominalDiameter: 0.016 m; CrossSectionArea: 0.00020106 m2; BarLength: 2.26121 m; Material: Steel

# IfcReinforcingBarType, no part of this type: type
PredefinedType: MAIN; NominalDiameter: 0.012 m; CrossSectionArea: 0.0001131 m2; BarLength: 2.10121 m; Material: Steel

# IfcReinforcingBarType, no part of this type: type
PredefinedType: LIGATURE; NominalDiameter: 0.008 m; CrossSectionArea: 0.000050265 m2; BarLength: 0.986831 m; Material: Steel

# IfcReinforcingBarType, no part of this type: type
PredefinedType: MAIN; NominalDiameter: 0.016 m; CrossSectionArea: 0.00020106 m2; BarLength: 3.62989 m; Material: Steel

# IfcReinforcingBarType, no part of this type: type
PredefinedType: MAIN; NominalDiameter: 0.016 m; CrossSectionArea: 0.00020106 m2; BarLength: 3.64834 m; Material: Steel

# IfcReinforcingBarType, no part of this type: type
PredefinedType: LIGATURE; NominalDiameter: 0.006 m; CrossSectionArea: 0.000028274 m2; BarLength: 1.4918 m; Material: Steel

# IfcReinforcingBarType, no part of this type: type
PredefinedType: LIGATURE; NominalDiameter: 0.008 m; CrossSectionArea: 0.000050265 m2; BarLength: 1.48681 m; Material: Steel

# IfcReinforcingBarType, no part of this type: type
PredefinedType: MAIN; NominalDiameter: 0.016 m; CrossSectionArea: 0.00020106 m2; BarLength: 5.09853 m; Material: Steel

# IfcReinforcingBarType, no part of this type: type
PredefinedType: MAIN; NominalDiameter: 0.016 m; CrossSectionArea: 0.00020106 m2; BarLength: 5.09866 m; Material: Steel

# IfcReinforcingBarType, no part of this type: type
PredefinedType: MAIN; NominalDiameter: 0.012 m; CrossSectionArea: 0.0001131 m2; BarLength: 4.60911 m; Material: Steel

# IfcReinforcingBarType, no part of this type: type
PredefinedType: LIGATURE; NominalDiameter: 0.008 m; CrossSectionArea: 0.000050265 m2; BarLength: 1.4868 m; Material: Steel

# IfcReinforcingBarType, no part of this type: type
PredefinedType: LIGATURE; NominalDiameter: 0.006 m; CrossSectionArea: 0.000028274 m2; BarLength: 1.4918 m; Material: Steel

# IfcReinforcingBarType, no part of this type: type
PredefinedType: MAIN; NominalDiameter: 0.016 m; CrossSectionArea: 0.00020106 m2; BarLength: 7.20524 m; Material: Steel

# IfcReinforcingBarType, no part of this type: type
PredefinedType: MAIN; NominalDiameter: 0.014 m; CrossSectionArea: 0.00015394 m2; BarLength: 7.075 m; Material: Steel

# IfcReinforcingBarType, no part of this type: type
PredefinedType: MAIN; NominalDiameter: 0.014 m; CrossSectionArea: 0.00015394 m2; BarLength: 3.34953 m; Material: Steel

# IfcReinforcingBarType, no part of this type: type
PredefinedType: MAIN; NominalDiameter: 0.014 m; CrossSectionArea: 0.00015394 m2; BarLength: 3.24535 m; Material: Steel

# IfcReinforcingBarType, no part of this type: type
PredefinedType: MAIN; NominalDiameter: 0.016 m; CrossSectionArea: 0.00020106 m2; BarLength: 3.87262 m; Material: Steel

# IfcReinforcingBarType, no part of this type: type
PredefinedType: MAIN; NominalDiameter: 0.016 m; CrossSectionArea: 0.00020106 m2; BarLength: 3.87124 m; Material: Steel

# IfcReinforcingBarType, no part of this type: type
PredefinedType: MAIN; NominalDiameter: 0.014 m; CrossSectionArea: 0.00015394 m2; BarLength: 2.32783 m; Material: Steel

# IfcReinforcingBarType, no part of this type: type
PredefinedType: MAIN; NominalDiameter: 0.016 m; CrossSectionArea: 0.00020106 m2; BarLength: 3.8667 m; Material: Steel

# IfcReinforcingBarType, no part of this type: type
PredefinedType: MAIN; NominalDiameter: 0.016 m; CrossSectionArea: 0.00020106 m2; BarLength: 3.47895 m; Material: Steel

# IfcReinforcingBarType, no part of this type: type
PredefinedType: MAIN; NominalDiameter: 0.016 m; CrossSectionArea: 0.00020106 m2; BarLength: 3.47892 m; Material: Steel

# IfcReinforcingBarType, no part of this type: type
PredefinedType: MAIN; NominalDiameter: 0.016 m; CrossSectionArea: 0.00020106 m2; BarLength: 3.37058 m; Material: Steel

# IfcReinforcingBarType, no part of this type: type
PredefinedType: MAIN; NominalDiameter: 0.016 m; CrossSectionArea: 0.00020106 m2; BarLength: 3.36925 m; Material: Steel

# IfcReinforcingBarType, no part of this type: type
PredefinedType: MAIN; NominalDiameter: 0.016 m; CrossSectionArea: 0.00020106 m2; BarLength: 3.87848 m; Material: Steel

# IfcReinforcingBarType, no part of this type: type
PredefinedType: MAIN; NominalDiameter: 0.016 m; CrossSectionArea: 0.00020106 m2; BarLength: 3.87712 m; Material: Steel

# IfcReinforcingBarType, no part of this type: type
PredefinedType: MAIN; NominalDiameter: 0.012 m; CrossSectionArea: 0.0001131 m2; BarLength: 4.58304 m; Material: Steel

# IfcReinforcingBarType, no part of this type: type
PredefinedType: MAIN; NominalDiameter: 0.012 m; CrossSectionArea: 0.0001131 m2; BarLength: 2.38428 m; Material: Steel

# IfcReinforcingBarType, no part of this type: type
PredefinedType: MAIN; NominalDiameter: 0.012 m; CrossSectionArea: 0.0001131 m2; BarLength: 3.14535 m; Material: Steel

# IfcReinforcingBarType, no part of this type: type
PredefinedType: MAIN; NominalDiameter: 0.012 m; CrossSectionArea: 0.0001131 m2; BarLength: 3.14629 m; Material: Steel

# IfcReinforcingBarType, no part of this type: type
PredefinedType: MAIN; NominalDiameter: 0.012 m; CrossSectionArea: 0.0001131 m2; BarLength: 4.57863 m; Material: Steel

# IfcReinforcingBarType, no part of this type: type
PredefinedType: LIGATURE; NominalDiameter: 0.008 m; CrossSectionArea: 0.000050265 m2; BarLength: 1.08682 m; Material: Steel

# IfcReinforcingBarType, no part of this type: type
PredefinedType: MAIN; NominalDiameter: 0.016 m; CrossSectionArea: 0.00020106 m2; BarLength: 10.4012 m; Material: Steel

# IfcReinforcingBarType, no part of this type: type
PredefinedType: LIGATURE; NominalDiameter: 0.006 m; CrossSectionArea: 0.000028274 m2; BarLength: 1.49179 m; Material: Steel

# IfcReinforcingBarType, no part of this type: type
PredefinedType: MAIN; NominalDiameter: 0.016 m; CrossSectionArea: 0.00020106 m2; BarLength: 2.42122 m; Material: Steel

# IfcReinforcingBarType, no part of this type: type
PredefinedType: MAIN; NominalDiameter: 0.012 m; CrossSectionArea: 0.0001131 m2; BarLength: 2.26121 m; Material: Steel

# IfcReinforcingBarType, no part of this type: type
PredefinedType: LIGATURE; NominalDiameter: 0.006 m; CrossSectionArea: 0.000028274 m2; BarLength: 1.49179 m; Material: Steel

# IfcReinforcingBarType, no part of this type: type
PredefinedType: MAIN; NominalDiameter: 0.016 m; CrossSectionArea: 0.00020106 m2; BarLength: 2.79121 m; Material: Steel

# IfcReinforcingBarType, no part of this type: type
PredefinedType: MAIN; NominalDiameter: 0.012 m; CrossSectionArea: 0.0001131 m2; BarLength: 2.63121 m; Material: Steel

# IfcReinforcingBarType, no part of this type: type
PredefinedType: LIGATURE; NominalDiameter: 0.008 m; CrossSectionArea: 0.000050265 m2; BarLength: 1.18682 m; Material: Steel

# IfcReinforcingBarType, no part of this type: type
PredefinedType: MAIN; NominalDiameter: 0.016 m; CrossSectionArea: 0.00020106 m2; BarLength: 10.2612 m; Material: Steel

# IfcReinforcingBarType, no part of this type: type
PredefinedType: MAIN; NominalDiameter: 0.018 m; CrossSectionArea: 0.00025447 m2; BarLength: 10.2612 m; Material: Steel

# IfcReinforcingBarType, no part of this type: type
PredefinedType: MAIN; NominalDiameter: 0.014 m; CrossSectionArea: 0.00015394 m2; BarLength: 3 m; Material: Steel

# IfcReinforcingBarType, no part of this type: type
PredefinedType: MAIN; NominalDiameter: 0.014 m; CrossSectionArea: 0.00015394 m2; BarLength: 2 m; Material: Steel

# IfcReinforcingBarType, no part of this type: type
PredefinedType: LIGATURE; NominalDiameter: 0.006 m; CrossSectionArea: 0.000028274 m2; BarLength: 1.49179 m; Material: Steel

# IfcReinforcingBarType, no part of this type: type
PredefinedType: MAIN; NominalDiameter: 0.016 m; CrossSectionArea: 0.00020106 m2; BarLength: 2.79121 m; Material: Steel

# IfcReinforcingBarType, no part of this type: type
PredefinedType: MAIN; NominalDiameter: 0.012 m; CrossSectionArea: 0.0001131 m2; BarLength: 2.63121 m; Material: Steel

# IfcReinforcingBarType, no part of this type: type
PredefinedType: LIGATURE; NominalDiameter: 0.006 m; CrossSectionArea: 0.000028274 m2; BarLength: 1.49179 m; Material: Steel

# IfcReinforcingBarType, no part of this type: type
PredefinedType: MAIN; NominalDiameter: 0.016 m; CrossSectionArea: 0.00020106 m2; BarLength: 2.42122 m; Material: Steel

# IfcReinforcingBarType, no part of this type: type
PredefinedType: MAIN; NominalDiameter: 0.012 m; CrossSectionArea: 0.0001131 m2; BarLength: 2.26121 m; Material: Steel

# IfcReinforcingBarType, no part of this type: type
PredefinedType: LIGATURE; NominalDiameter: 0.008 m; CrossSectionArea: 0.000050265 m2; BarLength: 1.08682 m; Material: Steel

# IfcReinforcingBarType, no part of this type: type
PredefinedType: MAIN; NominalDiameter: 0.016 m; CrossSectionArea: 0.00020106 m2; BarLength: 10.4012 m; Material: Steel

# IfcReinforcingBarType, no part of this type: type
PredefinedType: LIGATURE; NominalDiameter: 0.008 m; CrossSectionArea: 0.000050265 m2; BarLength: 1.08682 m; Material: Steel

# IfcReinforcingBarType, no part of this type: type
PredefinedType: MAIN; NominalDiameter: 0.016 m; CrossSectionArea: 0.00020106 m2; BarLength: 6.45121 m; Material: Steel

# IfcReinforcingBarType, no part of this type: type
PredefinedType: LIGATURE; NominalDiameter: 0.008 m; CrossSectionArea: 0.000050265 m2; BarLength: 1.18682 m; Material: Steel

# IfcReinforcingBarType, no part of this type: type
PredefinedType: MAIN; NominalDiameter: 0.016 m; CrossSectionArea: 0.00020106 m2; BarLength: 6.80121 m; Material: Steel

# IfcReinforcingBarType, no part of this type: type
PredefinedType: LIGATURE; NominalDiameter: 0.008 m; CrossSectionArea: 0.000050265 m2; BarLength: 1.08682 m; Material: Steel

# IfcReinforcingBarType, no part of this type: type
PredefinedType: MAIN; NominalDiameter: 0.016 m; CrossSectionArea: 0.00020106 m2; BarLength: 6.45121 m; Material: Steel

# IfcReinforcingBarType, no part of this type: type
PredefinedType: LIGATURE; NominalDiameter: 0.008 m; CrossSectionArea: 0.000050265 m2; BarLength: 1.8868 m; Material: Steel

# IfcReinforcingBarType, no part of this type: type
PredefinedType: MAIN; NominalDiameter: 0.016 m; CrossSectionArea: 0.00020106 m2; BarLength: 4.13619 m; Material: Steel

# IfcReinforcingBarType, no part of this type: type
PredefinedType: MAIN; NominalDiameter: 0.016 m; CrossSectionArea: 0.00020106 m2; BarLength: 4.00663 m; Material: Steel

# IfcReinforcingBarType, no part of this type: type
PredefinedType: MAIN; NominalDiameter: 0.016 m; CrossSectionArea: 0.00020106 m2; BarLength: 3.89437 m; Material: Steel

# IfcReinforcingBarType, no part of this type: type
PredefinedType: MAIN; NominalDiameter: 0.016 m; CrossSectionArea: 0.00020106 m2; BarLength: 3.83663 m; Material: Steel

# IfcReinforcingBarType, no part of this type: type
PredefinedType: MAIN; NominalDiameter: 0.016 m; CrossSectionArea: 0.00020106 m2; BarLength: 2.48912 m; Material: Steel

# IfcReinforcingBarType, no part of this type: type
PredefinedType: MAIN; NominalDiameter: 0.016 m; CrossSectionArea: 0.00020106 m2; BarLength: 2.52392 m; Material: Steel

# IfcReinforcingBarType, no part of this type: type
PredefinedType: LIGATURE; NominalDiameter: 0.008 m; CrossSectionArea: 0.000050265 m2; BarLength: 1.8868 m; Material: Steel

# IfcReinforcingBarType, no part of this type: type
PredefinedType: MAIN; NominalDiameter: 0.016 m; CrossSectionArea: 0.00020106 m2; BarLength: 6.83663 m; Material: Steel

# IfcReinforcingBarType, no part of this type: type
PredefinedType: MAIN; NominalDiameter: 0.016 m; CrossSectionArea: 0.00020106 m2; BarLength: 5.52664 m; Material: Steel

# IfcReinforcingBarType, no part of this type: type
PredefinedType: MAIN; NominalDiameter: 0.016 m; CrossSectionArea: 0.00020106 m2; BarLength: 2.44392 m; Material: Steel

# IfcReinforcingBarType, no part of this type: type
PredefinedType: MAIN; NominalDiameter: 0.016 m; CrossSectionArea: 0.00020106 m2; BarLength: 2.39392 m; Material: Steel

# IfcReinforcingBarType, no part of this type: type
PredefinedType: LIGATURE; NominalDiameter: 0.008 m; CrossSectionArea: 0.000050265 m2; BarLength: 1.8868 m; Material: Steel

# IfcReinforcingBarType, no part of this type: type
PredefinedType: MAIN; NominalDiameter: 0.016 m; CrossSectionArea: 0.00020106 m2; BarLength: 3.99163 m; Material: Steel

# IfcReinforcingBarType, no part of this type: type
PredefinedType: MAIN; NominalDiameter: 0.016 m; CrossSectionArea: 0.00020106 m2; BarLength: 2.23142 m; Material: Steel

# IfcReinforcingBarType, no part of this type: type
PredefinedType: MAIN; NominalDiameter: 0.016 m; CrossSectionArea: 0.00020106 m2; BarLength: 2.23142 m; Material: Steel

# IfcReinforcingBarType, no part of this type: type
PredefinedType: LIGATURE; NominalDiameter: 0.008 m; CrossSectionArea: 0.000050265 m2; BarLength: 1.8868 m; Material: Steel

# IfcReinforcingBarType, no part of this type: type
PredefinedType: MAIN; NominalDiameter: 0.016 m; CrossSectionArea: 0.00020106 m2; BarLength: 4.17413 m; Material: Steel

# IfcReinforcingBarType, no part of this type: type
PredefinedType: MAIN; NominalDiameter: 0.016 m; CrossSectionArea: 0.00020106 m2; BarLength: 3.75663 m; Material: Steel

# IfcReinforcingBarType, no part of this type: type
PredefinedType: MAIN; NominalDiameter: 0.016 m; CrossSectionArea: 0.00020106 m2; BarLength: 3.38163 m; Material: Steel

# IfcReinforcingBarType, no part of this type: type
PredefinedType: MAIN; NominalDiameter: 0.016 m; CrossSectionArea: 0.00020106 m2; BarLength: 3.00642 m; Material: Steel

# IfcReinforcingBarType, no part of this type: type
PredefinedType: MAIN; NominalDiameter: 0.016 m; CrossSectionArea: 0.00020106 m2; BarLength: 2.95642 m; Material: Steel

# IfcReinforcingBarType, no part of this type: type
PredefinedType: LIGATURE; NominalDiameter: 0.008 m; CrossSectionArea: 0.000050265 m2; BarLength: 3.28679 m; Material: Steel

# IfcReinforcingBarType, no part of this type: type
PredefinedType: MAIN; NominalDiameter: 0.016 m; CrossSectionArea: 0.00020106 m2; BarLength: 4.20663 m; Material: Steel

# IfcReinforcingBarType, no part of this type: type
PredefinedType: MAIN; NominalDiameter: 0.016 m; CrossSectionArea: 0.00020106 m2; BarLength: 3.94913 m; Material: Steel

# IfcReinforcingBarType, no part of this type: type
PredefinedType: MAIN; NominalDiameter: 0.016 m; CrossSectionArea: 0.00020106 m2; BarLength: 3.76913 m; Material: Steel

# IfcReinforcingBarType, no part of this type: type
PredefinedType: MAIN; NominalDiameter: 0.016 m; CrossSectionArea: 0.00020106 m2; BarLength: 2.61892 m; Material: Steel

# IfcReinforcingBarType, no part of this type: type
PredefinedType: MAIN; NominalDiameter: 0.016 m; CrossSectionArea: 0.00020106 m2; BarLength: 2.56892 m; Material: Steel

# IfcReinforcingBarType, no part of this type: type
PredefinedType: LIGATURE; NominalDiameter: 0.008 m; CrossSectionArea: 0.000050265 m2; BarLength: 1.8868 m; Material: Steel

# IfcReinforcingBarType, no part of this type: type
PredefinedType: MAIN; NominalDiameter: 0.016 m; CrossSectionArea: 0.00020106 m2; BarLength: 4.81913 m; Material: Steel

# IfcReinforcingBarType, no part of this type: type
PredefinedType: MAIN; NominalDiameter: 0.016 m; CrossSectionArea: 0.00020106 m2; BarLength: 4.31913 m; Material: Steel

# IfcReinforcingBarType, no part of this type: type
PredefinedType: MAIN; NominalDiameter: 0.016 m; CrossSectionArea: 0.00020106 m2; BarLength: 5.07413 m; Material: Steel

# IfcReinforcingBarType, no part of this type: type
PredefinedType: MAIN; NominalDiameter: 0.016 m; CrossSectionArea: 0.00020106 m2; BarLength: 3.81708 m; Material: Steel

# IfcReinforcingBarType, no part of this type: type
PredefinedType: MAIN; NominalDiameter: 0.016 m; CrossSectionArea: 0.00020106 m2; BarLength: 4.16892 m; Material: Steel

# IfcReinforcingBarType, no part of this type: type
PredefinedType: MAIN; NominalDiameter: 0.016 m; CrossSectionArea: 0.00020106 m2; BarLength: 1.91187 m; Material: Steel

# IfcReinforcingBarType, no part of this type: type
PredefinedType: LIGATURE; NominalDiameter: 0.008 m; CrossSectionArea: 0.000050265 m2; BarLength: 1.8868 m; Material: Steel

# IfcReinforcingBarType, no part of this type: type
PredefinedType: MAIN; NominalDiameter: 0.016 m; CrossSectionArea: 0.00020106 m2; BarLength: 2.07142 m; Material: Steel

# IfcReinforcingBarType, no part of this type: type
PredefinedType: MAIN; NominalDiameter: 0.016 m; CrossSectionArea: 0.00020106 m2; BarLength: 1.99062 m; Material: Steel

# IfcReinforcingBarType, no part of this type: type
PredefinedType: LIGATURE; NominalDiameter: 0.008 m; CrossSectionArea: 0.000050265 m2; BarLength: 1.8868 m; Material: Steel

# IfcReinforcingBarType, no part of this type: type
PredefinedType: MAIN; NominalDiameter: 0.016 m; CrossSectionArea: 0.00020106 m2; BarLength: 2.60663 m; Material: Steel

# IfcReinforcingBarType, no part of this type: type
PredefinedType: MAIN; NominalDiameter: 0.016 m; CrossSectionArea: 0.00020106 m2; BarLength: 4.98163 m; Material: Steel

# IfcReinforcingBarType, no part of this type: type
PredefinedType: MAIN; NominalDiameter: 0.016 m; CrossSectionArea: 0.00020106 m2; BarLength: 3.34663 m; Material: Steel

# IfcReinforcingBarType, no part of this type: type
PredefinedType: MAIN; NominalDiameter: 0.016 m; CrossSectionArea: 0.00020106 m2; BarLength: 4.27163 m; Material: Steel

# IfcReinforcingBarType, no part of this type: type
PredefinedType: MAIN; NominalDiameter: 0.016 m; CrossSectionArea: 0.00020106 m2; BarLength: 4.25642 m; Material: Steel

# IfcReinforcingBarType, no part of this type: type
PredefinedType: MAIN; NominalDiameter: 0.016 m; CrossSectionArea: 0.00020106 m2; BarLength: 2.45642 m; Material: Steel

# IfcReinforcingBarType, no part of this type: type
PredefinedType: LIGATURE; NominalDiameter: 0.008 m; CrossSectionArea: 0.000050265 m2; BarLength: 1.8868 m; Material: Steel

# IfcReinforcingBarType, no part of this type: type
PredefinedType: MAIN; NominalDiameter: 0.016 m; CrossSectionArea: 0.00020106 m2; BarLength: 2.07142 m; Material: Steel

# IfcReinforcingBarType, no part of this type: type
PredefinedType: MAIN; NominalDiameter: 0.016 m; CrossSectionArea: 0.00020106 m2; BarLength: 1.99062 m; Material: Steel

# IfcReinforcingBarType, no part of this type: type
PredefinedType: LIGATURE; NominalDiameter: 0.008 m; CrossSectionArea: 0.000050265 m2; BarLength: 1.8868 m; Material: Steel

# IfcReinforcingBarType, no part of this type: type
PredefinedType: MAIN; NominalDiameter: 0.016 m; CrossSectionArea: 0.00020106 m2; BarLength: 4.81913 m; Material: Steel

# IfcReinforcingBarType, no part of this type: type
PredefinedType: MAIN; NominalDiameter: 0.016 m; CrossSectionArea: 0.00020106 m2; BarLength: 5.07413 m; Material: Steel

# IfcReinforcingBarType, no part of this type: type
PredefinedType: MAIN; NominalDiameter: 0.016 m; CrossSectionArea: 0.00020106 m2; BarLength: 4.31913 m; Material: Steel

# IfcReinforcingBarType, no part of this type: type
PredefinedType: MAIN; NominalDiameter: 0.016 m; CrossSectionArea: 0.00020106 m2; BarLength: 2.47642 m; Material: Steel

# IfcReinforcingBarType, no part of this type: type
PredefinedType: MAIN; NominalDiameter: 0.016 m; CrossSectionArea: 0.00020106 m2; BarLength: 2.11187 m; Material: Steel

# IfcReinforcingBarType, no part of this type: type
PredefinedType: MAIN; NominalDiameter: 0.016 m; CrossSectionArea: 0.00020106 m2; BarLength: 4.16892 m; Material: Steel

# IfcReinforcingBarType, no part of this type: type
PredefinedType: MAIN; NominalDiameter: 0.016 m; CrossSectionArea: 0.00020106 m2; BarLength: 1.91187 m; Material: Steel

# IfcReinforcingBarType, no part of this type: type
PredefinedType: LIGATURE; NominalDiameter: 0.008 m; CrossSectionArea: 0.000050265 m2; BarLength: 1.8868 m; Material: Steel

# IfcReinforcingBarType, no part of this type: type
PredefinedType: MAIN; NominalDiameter: 0.016 m; CrossSectionArea: 0.00020106 m2; BarLength: 1.93407 m; Material: Steel

# IfcReinforcingBarType, no part of this type: type
PredefinedType: MAIN; NominalDiameter: 0.016 m; CrossSectionArea: 0.00020106 m2; BarLength: 2.58413 m; Material: Steel

# IfcReinforcingBarType, no part of this type: type
PredefinedType: MAIN; NominalDiameter: 0.016 m; CrossSectionArea: 0.00020106 m2; BarLength: 2.05907 m; Material: Steel

# IfcReinforcingBarType, no part of this type: type
PredefinedType: MAIN; NominalDiameter: 0.016 m; CrossSectionArea: 0.00020106 m2; BarLength: 1.73142 m; Material: Steel

# IfcReinforcingBarType, no part of this type: type
PredefinedType: MAIN; NominalDiameter: 0.016 m; CrossSectionArea: 0.00020106 m2; BarLength: 1.59892 m; Material: Steel

# IfcReinforcingBarType, no part of this type: type
PredefinedType: LIGATURE; NominalDiameter: 0.008 m; CrossSectionArea: 0.000050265 m2; BarLength: 1.8868 m; Material: Steel

# IfcReinforcingBarType, no part of this type: type
PredefinedType: MAIN; NominalDiameter: 0.016 m; CrossSectionArea: 0.00020106 m2; BarLength: 1.93407 m; Material: Steel

# IfcReinforcingBarType, no part of this type: type
PredefinedType: MAIN; NominalDiameter: 0.016 m; CrossSectionArea: 0.00020106 m2; BarLength: 2.58413 m; Material: Steel

# IfcReinforcingBarType, no part of this type: type
PredefinedType: MAIN; NominalDiameter: 0.016 m; CrossSectionArea: 0.00020106 m2; BarLength: 2.05907 m; Material: Steel

# IfcReinforcingBarType, no part of this type: type
PredefinedType: MAIN; NominalDiameter: 0.016 m; CrossSectionArea: 0.00020106 m2; BarLength: 1.73142 m; Material: Steel

# IfcReinforcingBarType, no part of this type: type
PredefinedType: MAIN; NominalDiameter: 0.016 m; CrossSectionArea: 0.00020106 m2; BarLength: 1.59892 m; Material: Steel

# IfcReinforcingBarType, no part of this type: type
PredefinedType: LIGATURE; NominalDiameter: 0.008 m; CrossSectionArea: 0.000050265 m2; BarLength: 1.8868 m; Material: Steel

# IfcReinforcingBarType, no part of this type: type
PredefinedType: MAIN; NominalDiameter: 0.016 m; CrossSectionArea: 0.00020106 m2; BarLength: 3.03191 m; Material: Steel

# IfcReinforcingBarType, no part of this type: type
PredefinedType: MAIN; NominalDiameter: 0.016 m; CrossSectionArea: 0.00020106 m2; BarLength: 3.24447 m; Material: Steel

# IfcReinforcingBarType, no part of this type: type
PredefinedType: LIGATURE; NominalDiameter: 0.008 m; CrossSectionArea: 0.000050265 m2; BarLength: 1.8868 m; Material: Steel

# IfcReinforcingBarType, no part of this type: type
PredefinedType: MAIN; NominalDiameter: 0.016 m; CrossSectionArea: 0.00020106 m2; BarLength: 3.03191 m; Material: Steel

# IfcReinforcingBarType, no part of this type: type
PredefinedType: MAIN; NominalDiameter: 0.016 m; CrossSectionArea: 0.00020106 m2; BarLength: 3.24447 m; Material: Steel

# IfcReinforcingBarType, no part of this type: type
PredefinedType: LIGATURE; NominalDiameter: 0.008 m; CrossSectionArea: 0.000050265 m2; BarLength: 1.8868 m; Material: Steel

# IfcReinforcingBarType, no part of this type: type
PredefinedType: MAIN; NominalDiameter: 0.016 m; CrossSectionArea: 0.00020106 m2; BarLength: 2.61643 m; Material: Steel

# IfcReinforcingBarType, no part of this type: type
PredefinedType: MAIN; NominalDiameter: 0.016 m; CrossSectionArea: 0.00020106 m2; BarLength: 2.71643 m; Material: Steel

# IfcReinforcingBarType, no part of this type: type
PredefinedType: LIGATURE; NominalDiameter: 0.008 m; CrossSectionArea: 0.000050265 m2; BarLength: 1.8868 m; Material: Steel

# IfcReinforcingBarType, no part of this type: type
PredefinedType: MAIN; NominalDiameter: 0.016 m; CrossSectionArea: 0.00020106 m2; BarLength: 2.61643 m; Material: Steel

# IfcReinforcingBarType, no part of this type: type
PredefinedType: MAIN; NominalDiameter: 0.016 m; CrossSectionArea: 0.00020106 m2; BarLength: 2.71643 m; Material: Steel

# IfcReinforcingBarType, no part of this type: type
PredefinedType: LIGATURE; NominalDiameter: 0.008 m; CrossSectionArea: 0.000050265 m2; BarLength: 1.8868 m; Material: Steel

# IfcReinforcingBarType, no part of this type: type
PredefinedType: MAIN; NominalDiameter: 0.016 m; CrossSectionArea: 0.00020106 m2; BarLength: 2.43642 m; Material: Steel

# IfcReinforcingBarType, no part of this type: type
PredefinedType: MAIN; NominalDiameter: 0.016 m; CrossSectionArea: 0.00020106 m2; BarLength: 2.43642 m; Material: Steel

# IfcReinforcingBarType, no part of this type: type
PredefinedType: LIGATURE; NominalDiameter: 0.008 m; CrossSectionArea: 0.000050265 m2; BarLength: 2.58679 m; Material: Steel

# IfcReinforcingBarType, no part of this type: type
PredefinedType: MAIN; NominalDiameter: 0.014 m; CrossSectionArea: 0.00015394 m2; BarLength: 2.90094 m; Material: Steel

# IfcReinforcingBarType, no part of this type: type
PredefinedType: MAIN; NominalDiameter: 0.014 m; CrossSectionArea: 0.00015394 m2; BarLength: 2.90094 m; Material: Steel

# IfcReinforcingBarType, no part of this type: type
PredefinedType: MAIN; NominalDiameter: 0.014 m; CrossSectionArea: 0.00015394 m2; BarLength: 1.89877 m; Material: Steel

# IfcReinforcingBarType, no part of this type: type
PredefinedType: MAIN; NominalDiameter: 0.014 m; CrossSectionArea: 0.00015394 m2; BarLength: 1.78579 m; Material: Steel

# IfcReinforcingBarType, no part of this type: type
PredefinedType: MAIN; NominalDiameter: 0.016 m; CrossSectionArea: 0.00020106 m2; BarLength: 3.93081 m; Material: Steel

# IfcReinforcingBarType, no part of this type: type
PredefinedType: MAIN; NominalDiameter: 0.016 m; CrossSectionArea: 0.00020106 m2; BarLength: 3.81782 m; Material: Steel

# IfcReinforcingBarType, no part of this type: type
PredefinedType: MAIN; NominalDiameter: 0.02 m; CrossSectionArea: 0.00031416 m2; BarLength: 2.26822 m; Material: Steel

# IfcReinforcingBarType, no part of this type: type
PredefinedType: MAIN; NominalDiameter: 0.014 m; CrossSectionArea: 0.00015394 m2; BarLength: 2.26822 m; Material: Steel

# IfcReinforcingBarType, no part of this type: type
PredefinedType: MAIN; NominalDiameter: 0.016 m; CrossSectionArea: 0.00020106 m2; BarLength: 2.00532 m; Material: Steel

# IfcReinforcingBarType, no part of this type: type
PredefinedType: MAIN; NominalDiameter: 0.014 m; CrossSectionArea: 0.00015394 m2; BarLength: 2.00532 m; Material: Steel

# IfcReinforcingBarType, no part of this type: type
PredefinedType: LIGATURE; NominalDiameter: 0.008 m; CrossSectionArea: 0.000050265 m2; BarLength: 1.08682 m; Material: Steel

# IfcReinforcingBarType, no part of this type: type
PredefinedType: MAIN; NominalDiameter: 0.016 m; CrossSectionArea: 0.00020106 m2; BarLength: 3.48121 m; Material: Steel

# IfcReinforcingBarType, no part of this type: type
PredefinedType: LIGATURE; NominalDiameter: 0.008 m; CrossSectionArea: 0.000050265 m2; BarLength: 1.8868 m; Material: Steel

# IfcReinforcingBarType, no part of this type: type
PredefinedType: MAIN; NominalDiameter: 0.016 m; CrossSectionArea: 0.00020106 m2; BarLength: 2.43642 m; Material: Steel

# IfcReinforcingBarType, no part of this type: type
PredefinedType: MAIN; NominalDiameter: 0.016 m; CrossSectionArea: 0.00020106 m2; BarLength: 2.43642 m; Material: Steel

# Material: Calcestruzzo classe C28/35
Calcestruzzo classe C28/35 - Mass Density: 2500; Poisson Ratio: 0.1; Shear Modulus: 1481280000; Thermal Expansion Coefficient: 0.00001; Young Modulus: 3258810112

# Material: Calcestruzzo classe C28/35
Calcestruzzo classe C28/35 - Mass Density: 2500; Poisson Ratio: 0.1; Shear Modulus: 1481280000; Thermal Expansion Coefficient: 0.00001; Young Modulus: 3258810112

# Material: Calcestruzzo classe C28/35
Calcestruzzo classe C28/35 - Mass Density: 2500; Poisson Ratio: 0.1; Shear Modulus: 1481280000; Thermal Expansion Coefficient: 0.00001; Young Modulus: 3258810112

# Material: Calcestruzzo classe C28/35
Calcestruzzo classe C28/35 - Mass Density: 2500; Poisson Ratio: 0.1; Shear Modulus: 1481280000; Thermal Expansion Coefficient: 0.00001; Young Modulus: 3258810112

# Material: Calcestruzzo classe C28/35
Calcestruzzo classe C28/35 - Mass Density: 2500; Poisson Ratio: 0.1; Shear Modulus: 1481280000; Thermal Expansion Coefficient: 0.00001; Young Modulus: 3258810112

# Material: Calcestruzzo classe C28/35
Calcestruzzo classe C28/35 - Mass Density: 2500; Poisson Ratio: 0.1; Shear Modulus: 1481280000; Thermal Expansion Coefficient: 0.00001; Young Modulus: 3258810112

# Material: Calcestruzzo classe C28/35
Calcestruzzo classe C28/35 - Mass Density: 2500; Poisson Ratio: 0.1; Shear Modulus: 1481280000; Thermal Expansion Coefficient: 0.00001; Young Modulus: 3258810112

# Material: Calcestruzzo classe C28/35
Calcestruzzo classe C28/35 - Mass Density: 2500; Poisson Ratio: 0.1; Shear Modulus: 1481280000; Thermal Expansion Coefficient: 0.00001; Young Modulus: 3258810112

# Material: Calcestruzzo classe C28/35
Calcestruzzo classe C28/35 - Mass Density: 2500; Poisson Ratio: 0.1; Shear Modulus: 1481280000; Thermal Expansion Coefficient: 0.00001; Young Modulus: 3258810112

# Material: Calcestruzzo classe C28/35
Calcestruzzo classe C28/35 - Mass Density: 2500; Poisson Ratio: 0.1; Shear Modulus: 1481280000; Thermal Expansion Coefficient: 0.00001; Young Modulus: 3258810112

# Material: Calcestruzzo classe C28/35
Calcestruzzo classe C28/35 - Mass Density: 2500; Poisson Ratio: 0.1; Shear Modulus: 1481280000; Thermal Expansion Coefficient: 0.00001; Young Modulus: 3258810112

# Material: Calcestruzzo classe C28/35
Calcestruzzo classe C28/35 - Mass Density: 2500; Poisson Ratio: 0.1; Shear Modulus: 1481280000; Thermal Expansion Coefficient: 0.00001; Young Modulus: 3258810112

# Material: Calcestruzzo classe C28/35
Calcestruzzo classe C28/35 - Mass Density: 2500; Poisson Ratio: 0.1; Shear Modulus: 1481280000; Thermal Expansion Coefficient: 0.00001; Young Modulus: 3258810112

# Material: Calcestruzzo classe C28/35
Calcestruzzo classe C28/35 - Mass Density: 2500; Poisson Ratio: 0.1; Shear Modulus: 1481280000; Thermal Expansion Coefficient: 0.00001; Young Modulus: 3258810112

# Material: Calcestruzzo classe C28/35
Calcestruzzo classe C28/35 - Mass Density: 2500; Poisson Ratio: 0.1; Shear Modulus: 1481280000; Thermal Expansion Coefficient: 0.00001; Young Modulus: 3258810112

# Material: Calcestruzzo classe C28/35
Calcestruzzo classe C28/35 - Mass Density: 2500; Poisson Ratio: 0.1; Shear Modulus: 1481280000; Thermal Expansion Coefficient: 0.00001; Young Modulus: 3258810112

# Material: Calcestruzzo classe C28/35
Calcestruzzo classe C28/35 - Mass Density: 2500; Poisson Ratio: 0.1; Shear Modulus: 1481280000; Thermal Expansion Coefficient: 0.00001; Young Modulus: 3258810112

# Material: Calcestruzzo classe C28/35
Calcestruzzo classe C28/35 - Mass Density: 2500; Poisson Ratio: 0.1; Shear Modulus: 1481280000; Thermal Expansion Coefficient: 0.00001; Young Modulus: 3258810112

# Material: Calcestruzzo classe C28/35
Calcestruzzo classe C28/35 - Mass Density: 2500; Poisson Ratio: 0.1; Shear Modulus: 1481280000; Thermal Expansion Coefficient: 0.00001; Young Modulus: 3258810112

# Material: Calcestruzzo classe C28/35
Calcestruzzo classe C28/35 - Mass Density: 2500; Poisson Ratio: 0.1; Shear Modulus: 1481280000; Thermal Expansion Coefficient: 0.00001; Young Modulus: 3258810112

# Material: Calcestruzzo classe C28/35
Calcestruzzo classe C28/35 - Mass Density: 2500; Poisson Ratio: 0.1; Shear Modulus: 1481280000; Thermal Expansion Coefficient: 0.00001; Young Modulus: 3258810112

# Material: Calcestruzzo classe C28/35
Calcestruzzo classe C28/35 - Mass Density: 2500; Poisson Ratio: 0.1; Shear Modulus: 1481280000; Thermal Expansion Coefficient: 0.00001; Young Modulus: 3258810112

# Material: Legname a media elasticità
Legname a media elasticità - Mass Density: 460; Poisson Ratio: 0.39; Shear Modulus: 75000000; Thermal Expansion Coefficient: 0.000004; Young Modulus: 1200000000

# Material: Calcestruzzo classe C28/35
Calcestruzzo classe C28/35 - Mass Density: 2500; Poisson Ratio: 0.1; Shear Modulus: 1481280000; Thermal Expansion Coefficient: 0.00001; Young Modulus: 3258810112

# Material: Calcestruzzo classe C28/35
Calcestruzzo classe C28/35 - Mass Density: 2500; Poisson Ratio: 0.1; Shear Modulus: 1481280000; Thermal Expansion Coefficient: 0.00001; Young Modulus: 3258810112

# Material: Legname a media elasticità
Legname a media elasticità - Mass Density: 460; Poisson Ratio: 0.39; Shear Modulus: 75000000; Thermal Expansion Coefficient: 0.000004; Young Modulus: 1200000000

# Material: Legname a media elasticità
Legname a media elasticità - Mass Density: 460; Poisson Ratio: 0.39; Shear Modulus: 75000000; Thermal Expansion Coefficient: 0.000004; Young Modulus: 1200000000

# Material: Calcestruzzo classe C28/35
Calcestruzzo classe C28/35 - Mass Density: 2500; Poisson Ratio: 0.1; Shear Modulus: 1481280000; Thermal Expansion Coefficient: 0.00001; Young Modulus: 3258810112

# Material: Calcestruzzo classe C28/35
Calcestruzzo classe C28/35 - Mass Density: 2500; Poisson Ratio: 0.1; Shear Modulus: 1481280000; Thermal Expansion Coefficient: 0.00001; Young Modulus: 3258810112

# Material: Calcestruzzo classe C28/35
Calcestruzzo classe C28/35 - Mass Density: 2500; Poisson Ratio: 0.1; Shear Modulus: 1481280000; Thermal Expansion Coefficient: 0.00001; Young Modulus: 3258810112

# Material: Legname a media elasticità
Legname a media elasticità - Mass Density: 460; Poisson Ratio: 0.39; Shear Modulus: 75000000; Thermal Expansion Coefficient: 0.000004; Young Modulus: 1200000000

# Material: Legname a media elasticità
Legname a media elasticità - Mass Density: 460; Poisson Ratio: 0.39; Shear Modulus: 75000000; Thermal Expansion Coefficient: 0.000004; Young Modulus: 1200000000

# Material: Legname a media elasticità
Legname a media elasticità - Mass Density: 460; Poisson Ratio: 0.39; Shear Modulus: 75000000; Thermal Expansion Coefficient: 0.000004; Young Modulus: 1200000000

# Material: Legname a media elasticità
Legname a media elasticità - Mass Density: 460; Poisson Ratio: 0.39; Shear Modulus: 75000000; Thermal Expansion Coefficient: 0.000004; Young Modulus: 1200000000

# Material: Legname a media elasticità
Legname a media elasticità - Mass Density: 460; Poisson Ratio: 0.39; Shear Modulus: 75000000; Thermal Expansion Coefficient: 0.000004; Young Modulus: 1200000000

# Material: Legname a media elasticità
Legname a media elasticità - Mass Density: 460; Poisson Ratio: 0.39; Shear Modulus: 75000000; Thermal Expansion Coefficient: 0.000004; Young Modulus: 1200000000

# Material: Legname a media elasticità
Legname a media elasticità - Mass Density: 460; Poisson Ratio: 0.39; Shear Modulus: 75000000; Thermal Expansion Coefficient: 0.000004; Young Modulus: 1200000000

# Material: Legname a media elasticità
Legname a media elasticità - Mass Density: 460; Poisson Ratio: 0.39; Shear Modulus: 75000000; Thermal Expansion Coefficient: 0.000004; Young Modulus: 1200000000

# Material: Legname a media elasticità
Legname a media elasticità - Mass Density: 460; Poisson Ratio: 0.39; Shear Modulus: 75000000; Thermal Expansion Coefficient: 0.000004; Young Modulus: 1200000000

# Material: Legname a media elasticità
Legname a media elasticità - Mass Density: 460; Poisson Ratio: 0.39; Shear Modulus: 75000000; Thermal Expansion Coefficient: 0.000004; Young Modulus: 1200000000

# Material: Legname a media elasticità
Legname a media elasticità - Mass Density: 460; Poisson Ratio: 0.39; Shear Modulus: 75000000; Thermal Expansion Coefficient: 0.000004; Young Modulus: 1200000000

# Material: Legname a media elasticità
Legname a media elasticità - Mass Density: 460; Poisson Ratio: 0.39; Shear Modulus: 75000000; Thermal Expansion Coefficient: 0.000004; Young Modulus: 1200000000

# Material: Legname a media elasticità
Legname a media elasticità - Mass Density: 460; Poisson Ratio: 0.39; Shear Modulus: 75000000; Thermal Expansion Coefficient: 0.000004; Young Modulus: 1200000000

# Material: Legname a media elasticità
Legname a media elasticità - Mass Density: 460; Poisson Ratio: 0.39; Shear Modulus: 75000000; Thermal Expansion Coefficient: 0.000004; Young Modulus: 1200000000

# Material: Legname a media elasticità
Legname a media elasticità - Mass Density: 460; Poisson Ratio: 0.39; Shear Modulus: 75000000; Thermal Expansion Coefficient: 0.000004; Young Modulus: 1200000000

# Material: Legname a media elasticità
Legname a media elasticità - Mass Density: 460; Poisson Ratio: 0.39; Shear Modulus: 75000000; Thermal Expansion Coefficient: 0.000004; Young Modulus: 1200000000

# Material: Legname a media elasticità
Legname a media elasticità - Mass Density: 460; Poisson Ratio: 0.39; Shear Modulus: 75000000; Thermal Expansion Coefficient: 0.000004; Young Modulus: 1200000000

# Material: Legname a media elasticità
Legname a media elasticità - Mass Density: 460; Poisson Ratio: 0.39; Shear Modulus: 75000000; Thermal Expansion Coefficient: 0.000004; Young Modulus: 1200000000

# Material: Legname a media elasticità
Legname a media elasticità - Mass Density: 460; Poisson Ratio: 0.39; Shear Modulus: 75000000; Thermal Expansion Coefficient: 0.000004; Young Modulus: 1200000000

# Material: Legname a media elasticità
Legname a media elasticità - Mass Density: 460; Poisson Ratio: 0.39; Shear Modulus: 75000000; Thermal Expansion Coefficient: 0.000004; Young Modulus: 1200000000

# Material: Legname a media elasticità
Legname a media elasticità - Mass Density: 460; Poisson Ratio: 0.39; Shear Modulus: 75000000; Thermal Expansion Coefficient: 0.000004; Young Modulus: 1200000000

# Material: Legname a media elasticità
Legname a media elasticità - Mass Density: 460; Poisson Ratio: 0.39; Shear Modulus: 75000000; Thermal Expansion Coefficient: 0.000004; Young Modulus: 1200000000

# Material: Legname a media elasticità
Legname a media elasticità - Mass Density: 460; Poisson Ratio: 0.39; Shear Modulus: 75000000; Thermal Expansion Coefficient: 0.000004; Young Modulus: 1200000000

# Material: Legname a media elasticità
Legname a media elasticità - Mass Density: 460; Poisson Ratio: 0.39; Shear Modulus: 75000000; Thermal Expansion Coefficient: 0.000004; Young Modulus: 1200000000

# Material: Legname a media elasticità
Legname a media elasticità - Mass Density: 460; Poisson Ratio: 0.39; Shear Modulus: 75000000; Thermal Expansion Coefficient: 0.000004; Young Modulus: 1200000000

# Material: Legname a media elasticità
Legname a media elasticità - Mass Density: 460; Poisson Ratio: 0.39; Shear Modulus: 75000000; Thermal Expansion Coefficient: 0.000004; Young Modulus: 1200000000

# Material: Calcestruzzo classe C28/35
Calcestruzzo classe C28/35 - Mass Density: 2500; Poisson Ratio: 0.1; Shear Modulus: 1481280000; Thermal Expansion Coefficient: 0.00001; Young Modulus: 3258810112

# Material: Calcestruzzo classe C28/35
Calcestruzzo classe C28/35 - Mass Density: 2500; Poisson Ratio: 0.1; Shear Modulus: 1481280000; Thermal Expansion Coefficient: 0.00001; Young Modulus: 3258810112

# Material: Legname a media elasticità
Legname a media elasticità - Mass Density: 460; Poisson Ratio: 0.39; Shear Modulus: 75000000; Thermal Expansion Coefficient: 0.000004; Young Modulus: 1200000000

# Material: Legname a media elasticità
Legname a media elasticità - Mass Density: 460; Poisson Ratio: 0.39; Shear Modulus: 75000000; Thermal Expansion Coefficient: 0.000004; Young Modulus: 1200000000

# Material: Legname a media elasticità
Legname a media elasticità - Mass Density: 460; Poisson Ratio: 0.39; Shear Modulus: 75000000; Thermal Expansion Coefficient: 0.000004; Young Modulus: 1200000000

# Material: Calcestruzzo classe C28/35
Calcestruzzo classe C28/35 - Mass Density: 2500; Poisson Ratio: 0.1; Shear Modulus: 1481280000; Thermal Expansion Coefficient: 0.00001; Young Modulus: 3258810112

# Material: Calcestruzzo classe C28/35
Calcestruzzo classe C28/35 - Mass Density: 2500; Poisson Ratio: 0.1; Shear Modulus: 1481280000; Thermal Expansion Coefficient: 0.00001; Young Modulus: 3258810112

# Material: Calcestruzzo classe C28/35
Calcestruzzo classe C28/35 - Mass Density: 2500; Poisson Ratio: 0.1; Shear Modulus: 1481280000; Thermal Expansion Coefficient: 0.00001; Young Modulus: 3258810112

# Material: Calcestruzzo classe C28/35
Calcestruzzo classe C28/35 - Mass Density: 2500; Poisson Ratio: 0.1; Shear Modulus: 1481280000; Thermal Expansion Coefficient: 0.00001; Young Modulus: 3258810112

# Material: Calcestruzzo classe C28/35
Calcestruzzo classe C28/35 - Mass Density: 2500; Poisson Ratio: 0.1; Shear Modulus: 1481280000; Thermal Expansion Coefficient: 0.00001; Young Modulus: 3258810112

# Material: Calcestruzzo classe C28/35
Calcestruzzo classe C28/35 - Mass Density: 2500; Poisson Ratio: 0.1; Shear Modulus: 1481280000; Thermal Expansion Coefficient: 0.00001; Young Modulus: 3258810112

# Material: Calcestruzzo classe C28/35
Calcestruzzo classe C28/35 - Mass Density: 2500; Poisson Ratio: 0.1; Shear Modulus: 1481280000; Thermal Expansion Coefficient: 0.00001; Young Modulus: 3258810112

# Material: Calcestruzzo classe C28/35
Calcestruzzo classe C28/35 - Mass Density: 2500; Poisson Ratio: 0.1; Shear Modulus: 1481280000; Thermal Expansion Coefficient: 0.00001; Young Modulus: 3258810112

# Material: Calcestruzzo classe C28/35
Calcestruzzo classe C28/35 - Mass Density: 2500; Poisson Ratio: 0.1; Shear Modulus: 1481280000; Thermal Expansion Coefficient: 0.00001; Young Modulus: 3258810112

# Material: Calcestruzzo classe C28/35
Calcestruzzo classe C28/35 - Mass Density: 2500; Poisson Ratio: 0.1; Shear Modulus: 1481280000; Thermal Expansion Coefficient: 0.00001; Young Modulus: 3258810112

# Material: Calcestruzzo classe C28/35
Calcestruzzo classe C28/35 - Mass Density: 2500; Poisson Ratio: 0.1; Shear Modulus: 1481280000; Thermal Expansion Coefficient: 0.00001; Young Modulus: 3258810112

# Material: Calcestruzzo classe C28/35
Calcestruzzo classe C28/35 - Mass Density: 2500; Poisson Ratio: 0.1; Shear Modulus: 1481280000; Thermal Expansion Coefficient: 0.00001; Young Modulus: 3258810112

# Material: Calcestruzzo classe C28/35
Calcestruzzo classe C28/35 - Mass Density: 2500; Poisson Ratio: 0.1; Shear Modulus: 1481280000; Thermal Expansion Coefficient: 0.00001; Young Modulus: 3258810112

# Material: Calcestruzzo classe C28/35
Calcestruzzo classe C28/35 - Mass Density: 2500; Poisson Ratio: 0.1; Shear Modulus: 1481280000; Thermal Expansion Coefficient: 0.00001; Young Modulus: 3258810112

# Material: Calcestruzzo classe C28/35
Calcestruzzo classe C28/35 - Mass Density: 2500; Poisson Ratio: 0.1; Shear Modulus: 1481280000; Thermal Expansion Coefficient: 0.00001; Young Modulus: 3258810112

# Material: Calcestruzzo classe C28/35
Calcestruzzo classe C28/35 - Mass Density: 2500; Poisson Ratio: 0.1; Shear Modulus: 1481280000; Thermal Expansion Coefficient: 0.00001; Young Modulus: 3258810112

# Material: Calcestruzzo classe C28/35
Calcestruzzo classe C28/35 - Mass Density: 2500; Poisson Ratio: 0.1; Shear Modulus: 1481280000; Thermal Expansion Coefficient: 0.00001; Young Modulus: 3258810112

# Material: Calcestruzzo classe C28/35
Calcestruzzo classe C28/35 - Mass Density: 2500; Poisson Ratio: 0.1; Shear Modulus: 1481280000; Thermal Expansion Coefficient: 0.00001; Young Modulus: 3258810112

# Material: Calcestruzzo classe C28/35
Calcestruzzo classe C28/35 - Mass Density: 2500; Poisson Ratio: 0.1; Shear Modulus: 1481280000; Thermal Expansion Coefficient: 0.00001; Young Modulus: 3258810112

# Material: Calcestruzzo classe C28/35
Calcestruzzo classe C28/35 - Mass Density: 2500; Poisson Ratio: 0.1; Shear Modulus: 1481280000; Thermal Expansion Coefficient: 0.00001; Young Modulus: 3258810112

# Material: Calcestruzzo classe C28/35
Calcestruzzo classe C28/35 - Mass Density: 2500; Poisson Ratio: 0.1; Shear Modulus: 1481280000; Thermal Expansion Coefficient: 0.00001; Young Modulus: 3258810112

# Material: Calcestruzzo classe C28/35
Calcestruzzo classe C28/35 - Mass Density: 2500; Poisson Ratio: 0.1; Shear Modulus: 1481280000; Thermal Expansion Coefficient: 0.00001; Young Modulus: 3258810112

# Material: Calcestruzzo classe C28/35
Calcestruzzo classe C28/35 - Mass Density: 2500; Poisson Ratio: 0.1; Shear Modulus: 1481280000; Thermal Expansion Coefficient: 0.00001; Young Modulus: 3258810112

# Material: Calcestruzzo classe C28/35
Calcestruzzo classe C28/35 - Mass Density: 2500; Poisson Ratio: 0.1; Shear Modulus: 1481280000; Thermal Expansion Coefficient: 0.00001; Young Modulus: 3258810112

# Material: Calcestruzzo classe C28/35
Calcestruzzo classe C28/35 - Mass Density: 2500; Poisson Ratio: 0.1; Shear Modulus: 1481280000; Thermal Expansion Coefficient: 0.00001; Young Modulus: 3258810112

# Material: Calcestruzzo classe C28/35
Calcestruzzo classe C28/35 - Mass Density: 2500; Poisson Ratio: 0.1; Shear Modulus: 1481280000; Thermal Expansion Coefficient: 0.00001; Young Modulus: 3258810112

# Material: Calcestruzzo classe C28/35
Calcestruzzo classe C28/35 - Mass Density: 2500; Poisson Ratio: 0.1; Shear Modulus: 1481280000; Thermal Expansion Coefficient: 0.00001; Young Modulus: 3258810112

# Material: Calcestruzzo classe C28/35
Calcestruzzo classe C28/35 - Mass Density: 2500; Poisson Ratio: 0.1; Shear Modulus: 1481280000; Thermal Expansion Coefficient: 0.00001; Young Modulus: 3258810112

# Material: Calcestruzzo classe C28/35
Calcestruzzo classe C28/35 - Mass Density: 2500; Poisson Ratio: 0.1; Shear Modulus: 1481280000; Thermal Expansion Coefficient: 0.00001; Young Modulus: 3258810112

# Material: Calcestruzzo classe C28/35
Calcestruzzo classe C28/35 - Mass Density: 2500; Poisson Ratio: 0.1; Shear Modulus: 1481280000; Thermal Expansion Coefficient: 0.00001; Young Modulus: 3258810112

# Material: Calcestruzzo classe C28/35
Calcestruzzo classe C28/35 - Mass Density: 2500; Poisson Ratio: 0.1; Shear Modulus: 1481280000; Thermal Expansion Coefficient: 0.00001; Young Modulus: 3258810112

# Material: Calcestruzzo classe C28/35
Calcestruzzo classe C28/35 - Mass Density: 2500; Poisson Ratio: 0.1; Shear Modulus: 1481280000; Thermal Expansion Coefficient: 0.00001; Young Modulus: 3258810112

# Material: Calcestruzzo classe C28/35
Calcestruzzo classe C28/35 - Mass Density: 2500; Poisson Ratio: 0.1; Shear Modulus: 1481280000; Thermal Expansion Coefficient: 0.00001; Young Modulus: 3258810112

# Material: Calcestruzzo classe C28/35
Calcestruzzo classe C28/35 - Mass Density: 2500; Poisson Ratio: 0.1; Shear Modulus: 1481280000; Thermal Expansion Coefficient: 0.00001; Young Modulus: 3258810112

# Material: Calcestruzzo classe C28/35
Calcestruzzo classe C28/35 - Mass Density: 2500; Poisson Ratio: 0.1; Shear Modulus: 1481280000; Thermal Expansion Coefficient: 0.00001; Young Modulus: 3258810112

# Material: Calcestruzzo classe C28/35
Calcestruzzo classe C28/35 - Mass Density: 2500; Poisson Ratio: 0.1; Shear Modulus: 1481280000; Thermal Expansion Coefficient: 0.00001; Young Modulus: 3258810112

# Material: Calcestruzzo classe C28/35
Calcestruzzo classe C28/35 - Mass Density: 2500; Poisson Ratio: 0.1; Shear Modulus: 1481280000; Thermal Expansion Coefficient: 0.00001; Young Modulus: 3258810112

# Material: Calcestruzzo classe C28/35
Calcestruzzo classe C28/35 - Mass Density: 2500; Poisson Ratio: 0.1; Shear Modulus: 1481280000; Thermal Expansion Coefficient: 0.00001; Young Modulus: 3258810112

# Material: Calcestruzzo classe C28/35
Calcestruzzo classe C28/35 - Mass Density: 2500; Poisson Ratio: 0.1; Shear Modulus: 1481280000; Thermal Expansion Coefficient: 0.00001; Young Modulus: 3258810112

# Material: Calcestruzzo classe C28/35
Calcestruzzo classe C28/35 - Mass Density: 2500; Poisson Ratio: 0.1; Shear Modulus: 1481280000; Thermal Expansion Coefficient: 0.00001; Young Modulus: 3258810112

# Material: Calcestruzzo classe C28/35
Calcestruzzo classe C28/35 - Mass Density: 2500; Poisson Ratio: 0.1; Shear Modulus: 1481280000; Thermal Expansion Coefficient: 0.00001; Young Modulus: 3258810112

# Material: Legname a media elasticità
Legname a media elasticità - Mass Density: 460; Poisson Ratio: 0.39; Shear Modulus: 75000000; Thermal Expansion Coefficient: 0.000004; Young Modulus: 1200000000

# Material: Calcestruzzo classe C28/35
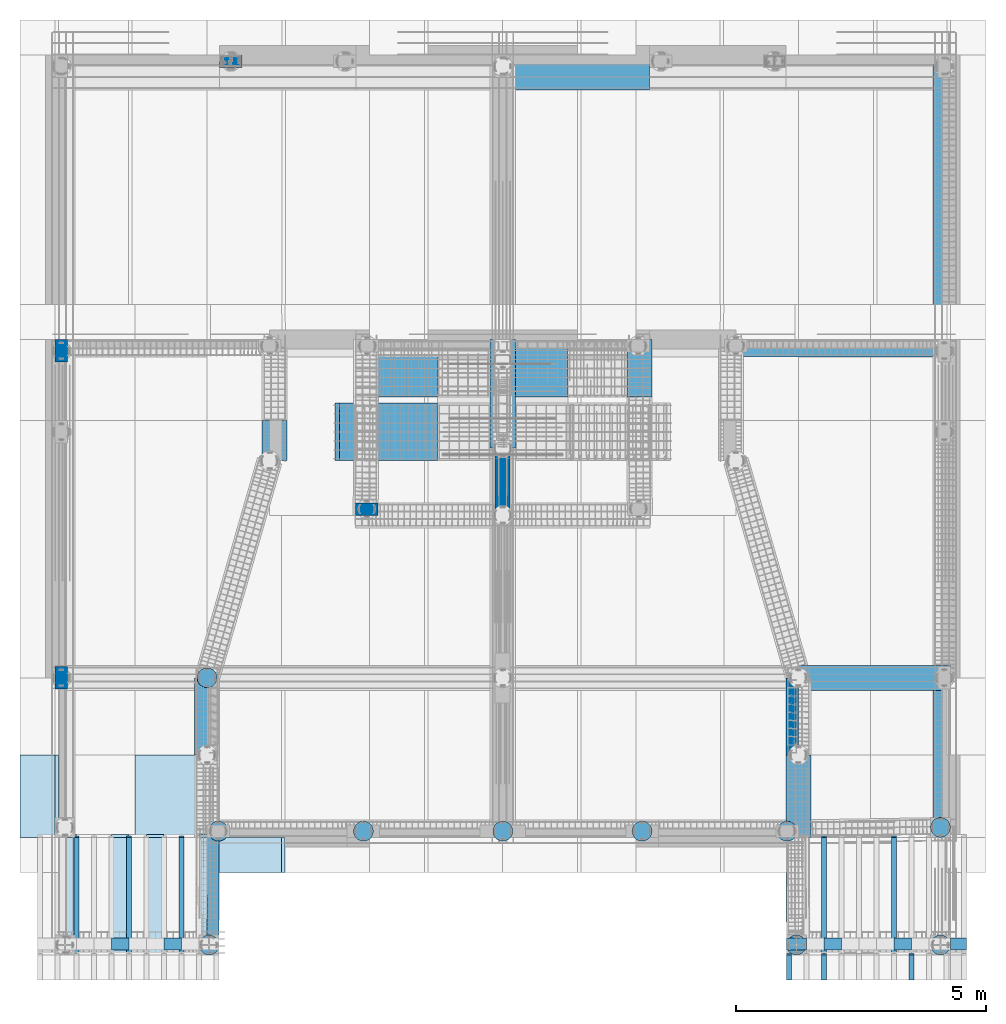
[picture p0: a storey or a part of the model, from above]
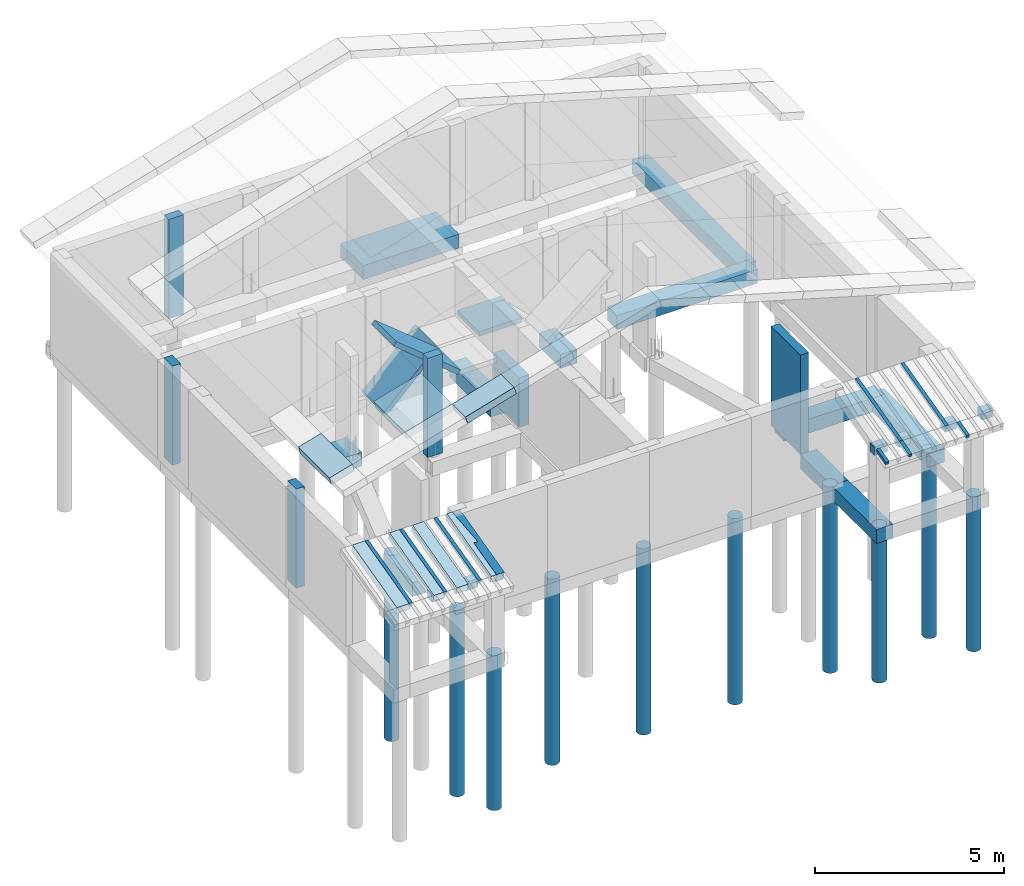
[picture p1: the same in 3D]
Properties of the parts of a building model (IFC4), part 4 of 5

Calcestruzzo classe C28/35 - Mass Density: 2500; Poisson Ratio: 0.1; Shear Modulus: 1481280000; Thermal Expansion Coefficient: 0.00001; Young Modulus: 3258810112

# Material: Legname a media elasticità
Legname a media elasticità - Mass Density: 460; Poisson Ratio: 0.39; Shear Modulus: 75000000; Thermal Expansion Coefficient: 0.000004; Young Modulus: 1200000000

# Material: Legname a media elasticità
Legname a media elasticità - Mass Density: 460; Poisson Ratio: 0.39; Shear Modulus: 75000000; Thermal Expansion Coefficient: 0.000004; Young Modulus: 1200000000

# Material: Calcestruzzo classe C28/35
Calcestruzzo classe C28/35 - Mass Density: 2500; Poisson Ratio: 0.1; Shear Modulus: 1481280000; Thermal Expansion Coefficient: 0.00001; Young Modulus: 3258810112

# Material: Legname a media elasticità
Legname a media elasticità - Mass Density: 460; Poisson Ratio: 0.39; Shear Modulus: 75000000; Thermal Expansion Coefficient: 0.000004; Young Modulus: 1200000000

# Material: Legname a media elasticità
Legname a media elasticità - Mass Density: 460; Poisson Ratio: 0.39; Shear Modulus: 75000000; Thermal Expansion Coefficient: 0.000004; Young Modulus: 1200000000

# Material: Legname a media elasticità
Legname a media elasticità - Mass Density: 460; Poisson Ratio: 0.39; Shear Modulus: 75000000; Thermal Expansion Coefficient: 0.000004; Young Modulus: 1200000000

# Material: Legname a media elasticità
Legname a media elasticità - Mass Density: 460; Poisson Ratio: 0.39; Shear Modulus: 75000000; Thermal Expansion Coefficient: 0.000004; Young Modulus: 1200000000

# Material: Legname a media elasticità
Legname a media elasticità - Mass Density: 460; Poisson Ratio: 0.39; Shear Modulus: 75000000; Thermal Expansion Coefficient: 0.000004; Young Modulus: 1200000000

# Material: Legname a media elasticità
Legname a media elasticità - Mass Density: 460; Poisson Ratio: 0.39; Shear Modulus: 75000000; Thermal Expansion Coefficient: 0.000004; Young Modulus: 1200000000

# Material: Legname a media elasticità
Legname a media elasticità - Mass Density: 460; Poisson Ratio: 0.39; Shear Modulus: 75000000; Thermal Expansion Coefficient: 0.000004; Young Modulus: 1200000000

# Material: Legname a media elasticità
Legname a media elasticità - Mass Density: 460; Poisson Ratio: 0.39; Shear Modulus: 75000000; Thermal Expansion Coefficient: 0.000004; Young Modulus: 1200000000

# Material: Legname a media elasticità
Legname a media elasticità - Mass Density: 460; Poisson Ratio: 0.39; Shear Modulus: 75000000; Thermal Expansion Coefficient: 0.000004; Young Modulus: 1200000000

# Material: Legname a media elasticità
Legname a media elasticità - Mass Density: 460; Poisson Ratio: 0.39; Shear Modulus: 75000000; Thermal Expansion Coefficient: 0.000004; Young Modulus: 1200000000

# Material: Legname a media elasticità
Legname a media elasticità - Mass Density: 460; Poisson Ratio: 0.39; Shear Modulus: 75000000; Thermal Expansion Coefficient: 0.000004; Young Modulus: 1200000000

# Material: Legname a media elasticità
Legname a media elasticità - Mass Density: 460; Poisson Ratio: 0.39; Shear Modulus: 75000000; Thermal Expansion Coefficient: 0.000004; Young Modulus: 1200000000

# Material: Legname a media elasticità
Legname a media elasticità - Mass Density: 460; Poisson Ratio: 0.39; Shear Modulus: 75000000; Thermal Expansion Coefficient: 0.000004; Young Modulus: 1200000000

# Material: Legname a media elasticità
Legname a media elasticità - Mass Density: 460; Poisson Ratio: 0.39; Shear Modulus: 75000000; Thermal Expansion Coefficient: 0.000004; Young Modulus: 1200000000

# Material: Legname a media elasticità
Legname a media elasticità - Mass Density: 460; Poisson Ratio: 0.39; Shear Modulus: 75000000; Thermal Expansion Coefficient: 0.000004; Young Modulus: 1200000000

# Material: Legname a media elasticità
Legname a media elasticità - Mass Density: 460; Poisson Ratio: 0.39; Shear Modulus: 75000000; Thermal Expansion Coefficient: 0.000004; Young Modulus: 1200000000

# Material: Legname a media elasticità
Legname a media elasticità - Mass Density: 460; Poisson Ratio: 0.39; Shear Modulus: 75000000; Thermal Expansion Coefficient: 0.000004; Young Modulus: 1200000000

# Material: Legname a media elasticità
Legname a media elasticità - Mass Density: 460; Poisson Ratio: 0.39; Shear Modulus: 75000000; Thermal Expansion Coefficient: 0.000004; Young Modulus: 1200000000

# Material: Legname a media elasticità
Legname a media elasticità - Mass Density: 460; Poisson Ratio: 0.39; Shear Modulus: 75000000; Thermal Expansion Coefficient: 0.000004; Young Modulus: 1200000000

# Material: Legname a media elasticità
Legname a media elasticità - Mass Density: 460; Poisson Ratio: 0.39; Shear Modulus: 75000000; Thermal Expansion Coefficient: 0.000004; Young Modulus: 1200000000

# Material: Legname a media elasticità
Legname a media elasticità - Mass Density: 460; Poisson Ratio: 0.39; Shear Modulus: 75000000; Thermal Expansion Coefficient: 0.000004; Young Modulus: 1200000000

# Material: Legname a media elasticità
Legname a media elasticità - Mass Density: 460; Poisson Ratio: 0.39; Shear Modulus: 75000000; Thermal Expansion Coefficient: 0.000004; Young Modulus: 1200000000

# Material: Legname a media elasticità
Legname a media elasticità - Mass Density: 460; Poisson Ratio: 0.39; Shear Modulus: 75000000; Thermal Expansion Coefficient: 0.000004; Young Modulus: 1200000000

# Material: Legname a media elasticità
Legname a media elasticità - Mass Density: 460; Poisson Ratio: 0.39; Shear Modulus: 75000000; Thermal Expansion Coefficient: 0.000004; Young Modulus: 1200000000

# Material: Legname a media elasticità
Legname a media elasticità - Mass Density: 460; Poisson Ratio: 0.39; Shear Modulus: 75000000; Thermal Expansion Coefficient: 0.000004; Young Modulus: 1200000000

# Material: Legname a media elasticità
Legname a media elasticità - Mass Density: 460; Poisson Ratio: 0.39; Shear Modulus: 75000000; Thermal Expansion Coefficient: 0.000004; Young Modulus: 1200000000

# Material: Legname a media elasticità
Legname a media elasticità - Mass Density: 460; Poisson Ratio: 0.39; Shear Modulus: 75000000; Thermal Expansion Coefficient: 0.000004; Young Modulus: 1200000000

# Material: Legname a media elasticità
Legname a media elasticità - Mass Density: 460; Poisson Ratio: 0.39; Shear Modulus: 75000000; Thermal Expansion Coefficient: 0.000004; Young Modulus: 1200000000

# Material: Legname a media elasticità
Legname a media elasticità - Mass Density: 460; Poisson Ratio: 0.39; Shear Modulus: 75000000; Thermal Expansion Coefficient: 0.000004; Young Modulus: 1200000000

# Material: Calcestruzzo classe C28/35
Calcestruzzo classe C28/35 - Mass Density: 2500; Poisson Ratio: 0.1; Shear Modulus: 1481280000; Thermal Expansion Coefficient: 0.00001; Young Modulus: 3258810112

# Material: Calcestruzzo classe C28/35
Calcestruzzo classe C28/35 - Mass Density: 2500; Poisson Ratio: 0.1; Shear Modulus: 1481280000; Thermal Expansion Coefficient: 0.00001; Young Modulus: 3258810112

# Material: Calcestruzzo classe C28/35
Calcestruzzo classe C28/35 - Mass Density: 2500; Poisson Ratio: 0.1; Shear Modulus: 1481280000; Thermal Expansion Coefficient: 0.00001; Young Modulus: 3258810112

# Material: Calcestruzzo classe C28/35
Calcestruzzo classe C28/35 - Mass Density: 2500; Poisson Ratio: 0.1; Shear Modulus: 1481280000; Thermal Expansion Coefficient: 0.00001; Young Modulus: 3258810112

# Material: Calcestruzzo classe C28/35
Calcestruzzo classe C28/35 - Mass Density: 2500; Poisson Ratio: 0.1; Shear Modulus: 1481280000; Thermal Expansion Coefficient: 0.00001; Young Modulus: 3258810112

# Material: Calcestruzzo classe C28/35
Calcestruzzo classe C28/35 - Mass Density: 2500; Poisson Ratio: 0.1; Shear Modulus: 1481280000; Thermal Expansion Coefficient: 0.00001; Young Modulus: 3258810112

# Material: Calcestruzzo classe C28/35
Calcestruzzo classe C28/35 - Mass Density: 2500; Poisson Ratio: 0.1; Shear Modulus: 1481280000; Thermal Expansion Coefficient: 0.00001; Young Modulus: 3258810112

# Material: Calcestruzzo classe C28/35
Calcestruzzo classe C28/35 - Mass Density: 2500; Poisson Ratio: 0.1; Shear Modulus: 1481280000; Thermal Expansion Coefficient: 0.00001; Young Modulus: 3258810112

# Material: Calcestruzzo classe C28/35
Calcestruzzo classe C28/35 - Mass Density: 2500; Poisson Ratio: 0.1; Shear Modulus: 1481280000; Thermal Expansion Coefficient: 0.00001; Young Modulus: 3258810112

# Material: Calcestruzzo classe C28/35
Calcestruzzo classe C28/35 - Mass Density: 2500; Poisson Ratio: 0.1; Shear Modulus: 1481280000; Thermal Expansion Coefficient: 0.00001; Young Modulus: 3258810112

# Material: Calcestruzzo classe C28/35
Calcestruzzo classe C28/35 - Mass Density: 2500; Poisson Ratio: 0.1; Shear Modulus: 1481280000; Thermal Expansion Coefficient: 0.00001; Young Modulus: 3258810112

# Material: Calcestruzzo classe C28/35
Calcestruzzo classe C28/35 - Mass Density: 2500; Poisson Ratio: 0.1; Shear Modulus: 1481280000; Thermal Expansion Coefficient: 0.00001; Young Modulus: 3258810112

# Material: Calcestruzzo classe C28/35
Calcestruzzo classe C28/35 - Mass Density: 2500; Poisson Ratio: 0.1; Shear Modulus: 1481280000; Thermal Expansion Coefficient: 0.00001; Young Modulus: 3258810112

# Material: Calcestruzzo classe C28/35
Calcestruzzo classe C28/35 - Mass Density: 2500; Poisson Ratio: 0.1; Shear Modulus: 1481280000; Thermal Expansion Coefficient: 0.00001; Young Modulus: 3258810112

# Material: Calcestruzzo classe C28/35
Calcestruzzo classe C28/35 - Mass Density: 2500; Poisson Ratio: 0.1; Shear Modulus: 1481280000; Thermal Expansion Coefficient: 0.00001; Young Modulus: 3258810112

# Material: Calcestruzzo classe C28/35
Calcestruzzo classe C28/35 - Mass Density: 2500; Poisson Ratio: 0.1; Shear Modulus: 1481280000; Thermal Expansion Coefficient: 0.00001; Young Modulus: 3258810112

# Material: Calcestruzzo classe C28/35
Calcestruzzo classe C28/35 - Mass Density: 2500; Poisson Ratio: 0.1; Shear Modulus: 1481280000; Thermal Expansion Coefficient: 0.00001; Young Modulus: 3258810112

# Material: Calcestruzzo classe C28/35
Calcestruzzo classe C28/35 - Mass Density: 2500; Poisson Ratio: 0.1; Shear Modulus: 1481280000; Thermal Expansion Coefficient: 0.00001; Young Modulus: 3258810112

# Material: Calcestruzzo classe C28/35
Calcestruzzo classe C28/35 - Mass Density: 2500; Poisson Ratio: 0.1; Shear Modulus: 1481280000; Thermal Expansion Coefficient: 0.00001; Young Modulus: 3258810112

# Material: Calcestruzzo classe C28/35
Calcestruzzo classe C28/35 - Mass Density: 2500; Poisson Ratio: 0.1; Shear Modulus: 1481280000; Thermal Expansion Coefficient: 0.00001; Young Modulus: 3258810112

# Material: Calcestruzzo classe C28/35
Calcestruzzo classe C28/35 - Mass Density: 2500; Poisson Ratio: 0.1; Shear Modulus: 1481280000; Thermal Expansion Coefficient: 0.00001; Young Modulus: 3258810112

# Material: Calcestruzzo classe C28/35
Calcestruzzo classe C28/35 - Mass Density: 2500; Poisson Ratio: 0.1; Shear Modulus: 1481280000; Thermal Expansion Coefficient: 0.00001; Young Modulus: 3258810112

# Material: Calcestruzzo classe C28/35
Calcestruzzo classe C28/35 - Mass Density: 2500; Poisson Ratio: 0.1; Shear Modulus: 1481280000; Thermal Expansion Coefficient: 0.00001; Young Modulus: 3258810112

# Material: Calcestruzzo classe C28/35
Calcestruzzo classe C28/35 - Mass Density: 2500; Poisson Ratio: 0.1; Shear Modulus: 1481280000; Thermal Expansion Coefficient: 0.00001; Young Modulus: 3258810112

# Material: Calcestruzzo classe C28/35
Calcestruzzo classe C28/35 - Mass Density: 2500; Poisson Ratio: 0.1; Shear Modulus: 1481280000; Thermal Expansion Coefficient: 0.00001; Young Modulus: 3258810112

# Material: Calcestruzzo classe C28/35
Calcestruzzo classe C28/35 - Mass Density: 2500; Poisson Ratio: 0.1; Shear Modulus: 1481280000; Thermal Expansion Coefficient: 0.00001; Young Modulus: 3258810112

# Material: Calcestruzzo classe C28/35
Calcestruzzo classe C28/35 - Mass Density: 2500; Poisson Ratio: 0.1; Shear Modulus: 1481280000; Thermal Expansion Coefficient: 0.00001; Young Modulus: 3258810112

# Material: Calcestruzzo classe C28/35
Calcestruzzo classe C28/35 - Mass Density: 2500; Poisson Ratio: 0.1; Shear Modulus: 1481280000; Thermal Expansion Coefficient: 0.00001; Young Modulus: 3258810112

# Material: Calcestruzzo classe C28/35
Calcestruzzo classe C28/35 - Mass Density: 2500; Poisson Ratio: 0.1; Shear Modulus: 1481280000; Thermal Expansion Coefficient: 0.00001; Young Modulus: 3258810112

# Material: Calcestruzzo classe C28/35
Calcestruzzo classe C28/35 - Mass Density: 2500; Poisson Ratio: 0.1; Shear Modulus: 1481280000; Thermal Expansion Coefficient: 0.00001; Young Modulus: 3258810112

# Material: Calcestruzzo classe C28/35
Calcestruzzo classe C28/35 - Mass Density: 2500; Poisson Ratio: 0.1; Shear Modulus: 1481280000; Thermal Expansion Coefficient: 0.00001; Young Modulus: 3258810112

# Material: Calcestruzzo classe C28/35
Calcestruzzo classe C28/35 - Mass Density: 2500; Poisson Ratio: 0.1; Shear Modulus: 1481280000; Thermal Expansion Coefficient: 0.00001; Young Modulus: 3258810112

# Material: Calcestruzzo classe C28/35
Calcestruzzo classe C28/35 - Mass Density: 2500; Poisson Ratio: 0.1; Shear Modulus: 1481280000; Thermal Expansion Coefficient: 0.00001; Young Modulus: 3258810112

# Material: Calcestruzzo classe C28/35
Calcestruzzo classe C28/35 - Mass Density: 2500; Poisson Ratio: 0.1; Shear Modulus: 1481280000; Thermal Expansion Coefficient: 0.00001; Young Modulus: 3258810112

# Material: Calcestruzzo classe C28/35
Calcestruzzo classe C28/35 - Mass Density: 2500; Poisson Ratio: 0.1; Shear Modulus: 1481280000; Thermal Expansion Coefficient: 0.00001; Young Modulus: 3258810112

# Material: Calcestruzzo classe C28/35
Calcestruzzo classe C28/35 - Mass Density: 2500; Poisson Ratio: 0.1; Shear Modulus: 1481280000; Thermal Expansion Coefficient: 0.00001; Young Modulus: 3258810112

# Material: Calcestruzzo classe C28/35
Calcestruzzo classe C28/35 - Mass Density: 2500; Poisson Ratio: 0.1; Shear Modulus: 1481280000; Thermal Expansion Coefficient: 0.00001; Young Modulus: 3258810112

# Material: Calcestruzzo classe C28/35
Calcestruzzo classe C28/35 - Mass Density: 2500; Poisson Ratio: 0.1; Shear Modulus: 1481280000; Thermal Expansion Coefficient: 0.00001; Young Modulus: 3258810112

# Material: Calcestruzzo classe C28/35
Calcestruzzo classe C28/35 - Mass Density: 2500; Poisson Ratio: 0.1; Shear Modulus: 1481280000; Thermal Expansion Coefficient: 0.00001; Young Modulus: 3258810112

# Material: Calcestruzzo classe C28/35
Calcestruzzo classe C28/35 - Mass Density: 2500; Poisson Ratio: 0.1; Shear Modulus: 1481280000; Thermal Expansion Coefficient: 0.00001; Young Modulus: 3258810112

# Material: Calcestruzzo classe C28/35
Calcestruzzo classe C28/35 - Mass Density: 2500; Poisson Ratio: 0.1; Shear Modulus: 1481280000; Thermal Expansion Coefficient: 0.00001; Young Modulus: 3258810112

# Material: Calcestruzzo classe C28/35
Calcestruzzo classe C28/35 - Mass Density: 2500; Poisson Ratio: 0.1; Shear Modulus: 1481280000; Thermal Expansion Coefficient: 0.00001; Young Modulus: 3258810112

# Material: Calcestruzzo classe C28/35
Calcestruzzo classe C28/35 - Mass Density: 2500; Poisson Ratio: 0.1; Shear Modulus: 1481280000; Thermal Expansion Coefficient: 0.00001; Young Modulus: 3258810112

# Material: Calcestruzzo classe C28/35
Calcestruzzo classe C28/35 - Mass Density: 2500; Poisson Ratio: 0.1; Shear Modulus: 1481280000; Thermal Expansion Coefficient: 0.00001; Young Modulus: 3258810112

# Material: Calcestruzzo classe C28/35
Calcestruzzo classe C28/35 - Mass Density: 2500; Poisson Ratio: 0.1; Shear Modulus: 1481280000; Thermal Expansion Coefficient: 0.00001; Young Modulus: 3258810112

# Material: Calcestruzzo classe C28/35
Calcestruzzo classe C28/35 - Mass Density: 2500; Poisson Ratio: 0.1; Shear Modulus: 1481280000; Thermal Expansion Coefficient: 0.00001; Young Modulus: 3258810112

# Material: Calcestruzzo classe C28/35
Calcestruzzo classe C28/35 - Mass Density: 2500; Poisson Ratio: 0.1; Shear Modulus: 1481280000; Thermal Expansion Coefficient: 0.00001; Young Modulus: 3258810112

# Material: Calcestruzzo classe C28/35
Calcestruzzo classe C28/35 - Mass Density: 2500; Poisson Ratio: 0.1; Shear Modulus: 1481280000; Thermal Expansion Coefficient: 0.00001; Young Modulus: 3258810112

# Material: Calcestruzzo classe C28/35
Calcestruzzo classe C28/35 - Mass Density: 2500; Poisson Ratio: 0.1; Shear Modulus: 1481280000; Thermal Expansion Coefficient: 0.00001; Young Modulus: 3258810112

# Material: Calcestruzzo classe C28/35
Calcestruzzo classe C28/35 - Mass Density: 2500; Poisson Ratio: 0.1; Shear Modulus: 1481280000; Thermal Expansion Coefficient: 0.00001; Young Modulus: 3258810112

# Material: Calcestruzzo classe C28/35
Calcestruzzo classe C28/35 - Mass Density: 2500; Poisson Ratio: 0.1; Shear Modulus: 1481280000; Thermal Expansion Coefficient: 0.00001; Young Modulus: 3258810112

# Material: Calcestruzzo classe C28/35
Calcestruzzo classe C28/35 - Mass Density: 2500; Poisson Ratio: 0.1; Shear Modulus: 1481280000; Thermal Expansion Coefficient: 0.00001; Young Modulus: 3258810112

# Material: Calcestruzzo classe C28/35
Calcestruzzo classe C28/35 - Mass Density: 2500; Poisson Ratio: 0.1; Shear Modulus: 1481280000; Thermal Expansion Coefficient: 0.00001; Young Modulus: 3258810112

# Material: Calcestruzzo classe C28/35
Calcestruzzo classe C28/35 - Mass Density: 2500; Poisson Ratio: 0.1; Shear Modulus: 1481280000; Thermal Expansion Coefficient: 0.00001; Young Modulus: 3258810112

# Material: Calcestruzzo classe C28/35
Calcestruzzo classe C28/35 - Mass Density: 2500; Poisson Ratio: 0.1; Shear Modulus: 1481280000; Thermal Expansion Coefficient: 0.00001; Young Modulus: 3258810112

# Material: Calcestruzzo classe C28/35
Calcestruzzo classe C28/35 - Mass Density: 2500; Poisson Ratio: 0.1; Shear Modulus: 1481280000; Thermal Expansion Coefficient: 0.00001; Young Modulus: 3258810112

# Material: Calcestruzzo classe C28/35
Calcestruzzo classe C28/35 - Mass Density: 2500; Poisson Ratio: 0.1; Shear Modulus: 1481280000; Thermal Expansion Coefficient: 0.00001; Young Modulus: 3258810112

# Material: Calcestruzzo classe C28/35
Calcestruzzo classe C28/35 - Mass Density: 2500; Poisson Ratio: 0.1; Shear Modulus: 1481280000; Thermal Expansion Coefficient: 0.00001; Young Modulus: 3258810112

# Material: Calcestruzzo classe C28/35
Calcestruzzo classe C28/35 - Mass Density: 2500; Poisson Ratio: 0.1; Shear Modulus: 1481280000; Thermal Expansion Coefficient: 0.00001; Young Modulus: 3258810112

# Material: Calcestruzzo classe C28/35
Calcestruzzo classe C28/35 - Mass Density: 2500; Poisson Ratio: 0.1; Shear Modulus: 1481280000; Thermal Expansion Coefficient: 0.00001; Young Modulus: 3258810112

# Material: Calcestruzzo classe C28/35
Calcestruzzo classe C28/35 - Mass Density: 2500; Poisson Ratio: 0.1; Shear Modulus: 1481280000; Thermal Expansion Coefficient: 0.00001; Young Modulus: 3258810112

# Material: Calcestruzzo classe C28/35
Calcestruzzo classe C28/35 - Mass Density: 2500; Poisson Ratio: 0.1; Shear Modulus: 1481280000; Thermal Expansion Coefficient: 0.00001; Young Modulus: 3258810112

# Material: Calcestruzzo classe C28/35
Calcestruzzo classe C28/35 - Mass Density: 2500; Poisson Ratio: 0.1; Shear Modulus: 1481280000; Thermal Expansion Coefficient: 0.00001; Young Modulus: 3258810112

# Material: Calcestruzzo classe C28/35
Calcestruzzo classe C28/35 - Mass Density: 2500; Poisson Ratio: 0.1; Shear Modulus: 1481280000; Thermal Expansion Coefficient: 0.00001; Young Modulus: 3258810112

# Material: Calcestruzzo classe C28/35
Calcestruzzo classe C28/35 - Mass Density: 2500; Poisson Ratio: 0.1; Shear Modulus: 1481280000; Thermal Expansion Coefficient: 0.00001; Young Modulus: 3258810112

# Material: Calcestruzzo classe C28/35
Calcestruzzo classe C28/35 - Mass Density: 2500; Poisson Ratio: 0.1; Shear Modulus: 1481280000; Thermal Expansion Coefficient: 0.00001; Young Modulus: 3258810112

# Material: Calcestruzzo classe C28/35
Calcestruzzo classe C28/35 - Mass Density: 2500; Poisson Ratio: 0.1; Shear Modulus: 1481280000; Thermal Expansion Coefficient: 0.00001; Young Modulus: 3258810112

# Material: Calcestruzzo classe C28/35
Calcestruzzo classe C28/35 - Mass Density: 2500; Poisson Ratio: 0.1; Shear Modulus: 1481280000; Thermal Expansion Coefficient: 0.00001; Young Modulus: 3258810112

# Material: Calcestruzzo classe C28/35
Calcestruzzo classe C28/35 - Mass Density: 2500; Poisson Ratio: 0.1; Shear Modulus: 1481280000; Thermal Expansion Coefficient: 0.00001; Young Modulus: 3258810112

# Material: Legname a media elasticità
Legname a media elasticità - Mass Density: 460; Poisson Ratio: 0.39; Shear Modulus: 75000000; Thermal Expansion Coefficient: 0.000004; Young Modulus: 1200000000

# Material: Calcestruzzo classe C28/35
Calcestruzzo classe C28/35 - Mass Density: 2500; Poisson Ratio: 0.1; Shear Modulus: 1481280000; Thermal Expansion Coefficient: 0.00001; Young Modulus: 3258810112

# Material: Legname a media elasticità
Legname a media elasticità - Mass Density: 460; Poisson Ratio: 0.39; Shear Modulus: 75000000; Thermal Expansion Coefficient: 0.000004; Young Modulus: 1200000000

# Material: Calcestruzzo classe C28/35
Calcestruzzo classe C28/35 - Mass Density: 2500; Poisson Ratio: 0.1; Shear Modulus: 1481280000; Thermal Expansion Coefficient: 0.00001; Young Modulus: 3258810112

# Material: Calcestruzzo classe C28/35
Calcestruzzo classe C28/35 - Mass Density: 2500; Poisson Ratio: 0.1; Shear Modulus: 1481280000; Thermal Expansion Coefficient: 0.00001; Young Modulus: 3258810112

# Material: Calcestruzzo classe C28/35
Calcestruzzo classe C28/35 - Mass Density: 2500; Poisson Ratio: 0.1; Shear Modulus: 1481280000; Thermal Expansion Coefficient: 0.00001; Young Modulus: 3258810112

# Material: Legname a media elasticità
Legname a media elasticità - Mass Density: 460; Poisson Ratio: 0.39; Shear Modulus: 75000000; Thermal Expansion Coefficient: 0.000004; Young Modulus: 1200000000

# Material: Calcestruzzo classe C28/35
Calcestruzzo classe C28/35 - Mass Density: 2500; Poisson Ratio: 0.1; Shear Modulus: 1481280000; Thermal Expansion Coefficient: 0.00001; Young Modulus: 3258810112

# Material: Legname a media elasticità
Legname a media elasticità - Mass Density: 460; Poisson Ratio: 0.39; Shear Modulus: 75000000; Thermal Expansion Coefficient: 0.000004; Young Modulus: 1200000000

# Material: Calcestruzzo classe C28/35
Calcestruzzo classe C28/35 - Mass Density: 2500; Poisson Ratio: 0.1; Shear Modulus: 1481280000; Thermal Expansion Coefficient: 0.00001; Young Modulus: 3258810112

# Material: Calcestruzzo classe C28/35
Calcestruzzo classe C28/35 - Mass Density: 2500; Poisson Ratio: 0.1; Shear Modulus: 1481280000; Thermal Expansion Coefficient: 0.00001; Young Modulus: 3258810112

# Material: Legname a media elasticità
Legname a media elasticità - Mass Density: 460; Poisson Ratio: 0.39; Shear Modulus: 75000000; Thermal Expansion Coefficient: 0.000004; Young Modulus: 1200000000

# Material: Calcestruzzo classe C28/35
Calcestruzzo classe C28/35 - Mass Density: 2500; Poisson Ratio: 0.1; Shear Modulus: 1481280000; Thermal Expansion Coefficient: 0.00001; Young Modulus: 3258810112

# Material: Legname a media elasticità
Legname a media elasticità - Mass Density: 460; Poisson Ratio: 0.39; Shear Modulus: 75000000; Thermal Expansion Coefficient: 0.000004; Young Modulus: 1200000000

# Material: Legname a media elasticità
Legname a media elasticità - Mass Density: 460; Poisson Ratio: 0.39; Shear Modulus: 75000000; Thermal Expansion Coefficient: 0.000004; Young Modulus: 1200000000

# Material: Calcestruzzo classe C28/35
Calcestruzzo classe C28/35 - Mass Density: 2500; Poisson Ratio: 0.1; Shear Modulus: 1481280000; Thermal Expansion Coefficient: 0.00001; Young Modulus: 3258810112

# Material: Calcestruzzo classe C28/35
Calcestruzzo classe C28/35 - Mass Density: 2500; Poisson Ratio: 0.1; Shear Modulus: 1481280000; Thermal Expansion Coefficient: 0.00001; Young Modulus: 3258810112

# Material: Legname a media elasticità
Legname a media elasticità - Mass Density: 460; Poisson Ratio: 0.39; Shear Modulus: 75000000; Thermal Expansion Coefficient: 0.000004; Young Modulus: 1200000000

# Material: Calcestruzzo classe C28/35
Calcestruzzo classe C28/35 - Mass Density: 2500; Poisson Ratio: 0.1; Shear Modulus: 1481280000; Thermal Expansion Coefficient: 0.00001; Young Modulus: 3258810112

# Material: Legname a media elasticità
Legname a media elasticità - Mass Density: 460; Poisson Ratio: 0.39; Shear Modulus: 75000000; Thermal Expansion Coefficient: 0.000004; Young Modulus: 1200000000

# Material: Calcestruzzo classe C28/35
Calcestruzzo classe C28/35 - Mass Density: 2500; Poisson Ratio: 0.1; Shear Modulus: 1481280000; Thermal Expansion Coefficient: 0.00001; Young Modulus: 3258810112

# Material: Legname a media elasticità
Legname a media elasticità - Mass Density: 460; Poisson Ratio: 0.39; Shear Modulus: 75000000; Thermal Expansion Coefficient: 0.000004; Young Modulus: 1200000000

# Material: Calcestruzzo classe C28/35
Calcestruzzo classe C28/35 - Mass Density: 2500; Poisson Ratio: 0.1; Shear Modulus: 1481280000; Thermal Expansion Coefficient: 0.00001; Young Modulus: 3258810112

# Material: Calcestruzzo classe C28/35
Calcestruzzo classe C28/35 - Mass Density: 2500; Poisson Ratio: 0.1; Shear Modulus: 1481280000; Thermal Expansion Coefficient: 0.00001; Young Modulus: 3258810112

# Material: Calcestruzzo classe C28/35
Calcestruzzo classe C28/35 - Mass Density: 2500; Poisson Ratio: 0.1; Shear Modulus: 1481280000; Thermal Expansion Coefficient: 0.00001; Young Modulus: 3258810112

# Material: Calcestruzzo classe C28/35
Calcestruzzo classe C28/35 - Mass Density: 2500; Poisson Ratio: 0.1; Shear Modulus: 1481280000; Thermal Expansion Coefficient: 0.00001; Young Modulus: 3258810112

# Material: Legname a media elasticità
Legname a media elasticità - Mass Density: 460; Poisson Ratio: 0.39; Shear Modulus: 75000000; Thermal Expansion Coefficient: 0.000004; Young Modulus: 1200000000

# Material: Legname a media elasticità
Legname a media elasticità - Mass Density: 460; Poisson Ratio: 0.39; Shear Modulus: 75000000; Thermal Expansion Coefficient: 0.000004; Young Modulus: 1200000000

# Material: Calcestruzzo classe C28/35
Calcestruzzo classe C28/35 - Mass Density: 2500; Poisson Ratio: 0.1; Shear Modulus: 1481280000; Thermal Expansion Coefficient: 0.00001; Young Modulus: 3258810112

# Material: Calcestruzzo classe C28/35
Calcestruzzo classe C28/35 - Mass Density: 2500; Poisson Ratio: 0.1; Shear Modulus: 1481280000; Thermal Expansion Coefficient: 0.00001; Young Modulus: 3258810112

# Material: Calcestruzzo classe C28/35
Calcestruzzo classe C28/35 - Mass Density: 2500; Poisson Ratio: 0.1; Shear Modulus: 1481280000; Thermal Expansion Coefficient: 0.00001; Young Modulus: 3258810112

# Material: Calcestruzzo classe C28/35
Calcestruzzo classe C28/35 - Mass Density: 2500; Poisson Ratio: 0.1; Shear Modulus: 1481280000; Thermal Expansion Coefficient: 0.00001; Young Modulus: 3258810112

# Material: Legname a media elasticità
Legname a media elasticità - Mass Density: 460; Poisson Ratio: 0.39; Shear Modulus: 75000000; Thermal Expansion Coefficient: 0.000004; Young Modulus: 1200000000

# Material: Calcestruzzo classe C28/35
Calcestruzzo classe C28/35 - Mass Density: 2500; Poisson Ratio: 0.1; Shear Modulus: 1481280000; Thermal Expansion Coefficient: 0.00001; Young Modulus: 3258810112

# Material: Calcestruzzo classe C28/35
Calcestruzzo classe C28/35 - Mass Density: 2500; Poisson Ratio: 0.1; Shear Modulus: 1481280000; Thermal Expansion Coefficient: 0.00001; Young Modulus: 3258810112

# Material: Legname a media elasticità
Legname a media elasticità - Mass Density: 460; Poisson Ratio: 0.39; Shear Modulus: 75000000; Thermal Expansion Coefficient: 0.000004; Young Modulus: 1200000000

# Material: Legname a media elasticità
Legname a media elasticità - Mass Density: 460; Poisson Ratio: 0.39; Shear Modulus: 75000000; Thermal Expansion Coefficient: 0.000004; Young Modulus: 1200000000

# Material: Calcestruzzo classe C28/35
Calcestruzzo classe C28/35 - Mass Density: 2500; Poisson Ratio: 0.1; Shear Modulus: 1481280000; Thermal Expansion Coefficient: 0.00001; Young Modulus: 3258810112

# Material: Legname a media elasticità
Legname a media elasticità - Mass Density: 460; Poisson Ratio: 0.39; Shear Modulus: 75000000; Thermal Expansion Coefficient: 0.000004; Young Modulus: 1200000000

# Material: Legname a media elasticità
Legname a media elasticità - Mass Density: 460; Poisson Ratio: 0.39; Shear Modulus: 75000000; Thermal Expansion Coefficient: 0.000004; Young Modulus: 1200000000

# Material: Calcestruzzo classe C28/35
Calcestruzzo classe C28/35 - Mass Density: 2500; Poisson Ratio: 0.1; Shear Modulus: 1481280000; Thermal Expansion Coefficient: 0.00001; Young Modulus: 3258810112

# Material: Calcestruzzo classe C28/35
Calcestruzzo classe C28/35 - Mass Density: 2500; Poisson Ratio: 0.1; Shear Modulus: 1481280000; Thermal Expansion Coefficient: 0.00001; Young Modulus: 3258810112

# Material: Calcestruzzo classe C28/35
Calcestruzzo classe C28/35 - Mass Density: 2500; Poisson Ratio: 0.1; Shear Modulus: 1481280000; Thermal Expansion Coefficient: 0.00001; Young Modulus: 3258810112

# Material: Calcestruzzo classe C28/35
Calcestruzzo classe C28/35 - Mass Density: 2500; Poisson Ratio: 0.1; Shear Modulus: 1481280000; Thermal Expansion Coefficient: 0.00001; Young Modulus: 3258810112

# Material: Calcestruzzo classe C28/35
Calcestruzzo classe C28/35 - Mass Density: 2500; Poisson Ratio: 0.1; Shear Modulus: 1481280000; Thermal Expansion Coefficient: 0.00001; Young Modulus: 3258810112

# Material: Calcestruzzo classe C28/35
Calcestruzzo classe C28/35 - Mass Density: 2500; Poisson Ratio: 0.1; Shear Modulus: 1481280000; Thermal Expansion Coefficient: 0.00001; Young Modulus: 3258810112

# Material: Calcestruzzo classe C28/35
Calcestruzzo classe C28/35 - Mass Density: 2500; Poisson Ratio: 0.1; Shear Modulus: 1481280000; Thermal Expansion Coefficient: 0.00001; Young Modulus: 3258810112

# Material: Calcestruzzo classe C28/35
Calcestruzzo classe C28/35 - Mass Density: 2500; Poisson Ratio: 0.1; Shear Modulus: 1481280000; Thermal Expansion Coefficient: 0.00001; Young Modulus: 3258810112

# Material: Calcestruzzo classe C28/35
Calcestruzzo classe C28/35 - Mass Density: 2500; Poisson Ratio: 0.1; Shear Modulus: 1481280000; Thermal Expansion Coefficient: 0.00001; Young Modulus: 3258810112

# Material: Calcestruzzo classe C28/35
Calcestruzzo classe C28/35 - Mass Density: 2500; Poisson Ratio: 0.1; Shear Modulus: 1481280000; Thermal Expansion Coefficient: 0.00001; Young Modulus: 3258810112

# Material: Calcestruzzo classe C28/35
Calcestruzzo classe C28/35 - Mass Density: 2500; Poisson Ratio: 0.1; Shear Modulus: 1481280000; Thermal Expansion Coefficient: 0.00001; Young Modulus: 3258810112

# Material: Legname a media elasticità
Legname a media elasticità - Mass Density: 460; Poisson Ratio: 0.39; Shear Modulus: 75000000; Thermal Expansion Coefficient: 0.000004; Young Modulus: 1200000000

# Material: Legname a media elasticità
Legname a media elasticità - Mass Density: 460; Poisson Ratio: 0.39; Shear Modulus: 75000000; Thermal Expansion Coefficient: 0.000004; Young Modulus: 1200000000

# Material: Calcestruzzo classe C28/35
Calcestruzzo classe C28/35 - Mass Density: 2500; Poisson Ratio: 0.1; Shear Modulus: 1481280000; Thermal Expansion Coefficient: 0.00001; Young Modulus: 3258810112

# Material: Calcestruzzo classe C28/35
Calcestruzzo classe C28/35 - Mass Density: 2500; Poisson Ratio: 0.1; Shear Modulus: 1481280000; Thermal Expansion Coefficient: 0.00001; Young Modulus: 3258810112

# Material: Legname a media elasticità
Legname a media elasticità - Mass Density: 460; Poisson Ratio: 0.39; Shear Modulus: 75000000; Thermal Expansion Coefficient: 0.000004; Young Modulus: 1200000000

# Material: Calcestruzzo classe C28/35
Calcestruzzo classe C28/35 - Mass Density: 2500; Poisson Ratio: 0.1; Shear Modulus: 1481280000; Thermal Expansion Coefficient: 0.00001; Young Modulus: 3258810112

# Material: Legname a media elasticità
Legname a media elasticità - Mass Density: 460; Poisson Ratio: 0.39; Shear Modulus: 75000000; Thermal Expansion Coefficient: 0.000004; Young Modulus: 1200000000

# Material: Legname a media elasticità
Legname a media elasticità - Mass Density: 460; Poisson Ratio: 0.39; Shear Modulus: 75000000; Thermal Expansion Coefficient: 0.000004; Young Modulus: 1200000000

# Material: Calcestruzzo classe C28/35
Calcestruzzo classe C28/35 - Mass Density: 2500; Poisson Ratio: 0.1; Shear Modulus: 1481280000; Thermal Expansion Coefficient: 0.00001; Young Modulus: 3258810112

# Material: Calcestruzzo classe C28/35
Calcestruzzo classe C28/35 - Mass Density: 2500; Poisson Ratio: 0.1; Shear Modulus: 1481280000; Thermal Expansion Coefficient: 0.00001; Young Modulus: 3258810112

# Material: Calcestruzzo classe C28/35
Calcestruzzo classe C28/35 - Mass Density: 2500; Poisson Ratio: 0.1; Shear Modulus: 1481280000; Thermal Expansion Coefficient: 0.00001; Young Modulus: 3258810112

# Material: Calcestruzzo classe C28/35
Calcestruzzo classe C28/35 - Mass Density: 2500; Poisson Ratio: 0.1; Shear Modulus: 1481280000; Thermal Expansion Coefficient: 0.00001; Young Modulus: 3258810112

# Material: Calcestruzzo classe C28/35
Calcestruzzo classe C28/35 - Mass Density: 2500; Poisson Ratio: 0.1; Shear Modulus: 1481280000; Thermal Expansion Coefficient: 0.00001; Young Modulus: 3258810112

# Material: Calcestruzzo classe C28/35
Calcestruzzo classe C28/35 - Mass Density: 2500; Poisson Ratio: 0.1; Shear Modulus: 1481280000; Thermal Expansion Coefficient: 0.00001; Young Modulus: 3258810112

# Material: Calcestruzzo classe C28/35
Calcestruzzo classe C28/35 - Mass Density: 2500; Poisson Ratio: 0.1; Shear Modulus: 1481280000; Thermal Expansion Coefficient: 0.00001; Young Modulus: 3258810112

# Material: Calcestruzzo classe C28/35
Calcestruzzo classe C28/35 - Mass Density: 2500; Poisson Ratio: 0.1; Shear Modulus: 1481280000; Thermal Expansion Coefficient: 0.00001; Young Modulus: 3258810112

# Material: Calcestruzzo classe C28/35
Calcestruzzo classe C28/35 - Mass Density: 2500; Poisson Ratio: 0.1; Shear Modulus: 1481280000; Thermal Expansion Coefficient: 0.00001; Young Modulus: 3258810112

# Material: Calcestruzzo classe C28/35
Calcestruzzo classe C28/35 - Mass Density: 2500; Poisson Ratio: 0.1; Shear Modulus: 1481280000; Thermal Expansion Coefficient: 0.00001; Young Modulus: 3258810112

# Material: Calcestruzzo classe C28/35
Calcestruzzo classe C28/35 - Mass Density: 2500; Poisson Ratio: 0.1; Shear Modulus: 1481280000; Thermal Expansion Coefficient: 0.00001; Young Modulus: 3258810112

# Material: Calcestruzzo classe C28/35
Calcestruzzo classe C28/35 - Mass Density: 2500; Poisson Ratio: 0.1; Shear Modulus: 1481280000; Thermal Expansion Coefficient: 0.00001; Young Modulus: 3258810112

# Material: Calcestruzzo classe C28/35
Calcestruzzo classe C28/35 - Mass Density: 2500; Poisson Ratio: 0.1; Shear Modulus: 1481280000; Thermal Expansion Coefficient: 0.00001; Young Modulus: 3258810112

# Material: Calcestruzzo classe C28/35
Calcestruzzo classe C28/35 - Mass Density: 2500; Poisson Ratio: 0.1; Shear Modulus: 1481280000; Thermal Expansion Coefficient: 0.00001; Young Modulus: 3258810112

# Material: Calcestruzzo classe C28/35
Calcestruzzo classe C28/35 - Mass Density: 2500; Poisson Ratio: 0.1; Shear Modulus: 1481280000; Thermal Expansion Coefficient: 0.00001; Young Modulus: 3258810112

# Material: Calcestruzzo classe C28/35
Calcestruzzo classe C28/35 - Mass Density: 2500; Poisson Ratio: 0.1; Shear Modulus: 1481280000; Thermal Expansion Coefficient: 0.00001; Young Modulus: 3258810112

# Material: Calcestruzzo classe C28/35
Calcestruzzo classe C28/35 - Mass Density: 2500; Poisson Ratio: 0.1; Shear Modulus: 1481280000; Thermal Expansion Coefficient: 0.00001; Young Modulus: 3258810112

# Material: Legname a media elasticità
Legname a media elasticità - Mass Density: 460; Poisson Ratio: 0.39; Shear Modulus: 75000000; Thermal Expansion Coefficient: 0.000004; Young Modulus: 1200000000

# Material: Calcestruzzo classe C28/35
Calcestruzzo classe C28/35 - Mass Density: 2500; Poisson Ratio: 0.1; Shear Modulus: 1481280000; Thermal Expansion Coefficient: 0.00001; Young Modulus: 3258810112

# Material: Calcestruzzo classe C28/35
Calcestruzzo classe C28/35 - Mass Density: 2500; Poisson Ratio: 0.1; Shear Modulus: 1481280000; Thermal Expansion Coefficient: 0.00001; Young Modulus: 3258810112

# Material: Calcestruzzo classe C28/35
Calcestruzzo classe C28/35 - Mass Density: 2500; Poisson Ratio: 0.1; Shear Modulus: 1481280000; Thermal Expansion Coefficient: 0.00001; Young Modulus: 3258810112

# Material: Calcestruzzo classe C28/35
Calcestruzzo classe C28/35 - Mass Density: 2500; Poisson Ratio: 0.1; Shear Modulus: 1481280000; Thermal Expansion Coefficient: 0.00001; Young Modulus: 3258810112

# Material: Calcestruzzo classe C28/35
Calcestruzzo classe C28/35 - Mass Density: 2500; Poisson Ratio: 0.1; Shear Modulus: 1481280000; Thermal Expansion Coefficient: 0.00001; Young Modulus: 3258810112

# Material: Calcestruzzo classe C28/35
Calcestruzzo classe C28/35 - Mass Density: 2500; Poisson Ratio: 0.1; Shear Modulus: 1481280000; Thermal Expansion Coefficient: 0.00001; Young Modulus: 3258810112

# Material: Calcestruzzo classe C28/35
Calcestruzzo classe C28/35 - Mass Density: 2500; Poisson Ratio: 0.1; Shear Modulus: 1481280000; Thermal Expansion Coefficient: 0.00001; Young Modulus: 3258810112

# Material: Calcestruzzo classe C28/35
Calcestruzzo classe C28/35 - Mass Density: 2500; Poisson Ratio: 0.1; Shear Modulus: 1481280000; Thermal Expansion Coefficient: 0.00001; Young Modulus: 3258810112

# Material: Calcestruzzo classe C28/35
Calcestruzzo classe C28/35 - Mass Density: 2500; Poisson Ratio: 0.1; Shear Modulus: 1481280000; Thermal Expansion Coefficient: 0.00001; Young Modulus: 3258810112

# Material: Calcestruzzo classe C28/35
Calcestruzzo classe C28/35 - Mass Density: 2500; Poisson Ratio: 0.1; Shear Modulus: 1481280000; Thermal Expansion Coefficient: 0.00001; Young Modulus: 3258810112

# Material: Calcestruzzo classe C28/35
Calcestruzzo classe C28/35 - Mass Density: 2500; Poisson Ratio: 0.1; Shear Modulus: 1481280000; Thermal Expansion Coefficient: 0.00001; Young Modulus: 3258810112

# Material: Calcestruzzo classe C28/35
Calcestruzzo classe C28/35 - Mass Density: 2500; Poisson Ratio: 0.1; Shear Modulus: 1481280000; Thermal Expansion Coefficient: 0.00001; Young Modulus: 3258810112

# Material: Legname a media elasticità
Legname a media elasticità - Mass Density: 460; Poisson Ratio: 0.39; Shear Modulus: 75000000; Thermal Expansion Coefficient: 0.000004; Young Modulus: 1200000000

# Material: Calcestruzzo classe C28/35
Calcestruzzo classe C28/35 - Mass Density: 2500; Poisson Ratio: 0.1; Shear Modulus: 1481280000; Thermal Expansion Coefficient: 0.00001; Young Modulus: 3258810112

# Material: Legname a media elasticità
Legname a media elasticità - Mass Density: 460; Poisson Ratio: 0.39; Shear Modulus: 75000000; Thermal Expansion Coefficient: 0.000004; Young Modulus: 1200000000

# Material: Calcestruzzo classe C28/35
Calcestruzzo classe C28/35 - Mass Density: 2500; Poisson Ratio: 0.1; Shear Modulus: 1481280000; Thermal Expansion Coefficient: 0.00001; Young Modulus: 3258810112

# Material: Calcestruzzo classe C28/35
Calcestruzzo classe C28/35 - Mass Density: 2500; Poisson Ratio: 0.1; Shear Modulus: 1481280000; Thermal Expansion Coefficient: 0.00001; Young Modulus: 3258810112

# Material: Calcestruzzo classe C28/35
Calcestruzzo classe C28/35 - Mass Density: 2500; Poisson Ratio: 0.1; Shear Modulus: 1481280000; Thermal Expansion Coefficient: 0.00001; Young Modulus: 3258810112

# Material: Calcestruzzo classe C28/35
Calcestruzzo classe C28/35 - Mass Density: 2500; Poisson Ratio: 0.1; Shear Modulus: 1481280000; Thermal Expansion Coefficient: 0.00001; Young Modulus: 3258810112

# Material: Calcestruzzo classe C28/35
Calcestruzzo classe C28/35 - Mass Density: 2500; Poisson Ratio: 0.1; Shear Modulus: 1481280000; Thermal Expansion Coefficient: 0.00001; Young Modulus: 3258810112

# Material: Calcestruzzo classe C28/35
Calcestruzzo classe C28/35 - Mass Density: 2500; Poisson Ratio: 0.1; Shear Modulus: 1481280000; Thermal Expansion Coefficient: 0.00001; Young Modulus: 3258810112

# Material: Calcestruzzo classe C28/35
Calcestruzzo classe C28/35 - Mass Density: 2500; Poisson Ratio: 0.1; Shear Modulus: 1481280000; Thermal Expansion Coefficient: 0.00001; Young Modulus: 3258810112

# Material: Calcestruzzo classe C28/35
Calcestruzzo classe C28/35 - Mass Density: 2500; Poisson Ratio: 0.1; Shear Modulus: 1481280000; Thermal Expansion Coefficient: 0.00001; Young Modulus: 3258810112

# Material: Legname a media elasticità
Legname a media elasticità - Mass Density: 460; Poisson Ratio: 0.39; Shear Modulus: 75000000; Thermal Expansion Coefficient: 0.000004; Young Modulus: 1200000000

# Material: Calcestruzzo classe C28/35
Calcestruzzo classe C28/35 - Mass Density: 2500; Poisson Ratio: 0.1; Shear Modulus: 1481280000; Thermal Expansion Coefficient: 0.00001; Young Modulus: 3258810112

# Material: Calcestruzzo classe C28/35
Calcestruzzo classe C28/35 - Mass Density: 2500; Poisson Ratio: 0.1; Shear Modulus: 1481280000; Thermal Expansion Coefficient: 0.00001; Young Modulus: 3258810112

# Material: Calcestruzzo classe C28/35
Calcestruzzo classe C28/35 - Mass Density: 2500; Poisson Ratio: 0.1; Shear Modulus: 1481280000; Thermal Expansion Coefficient: 0.00001; Young Modulus: 3258810112

# Material: Calcestruzzo classe C28/35
Calcestruzzo classe C28/35 - Mass Density: 2500; Poisson Ratio: 0.1; Shear Modulus: 1481280000; Thermal Expansion Coefficient: 0.00001; Young Modulus: 3258810112

# Material: Calcestruzzo classe C28/35
Calcestruzzo classe C28/35 - Mass Density: 2500; Poisson Ratio: 0.1; Shear Modulus: 1481280000; Thermal Expansion Coefficient: 0.00001; Young Modulus: 3258810112

# Material: Calcestruzzo classe C28/35
Calcestruzzo classe C28/35 - Mass Density: 2500; Poisson Ratio: 0.1; Shear Modulus: 1481280000; Thermal Expansion Coefficient: 0.00001; Young Modulus: 3258810112

# Material: Calcestruzzo classe C28/35
Calcestruzzo classe C28/35 - Mass Density: 2500; Poisson Ratio: 0.1; Shear Modulus: 1481280000; Thermal Expansion Coefficient: 0.00001; Young Modulus: 3258810112

# Material: Calcestruzzo classe C28/35
Calcestruzzo classe C28/35 - Mass Density: 2500; Poisson Ratio: 0.1; Shear Modulus: 1481280000; Thermal Expansion Coefficient: 0.00001; Young Modulus: 3258810112

# Material: Calcestruzzo classe C28/35
Calcestruzzo classe C28/35 - Mass Density: 2500; Poisson Ratio: 0.1; Shear Modulus: 1481280000; Thermal Expansion Coefficient: 0.00001; Young Modulus: 3258810112

# Material: Calcestruzzo classe C28/35
Calcestruzzo classe C28/35 - Mass Density: 2500; Poisson Ratio: 0.1; Shear Modulus: 1481280000; Thermal Expansion Coefficient: 0.00001; Young Modulus: 3258810112

# Material: Calcestruzzo classe C28/35
Calcestruzzo classe C28/35 - Mass Density: 2500; Poisson Ratio: 0.1; Shear Modulus: 1481280000; Thermal Expansion Coefficient: 0.00001; Young Modulus: 3258810112

# Material: Calcestruzzo classe C28/35
Calcestruzzo classe C28/35 - Mass Density: 2500; Poisson Ratio: 0.1; Shear Modulus: 1481280000; Thermal Expansion Coefficient: 0.00001; Young Modulus: 3258810112

# Material: Calcestruzzo classe C28/35
Calcestruzzo classe C28/35 - Mass Density: 2500; Poisson Ratio: 0.1; Shear Modulus: 1481280000; Thermal Expansion Coefficient: 0.00001; Young Modulus: 3258810112

# Material: Calcestruzzo classe C28/35
Calcestruzzo classe C28/35 - Mass Density: 2500; Poisson Ratio: 0.1; Shear Modulus: 1481280000; Thermal Expansion Coefficient: 0.00001; Young Modulus: 3258810112

# Material: Calcestruzzo classe C28/35
Calcestruzzo classe C28/35 - Mass Density: 2500; Poisson Ratio: 0.1; Shear Modulus: 1481280000; Thermal Expansion Coefficient: 0.00001; Young Modulus: 3258810112

# Material: Legname a media elasticità
Legname a media elasticità - Mass Density: 460; Poisson Ratio: 0.39; Shear Modulus: 75000000; Thermal Expansion Coefficient: 0.000004; Young Modulus: 1200000000

# Material: Calcestruzzo classe C28/35
Calcestruzzo classe C28/35 - Mass Density: 2500; Poisson Ratio: 0.1; Shear Modulus: 1481280000; Thermal Expansion Coefficient: 0.00001; Young Modulus: 3258810112

# Material: Legname a media elasticità
Legname a media elasticità - Mass Density: 460; Poisson Ratio: 0.39; Shear Modulus: 75000000; Thermal Expansion Coefficient: 0.000004; Young Modulus: 1200000000

# Material: Calcestruzzo classe C28/35
Calcestruzzo classe C28/35 - Mass Density: 2500; Poisson Ratio: 0.1; Shear Modulus: 1481280000; Thermal Expansion Coefficient: 0.00001; Young Modulus: 3258810112

# Material: Calcestruzzo classe C28/35
Calcestruzzo classe C28/35 - Mass Density: 2500; Poisson Ratio: 0.1; Shear Modulus: 1481280000; Thermal Expansion Coefficient: 0.00001; Young Modulus: 3258810112

# Material: Calcestruzzo classe C28/35
Calcestruzzo classe C28/35 - Mass Density: 2500; Poisson Ratio: 0.1; Shear Modulus: 1481280000; Thermal Expansion Coefficient: 0.00001; Young Modulus: 3258810112

# Material: Legname a media elasticità
Legname a media elasticità - Mass Density: 460; Poisson Ratio: 0.39; Shear Modulus: 75000000; Thermal Expansion Coefficient: 0.000004; Young Modulus: 1200000000

# Material: Calcestruzzo classe C28/35
Calcestruzzo classe C28/35 - Mass Density: 2500; Poisson Ratio: 0.1; Shear Modulus: 1481280000; Thermal Expansion Coefficient: 0.00001; Young Modulus: 3258810112

# Material: Legname a media elasticità
Legname a media elasticità - Mass Density: 460; Poisson Ratio: 0.39; Shear Modulus: 75000000; Thermal Expansion Coefficient: 0.000004; Young Modulus: 1200000000

# Material: Calcestruzzo classe C28/35
Calcestruzzo classe C28/35 - Mass Density: 2500; Poisson Ratio: 0.1; Shear Modulus: 1481280000; Thermal Expansion Coefficient: 0.00001; Young Modulus: 3258810112

# Material: Legname a media elasticità
Legname a media elasticità - Mass Density: 460; Poisson Ratio: 0.39; Shear Modulus: 75000000; Thermal Expansion Coefficient: 0.000004; Young Modulus: 1200000000

# Material: Calcestruzzo classe C28/35
Calcestruzzo classe C28/35 - Mass Density: 2500; Poisson Ratio: 0.1; Shear Modulus: 1481280000; Thermal Expansion Coefficient: 0.00001; Young Modulus: 3258810112

# Material: Legname a media elasticità
Legname a media elasticità - Mass Density: 460; Poisson Ratio: 0.39; Shear Modulus: 75000000; Thermal Expansion Coefficient: 0.000004; Young Modulus: 1200000000

# Material: Legname a media elasticità
Legname a media elasticità - Mass Density: 460; Poisson Ratio: 0.39; Shear Modulus: 75000000; Thermal Expansion Coefficient: 0.000004; Young Modulus: 1200000000

# Material: Calcestruzzo classe C28/35
Calcestruzzo classe C28/35 - Mass Density: 2500; Poisson Ratio: 0.1; Shear Modulus: 1481280000; Thermal Expansion Coefficient: 0.00001; Young Modulus: 3258810112

# Material: Calcestruzzo classe C28/35
Calcestruzzo classe C28/35 - Mass Density: 2500; Poisson Ratio: 0.1; Shear Modulus: 1481280000; Thermal Expansion Coefficient: 0.00001; Young Modulus: 3258810112

# Material: Legname a media elasticità
Legname a media elasticità - Mass Density: 460; Poisson Ratio: 0.39; Shear Modulus: 75000000; Thermal Expansion Coefficient: 0.000004; Young Modulus: 1200000000

# Material: Calcestruzzo classe C28/35
Calcestruzzo classe C28/35 - Mass Density: 2500; Poisson Ratio: 0.1; Shear Modulus: 1481280000; Thermal Expansion Coefficient: 0.00001; Young Modulus: 3258810112

# Material: Legname a media elasticità
Legname a media elasticità - Mass Density: 460; Poisson Ratio: 0.39; Shear Modulus: 75000000; Thermal Expansion Coefficient: 0.000004; Young Modulus: 1200000000

# Material: Calcestruzzo classe C28/35
Calcestruzzo classe C28/35 - Mass Density: 2500; Poisson Ratio: 0.1; Shear Modulus: 1481280000; Thermal Expansion Coefficient: 0.00001; Young Modulus: 3258810112

# Material: Legname a media elasticità
Legname a media elasticità - Mass Density: 460; Poisson Ratio: 0.39; Shear Modulus: 75000000; Thermal Expansion Coefficient: 0.000004; Young Modulus: 1200000000

# Material: Calcestruzzo classe C28/35
Calcestruzzo classe C28/35 - Mass Density: 2500; Poisson Ratio: 0.1; Shear Modulus: 1481280000; Thermal Expansion Coefficient: 0.00001; Young Modulus: 3258810112

# Material: Calcestruzzo classe C28/35
Calcestruzzo classe C28/35 - Mass Density: 2500; Poisson Ratio: 0.1; Shear Modulus: 1481280000; Thermal Expansion Coefficient: 0.00001; Young Modulus: 3258810112

# Material: Legname a media elasticità
Legname a media elasticità - Mass Density: 460; Poisson Ratio: 0.39; Shear Modulus: 75000000; Thermal Expansion Coefficient: 0.000004; Young Modulus: 1200000000

# Material: Legname a media elasticità
Legname a media elasticità - Mass Density: 460; Poisson Ratio: 0.39; Shear Modulus: 75000000; Thermal Expansion Coefficient: 0.000004; Young Modulus: 1200000000

# Material: Calcestruzzo classe C28/35
Calcestruzzo classe C28/35 - Mass Density: 2500; Poisson Ratio: 0.1; Shear Modulus: 1481280000; Thermal Expansion Coefficient: 0.00001; Young Modulus: 3258810112

# Material: Legname a media elasticità
Legname a media elasticità - Mass Density: 460; Poisson Ratio: 0.39; Shear Modulus: 75000000; Thermal Expansion Coefficient: 0.000004; Young Modulus: 1200000000

# Material: Legname a media elasticità
Legname a media elasticità - Mass Density: 460; Poisson Ratio: 0.39; Shear Modulus: 75000000; Thermal Expansion Coefficient: 0.000004; Young Modulus: 1200000000

# Material: Legname a media elasticità
Legname a media elasticità - Mass Density: 460; Poisson Ratio: 0.39; Shear Modulus: 75000000; Thermal Expansion Coefficient: 0.000004; Young Modulus: 1200000000

# Material: Legname a media elasticità
Legname a media elasticità - Mass Density: 460; Poisson Ratio: 0.39; Shear Modulus: 75000000; Thermal Expansion Coefficient: 0.000004; Young Modulus: 1200000000

# Material: Legname a media elasticità
Legname a media elasticità - Mass Density: 460; Poisson Ratio: 0.39; Shear Modulus: 75000000; Thermal Expansion Coefficient: 0.000004; Young Modulus: 1200000000

# Material: Legname a media elasticità
Legname a media elasticità - Mass Density: 460; Poisson Ratio: 0.39; Shear Modulus: 75000000; Thermal Expansion Coefficient: 0.000004; Young Modulus: 1200000000

# Material: Legname a media elasticità
Legname a media elasticità - Mass Density: 460; Poisson Ratio: 0.39; Shear Modulus: 75000000; Thermal Expansion Coefficient: 0.000004; Young Modulus: 1200000000

# Material: Legname a media elasticità
Legname a media elasticità - Mass Density: 460; Poisson Ratio: 0.39; Shear Modulus: 75000000; Thermal Expansion Coefficient: 0.000004; Young Modulus: 1200000000

# Material: Legname a media elasticità
Legname a media elasticità - Mass Density: 460; Poisson Ratio: 0.39; Shear Modulus: 75000000; Thermal Expansion Coefficient: 0.000004; Young Modulus: 1200000000

# Material: Legname a media elasticità
Legname a media elasticità - Mass Density: 460; Poisson Ratio: 0.39; Shear Modulus: 75000000; Thermal Expansion Coefficient: 0.000004; Young Modulus: 1200000000

# Material: Calcestruzzo classe C28/35
Calcestruzzo classe C28/35 - Mass Density: 2500; Poisson Ratio: 0.1; Shear Modulus: 1481280000; Thermal Expansion Coefficient: 0.00001; Young Modulus: 3258810112

# Material: Calcestruzzo classe C28/35
Calcestruzzo classe C28/35 - Mass Density: 2500; Poisson Ratio: 0.1; Shear Modulus: 1481280000; Thermal Expansion Coefficient: 0.00001; Young Modulus: 3258810112

# Material: Calcestruzzo classe C28/35
Calcestruzzo classe C28/35 - Mass Density: 2500; Poisson Ratio: 0.1; Shear Modulus: 1481280000; Thermal Expansion Coefficient: 0.00001; Young Modulus: 3258810112

# Material: Calcestruzzo classe C28/35
Calcestruzzo classe C28/35 - Mass Density: 2500; Poisson Ratio: 0.1; Shear Modulus: 1481280000; Thermal Expansion Coefficient: 0.00001; Young Modulus: 3258810112

# Material: Legname a media elasticità
Legname a media elasticità - Mass Density: 460; Poisson Ratio: 0.39; Shear Modulus: 75000000; Thermal Expansion Coefficient: 0.000004; Young Modulus: 1200000000

# Material: Calcestruzzo classe C28/35
Calcestruzzo classe C28/35 - Mass Density: 2500; Poisson Ratio: 0.1; Shear Modulus: 1481280000; Thermal Expansion Coefficient: 0.00001; Young Modulus: 3258810112

# Material: Legname a media elasticità
Legname a media elasticità - Mass Density: 460; Poisson Ratio: 0.39; Shear Modulus: 75000000; Thermal Expansion Coefficient: 0.000004; Young Modulus: 1200000000

# Material: Calcestruzzo classe C28/35
Calcestruzzo classe C28/35 - Mass Density: 2500; Poisson Ratio: 0.1; Shear Modulus: 1481280000; Thermal Expansion Coefficient: 0.00001; Young Modulus: 3258810112

# Material: Legname a media elasticità
Legname a media elasticità - Mass Density: 460; Poisson Ratio: 0.39; Shear Modulus: 75000000; Thermal Expansion Coefficient: 0.000004; Young Modulus: 1200000000

# Material: Legname a media elasticità
Legname a media elasticità - Mass Density: 460; Poisson Ratio: 0.39; Shear Modulus: 75000000; Thermal Expansion Coefficient: 0.000004; Young Modulus: 1200000000

# Material: Legname a media elasticità
Legname a media elasticità - Mass Density: 460; Poisson Ratio: 0.39; Shear Modulus: 75000000; Thermal Expansion Coefficient: 0.000004; Young Modulus: 1200000000

# Material: Calcestruzzo classe C28/35
Calcestruzzo classe C28/35 - Mass Density: 2500; Poisson Ratio: 0.1; Shear Modulus: 1481280000; Thermal Expansion Coefficient: 0.00001; Young Modulus: 3258810112

# Material: Legname a media elasticità
Legname a media elasticità - Mass Density: 460; Poisson Ratio: 0.39; Shear Modulus: 75000000; Thermal Expansion Coefficient: 0.000004; Young Modulus: 1200000000

# Material: Legname a media elasticità
Legname a media elasticità - Mass Density: 460; Poisson Ratio: 0.39; Shear Modulus: 75000000; Thermal Expansion Coefficient: 0.000004; Young Modulus: 1200000000

# Material: Legname a media elasticità
Legname a media elasticità - Mass Density: 460; Poisson Ratio: 0.39; Shear Modulus: 75000000; Thermal Expansion Coefficient: 0.000004; Young Modulus: 1200000000

# Material: Legname a media elasticità
Legname a media elasticità - Mass Density: 460; Poisson Ratio: 0.39; Shear Modulus: 75000000; Thermal Expansion Coefficient: 0.000004; Young Modulus: 1200000000

# Material: Legname a media elasticità
Legname a media elasticità - Mass Density: 460; Poisson Ratio: 0.39; Shear Modulus: 75000000; Thermal Expansion Coefficient: 0.000004; Young Modulus: 1200000000

# Material: Legname a media elasticità
Legname a media elasticità - Mass Density: 460; Poisson Ratio: 0.39; Shear Modulus: 75000000; Thermal Expansion Coefficient: 0.000004; Young Modulus: 1200000000

# Material: Legname a media elasticità
Legname a media elasticità - Mass Density: 460; Poisson Ratio: 0.39; Shear Modulus: 75000000; Thermal Expansion Coefficient: 0.000004; Young Modulus: 1200000000

# Material: Legname a media elasticità
Legname a media elasticità - Mass Density: 460; Poisson Ratio: 0.39; Shear Modulus: 75000000; Thermal Expansion Coefficient: 0.000004; Young Modulus: 1200000000

# Material: Calcestruzzo classe C28/35
Calcestruzzo classe C28/35 - Mass Density: 2500; Poisson Ratio: 0.1; Shear Modulus: 1481280000; Thermal Expansion Coefficient: 0.00001; Young Modulus: 3258810112

# Material: Calcestruzzo classe C28/35
Calcestruzzo classe C28/35 - Mass Density: 2500; Poisson Ratio: 0.1; Shear Modulus: 1481280000; Thermal Expansion Coefficient: 0.00001; Young Modulus: 3258810112

# Material: Calcestruzzo classe C28/35
Calcestruzzo classe C28/35 - Mass Density: 2500; Poisson Ratio: 0.1; Shear Modulus: 1481280000; Thermal Expansion Coefficient: 0.00001; Young Modulus: 3258810112

# Material: Calcestruzzo classe C28/35
Calcestruzzo classe C28/35 - Mass Density: 2500; Poisson Ratio: 0.1; Shear Modulus: 1481280000; Thermal Expansion Coefficient: 0.00001; Young Modulus: 3258810112

# Material: Calcestruzzo classe C28/35
Calcestruzzo classe C28/35 - Mass Density: 2500; Poisson Ratio: 0.1; Shear Modulus: 1481280000; Thermal Expansion Coefficient: 0.00001; Young Modulus: 3258810112

# Material: Calcestruzzo classe C28/35
Calcestruzzo classe C28/35 - Mass Density: 2500; Poisson Ratio: 0.1; Shear Modulus: 1481280000; Thermal Expansion Coefficient: 0.00001; Young Modulus: 3258810112

# Material: Calcestruzzo classe C28/35
Calcestruzzo classe C28/35 - Mass Density: 2500; Poisson Ratio: 0.1; Shear Modulus: 1481280000; Thermal Expansion Coefficient: 0.00001; Young Modulus: 3258810112

# Material: Calcestruzzo classe C28/35
Calcestruzzo classe C28/35 - Mass Density: 2500; Poisson Ratio: 0.1; Shear Modulus: 1481280000; Thermal Expansion Coefficient: 0.00001; Young Modulus: 3258810112

# Material: Calcestruzzo classe C28/35
Calcestruzzo classe C28/35 - Mass Density: 2500; Poisson Ratio: 0.1; Shear Modulus: 1481280000; Thermal Expansion Coefficient: 0.00001; Young Modulus: 3258810112

# Material: Calcestruzzo classe C28/35
Calcestruzzo classe C28/35 - Mass Density: 2500; Poisson Ratio: 0.1; Shear Modulus: 1481280000; Thermal Expansion Coefficient: 0.00001; Young Modulus: 3258810112

# Material: Calcestruzzo classe C28/35
Calcestruzzo classe C28/35 - Mass Density: 2500; Poisson Ratio: 0.1; Shear Modulus: 1481280000; Thermal Expansion Coefficient: 0.00001; Young Modulus: 3258810112

# Material: Calcestruzzo classe C28/35
Calcestruzzo classe C28/35 - Mass Density: 2500; Poisson Ratio: 0.1; Shear Modulus: 1481280000; Thermal Expansion Coefficient: 0.00001; Young Modulus: 3258810112

# Material: Calcestruzzo classe C28/35
Calcestruzzo classe C28/35 - Mass Density: 2500; Poisson Ratio: 0.1; Shear Modulus: 1481280000; Thermal Expansion Coefficient: 0.00001; Young Modulus: 3258810112

# Material: Calcestruzzo classe C28/35
Calcestruzzo classe C28/35 - Mass Density: 2500; Poisson Ratio: 0.1; Shear Modulus: 1481280000; Thermal Expansion Coefficient: 0.00001; Young Modulus: 3258810112

# Material: Calcestruzzo classe C28/35
Calcestruzzo classe C28/35 - Mass Density: 2500; Poisson Ratio: 0.1; Shear Modulus: 1481280000; Thermal Expansion Coefficient: 0.00001; Young Modulus: 3258810112

# Material: Calcestruzzo classe C28/35
Calcestruzzo classe C28/35 - Mass Density: 2500; Poisson Ratio: 0.1; Shear Modulus: 1481280000; Thermal Expansion Coefficient: 0.00001; Young Modulus: 3258810112

# Material: Calcestruzzo classe C28/35
Calcestruzzo classe C28/35 - Mass Density: 2500; Poisson Ratio: 0.1; Shear Modulus: 1481280000; Thermal Expansion Coefficient: 0.00001; Young Modulus: 3258810112

# Material: Calcestruzzo classe C28/35
Calcestruzzo classe C28/35 - Mass Density: 2500; Poisson Ratio: 0.1; Shear Modulus: 1481280000; Thermal Expansion Coefficient: 0.00001; Young Modulus: 3258810112

# Material: Calcestruzzo classe C28/35
Calcestruzzo classe C28/35 - Mass Density: 2500; Poisson Ratio: 0.1; Shear Modulus: 1481280000; Thermal Expansion Coefficient: 0.00001; Young Modulus: 3258810112

# Material: Calcestruzzo classe C28/35
Calcestruzzo classe C28/35 - Mass Density: 2500; Poisson Ratio: 0.1; Shear Modulus: 1481280000; Thermal Expansion Coefficient: 0.00001; Young Modulus: 3258810112

# Material: Calcestruzzo classe C28/35
Calcestruzzo classe C28/35 - Mass Density: 2500; Poisson Ratio: 0.1; Shear Modulus: 1481280000; Thermal Expansion Coefficient: 0.00001; Young Modulus: 3258810112

# Material: Calcestruzzo classe C28/35
Calcestruzzo classe C28/35 - Mass Density: 2500; Poisson Ratio: 0.1; Shear Modulus: 1481280000; Thermal Expansion Coefficient: 0.00001; Young Modulus: 3258810112

# Material: Calcestruzzo classe C28/35
Calcestruzzo classe C28/35 - Mass Density: 2500; Poisson Ratio: 0.1; Shear Modulus: 1481280000; Thermal Expansion Coefficient: 0.00001; Young Modulus: 3258810112

# Material: Calcestruzzo classe C28/35
